VERSION 5.8 ;
BUSBITCHARS "[]" ;
DIVIDERCHAR "/" ;
UNITS
    DATABASE MICRONS 1000 ;
END UNITS

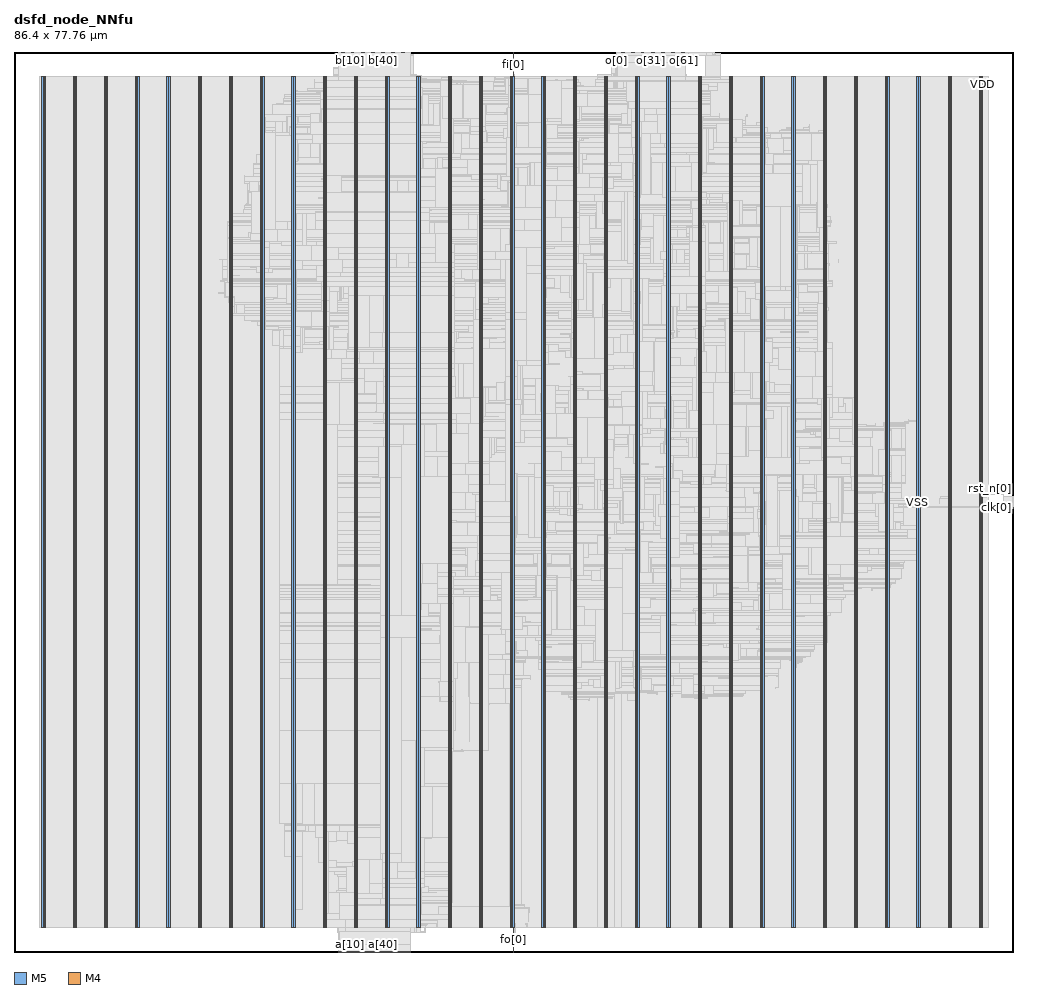
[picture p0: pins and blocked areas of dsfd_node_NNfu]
MACRO dsfd_node_NNfu
  FOREIGN dsfd_node_NNfu 0 0 ;
  CLASS BLOCK ;
  SIZE 86.4 BY 77.76 ;
  PIN a[0]
    DIRECTION INPUT ;
    USE SIGNAL ;
    PORT
      LAYER M5 ;
        RECT  28.032 0 28.056 0.084 ;
    END
  END a[0]
  PIN a[10]
    DIRECTION INPUT ;
    USE SIGNAL ;
    PORT
      LAYER M5 ;
        RECT  28.992 0 29.016 0.084 ;
    END
  END a[10]
  PIN a[11]
    DIRECTION INPUT ;
    USE SIGNAL ;
    PORT
      LAYER M5 ;
        RECT  29.088 0 29.112 0.084 ;
    END
  END a[11]
  PIN a[12]
    DIRECTION INPUT ;
    USE SIGNAL ;
    PORT
      LAYER M5 ;
        RECT  29.184 0 29.208 0.084 ;
    END
  END a[12]
  PIN a[13]
    DIRECTION INPUT ;
    USE SIGNAL ;
    PORT
      LAYER M5 ;
        RECT  29.28 0 29.304 0.084 ;
    END
  END a[13]
  PIN a[14]
    DIRECTION INPUT ;
    USE SIGNAL ;
    PORT
      LAYER M5 ;
        RECT  29.376 0 29.4 0.084 ;
    END
  END a[14]
  PIN a[15]
    DIRECTION INPUT ;
    USE SIGNAL ;
    PORT
      LAYER M5 ;
        RECT  29.472 0 29.496 0.084 ;
    END
  END a[15]
  PIN a[16]
    DIRECTION INPUT ;
    USE SIGNAL ;
    PORT
      LAYER M5 ;
        RECT  29.568 0 29.592 0.084 ;
    END
  END a[16]
  PIN a[17]
    DIRECTION INPUT ;
    USE SIGNAL ;
    PORT
      LAYER M5 ;
        RECT  29.664 0 29.688 0.084 ;
    END
  END a[17]
  PIN a[18]
    DIRECTION INPUT ;
    USE SIGNAL ;
    PORT
      LAYER M5 ;
        RECT  29.76 0 29.784 0.084 ;
    END
  END a[18]
  PIN a[19]
    DIRECTION INPUT ;
    USE SIGNAL ;
    PORT
      LAYER M5 ;
        RECT  29.856 0 29.88 0.084 ;
    END
  END a[19]
  PIN a[1]
    DIRECTION INPUT ;
    USE SIGNAL ;
    PORT
      LAYER M5 ;
        RECT  28.128 0 28.152 0.084 ;
    END
  END a[1]
  PIN a[20]
    DIRECTION INPUT ;
    USE SIGNAL ;
    PORT
      LAYER M5 ;
        RECT  29.952 0 29.976 0.084 ;
    END
  END a[20]
  PIN a[21]
    DIRECTION INPUT ;
    USE SIGNAL ;
    PORT
      LAYER M5 ;
        RECT  30.048 0 30.072 0.084 ;
    END
  END a[21]
  PIN a[22]
    DIRECTION INPUT ;
    USE SIGNAL ;
    PORT
      LAYER M5 ;
        RECT  30.144 0 30.168 0.084 ;
    END
  END a[22]
  PIN a[23]
    DIRECTION INPUT ;
    USE SIGNAL ;
    PORT
      LAYER M5 ;
        RECT  30.24 0 30.264 0.084 ;
    END
  END a[23]
  PIN a[24]
    DIRECTION INPUT ;
    USE SIGNAL ;
    PORT
      LAYER M5 ;
        RECT  30.336 0 30.36 0.084 ;
    END
  END a[24]
  PIN a[25]
    DIRECTION INPUT ;
    USE SIGNAL ;
    PORT
      LAYER M5 ;
        RECT  30.432 0 30.456 0.084 ;
    END
  END a[25]
  PIN a[26]
    DIRECTION INPUT ;
    USE SIGNAL ;
    PORT
      LAYER M5 ;
        RECT  30.528 0 30.552 0.084 ;
    END
  END a[26]
  PIN a[27]
    DIRECTION INPUT ;
    USE SIGNAL ;
    PORT
      LAYER M5 ;
        RECT  30.624 0 30.648 0.084 ;
    END
  END a[27]
  PIN a[28]
    DIRECTION INPUT ;
    USE SIGNAL ;
    PORT
      LAYER M5 ;
        RECT  30.72 0 30.744 0.084 ;
    END
  END a[28]
  PIN a[29]
    DIRECTION INPUT ;
    USE SIGNAL ;
    PORT
      LAYER M5 ;
        RECT  30.816 0 30.84 0.084 ;
    END
  END a[29]
  PIN a[2]
    DIRECTION INPUT ;
    USE SIGNAL ;
    PORT
      LAYER M5 ;
        RECT  28.224 0 28.248 0.084 ;
    END
  END a[2]
  PIN a[30]
    DIRECTION INPUT ;
    USE SIGNAL ;
    PORT
      LAYER M5 ;
        RECT  30.912 0 30.936 0.084 ;
    END
  END a[30]
  PIN a[31]
    DIRECTION INPUT ;
    USE SIGNAL ;
    PORT
      LAYER M5 ;
        RECT  31.008 0 31.032 0.084 ;
    END
  END a[31]
  PIN a[32]
    DIRECTION INPUT ;
    USE SIGNAL ;
    PORT
      LAYER M5 ;
        RECT  31.104 0 31.128 0.084 ;
    END
  END a[32]
  PIN a[33]
    DIRECTION INPUT ;
    USE SIGNAL ;
    PORT
      LAYER M5 ;
        RECT  31.2 0 31.224 0.084 ;
    END
  END a[33]
  PIN a[34]
    DIRECTION INPUT ;
    USE SIGNAL ;
    PORT
      LAYER M5 ;
        RECT  31.296 0 31.32 0.084 ;
    END
  END a[34]
  PIN a[35]
    DIRECTION INPUT ;
    USE SIGNAL ;
    PORT
      LAYER M5 ;
        RECT  31.392 0 31.416 0.084 ;
    END
  END a[35]
  PIN a[36]
    DIRECTION INPUT ;
    USE SIGNAL ;
    PORT
      LAYER M5 ;
        RECT  31.488 0 31.512 0.084 ;
    END
  END a[36]
  PIN a[37]
    DIRECTION INPUT ;
    USE SIGNAL ;
    PORT
      LAYER M5 ;
        RECT  31.584 0 31.608 0.084 ;
    END
  END a[37]
  PIN a[38]
    DIRECTION INPUT ;
    USE SIGNAL ;
    PORT
      LAYER M5 ;
        RECT  31.68 0 31.704 0.084 ;
    END
  END a[38]
  PIN a[39]
    DIRECTION INPUT ;
    USE SIGNAL ;
    PORT
      LAYER M5 ;
        RECT  31.776 0 31.8 0.084 ;
    END
  END a[39]
  PIN a[3]
    DIRECTION INPUT ;
    USE SIGNAL ;
    PORT
      LAYER M5 ;
        RECT  28.32 0 28.344 0.084 ;
    END
  END a[3]
  PIN a[40]
    DIRECTION INPUT ;
    USE SIGNAL ;
    PORT
      LAYER M5 ;
        RECT  31.872 0 31.896 0.084 ;
    END
  END a[40]
  PIN a[41]
    DIRECTION INPUT ;
    USE SIGNAL ;
    PORT
      LAYER M5 ;
        RECT  31.968 0 31.992 0.084 ;
    END
  END a[41]
  PIN a[42]
    DIRECTION INPUT ;
    USE SIGNAL ;
    PORT
      LAYER M5 ;
        RECT  32.064 0 32.088 0.084 ;
    END
  END a[42]
  PIN a[43]
    DIRECTION INPUT ;
    USE SIGNAL ;
    PORT
      LAYER M5 ;
        RECT  32.16 0 32.184 0.084 ;
    END
  END a[43]
  PIN a[44]
    DIRECTION INPUT ;
    USE SIGNAL ;
    PORT
      LAYER M5 ;
        RECT  32.256 0 32.28 0.084 ;
    END
  END a[44]
  PIN a[45]
    DIRECTION INPUT ;
    USE SIGNAL ;
    PORT
      LAYER M5 ;
        RECT  32.352 0 32.376 0.084 ;
    END
  END a[45]
  PIN a[46]
    DIRECTION INPUT ;
    USE SIGNAL ;
    PORT
      LAYER M5 ;
        RECT  32.448 0 32.472 0.084 ;
    END
  END a[46]
  PIN a[47]
    DIRECTION INPUT ;
    USE SIGNAL ;
    PORT
      LAYER M5 ;
        RECT  32.544 0 32.568 0.084 ;
    END
  END a[47]
  PIN a[48]
    DIRECTION INPUT ;
    USE SIGNAL ;
    PORT
      LAYER M5 ;
        RECT  32.64 0 32.664 0.084 ;
    END
  END a[48]
  PIN a[49]
    DIRECTION INPUT ;
    USE SIGNAL ;
    PORT
      LAYER M5 ;
        RECT  32.736 0 32.76 0.084 ;
    END
  END a[49]
  PIN a[4]
    DIRECTION INPUT ;
    USE SIGNAL ;
    PORT
      LAYER M5 ;
        RECT  28.416 0 28.44 0.084 ;
    END
  END a[4]
  PIN a[50]
    DIRECTION INPUT ;
    USE SIGNAL ;
    PORT
      LAYER M5 ;
        RECT  32.832 0 32.856 0.084 ;
    END
  END a[50]
  PIN a[51]
    DIRECTION INPUT ;
    USE SIGNAL ;
    PORT
      LAYER M5 ;
        RECT  32.928 0 32.952 0.084 ;
    END
  END a[51]
  PIN a[52]
    DIRECTION INPUT ;
    USE SIGNAL ;
    PORT
      LAYER M5 ;
        RECT  33.024 0 33.048 0.084 ;
    END
  END a[52]
  PIN a[53]
    DIRECTION INPUT ;
    USE SIGNAL ;
    PORT
      LAYER M5 ;
        RECT  33.12 0 33.144 0.084 ;
    END
  END a[53]
  PIN a[54]
    DIRECTION INPUT ;
    USE SIGNAL ;
    PORT
      LAYER M5 ;
        RECT  33.216 0 33.24 0.084 ;
    END
  END a[54]
  PIN a[55]
    DIRECTION INPUT ;
    USE SIGNAL ;
    PORT
      LAYER M5 ;
        RECT  33.312 0 33.336 0.084 ;
    END
  END a[55]
  PIN a[56]
    DIRECTION INPUT ;
    USE SIGNAL ;
    PORT
      LAYER M5 ;
        RECT  33.408 0 33.432 0.084 ;
    END
  END a[56]
  PIN a[57]
    DIRECTION INPUT ;
    USE SIGNAL ;
    PORT
      LAYER M5 ;
        RECT  33.504 0 33.528 0.084 ;
    END
  END a[57]
  PIN a[58]
    DIRECTION INPUT ;
    USE SIGNAL ;
    PORT
      LAYER M5 ;
        RECT  33.6 0 33.624 0.084 ;
    END
  END a[58]
  PIN a[59]
    DIRECTION INPUT ;
    USE SIGNAL ;
    PORT
      LAYER M5 ;
        RECT  33.696 0 33.72 0.084 ;
    END
  END a[59]
  PIN a[5]
    DIRECTION INPUT ;
    USE SIGNAL ;
    PORT
      LAYER M5 ;
        RECT  28.512 0 28.536 0.084 ;
    END
  END a[5]
  PIN a[60]
    DIRECTION INPUT ;
    USE SIGNAL ;
    PORT
      LAYER M5 ;
        RECT  33.792 0 33.816 0.084 ;
    END
  END a[60]
  PIN a[61]
    DIRECTION INPUT ;
    USE SIGNAL ;
    PORT
      LAYER M5 ;
        RECT  33.888 0 33.912 0.084 ;
    END
  END a[61]
  PIN a[62]
    DIRECTION INPUT ;
    USE SIGNAL ;
    PORT
      LAYER M5 ;
        RECT  33.984 0 34.008 0.084 ;
    END
  END a[62]
  PIN a[63]
    DIRECTION INPUT ;
    USE SIGNAL ;
    PORT
      LAYER M5 ;
        RECT  34.08 0 34.104 0.084 ;
    END
  END a[63]
  PIN a[64]
    DIRECTION INPUT ;
    USE SIGNAL ;
    PORT
      LAYER M5 ;
        RECT  34.176 0 34.2 0.084 ;
    END
  END a[64]
  PIN a[65]
    DIRECTION INPUT ;
    USE SIGNAL ;
    PORT
      LAYER M5 ;
        RECT  34.272 0 34.296 0.084 ;
    END
  END a[65]
  PIN a[6]
    DIRECTION INPUT ;
    USE SIGNAL ;
    PORT
      LAYER M5 ;
        RECT  28.608 0 28.632 0.084 ;
    END
  END a[6]
  PIN a[7]
    DIRECTION INPUT ;
    USE SIGNAL ;
    PORT
      LAYER M5 ;
        RECT  28.704 0 28.728 0.084 ;
    END
  END a[7]
  PIN a[8]
    DIRECTION INPUT ;
    USE SIGNAL ;
    PORT
      LAYER M5 ;
        RECT  28.8 0 28.824 0.084 ;
    END
  END a[8]
  PIN a[9]
    DIRECTION INPUT ;
    USE SIGNAL ;
    PORT
      LAYER M5 ;
        RECT  28.896 0 28.92 0.084 ;
    END
  END a[9]
  PIN b[0]
    DIRECTION INPUT ;
    USE SIGNAL ;
    PORT
      LAYER M5 ;
        RECT  28.032 77.676 28.056 77.76 ;
    END
  END b[0]
  PIN b[10]
    DIRECTION INPUT ;
    USE SIGNAL ;
    PORT
      LAYER M5 ;
        RECT  28.992 77.676 29.016 77.76 ;
    END
  END b[10]
  PIN b[11]
    DIRECTION INPUT ;
    USE SIGNAL ;
    PORT
      LAYER M5 ;
        RECT  29.088 77.676 29.112 77.76 ;
    END
  END b[11]
  PIN b[12]
    DIRECTION INPUT ;
    USE SIGNAL ;
    PORT
      LAYER M5 ;
        RECT  29.184 77.676 29.208 77.76 ;
    END
  END b[12]
  PIN b[13]
    DIRECTION INPUT ;
    USE SIGNAL ;
    PORT
      LAYER M5 ;
        RECT  29.28 77.676 29.304 77.76 ;
    END
  END b[13]
  PIN b[14]
    DIRECTION INPUT ;
    USE SIGNAL ;
    PORT
      LAYER M5 ;
        RECT  29.376 77.676 29.4 77.76 ;
    END
  END b[14]
  PIN b[15]
    DIRECTION INPUT ;
    USE SIGNAL ;
    PORT
      LAYER M5 ;
        RECT  29.472 77.676 29.496 77.76 ;
    END
  END b[15]
  PIN b[16]
    DIRECTION INPUT ;
    USE SIGNAL ;
    PORT
      LAYER M5 ;
        RECT  29.568 77.676 29.592 77.76 ;
    END
  END b[16]
  PIN b[17]
    DIRECTION INPUT ;
    USE SIGNAL ;
    PORT
      LAYER M5 ;
        RECT  29.664 77.676 29.688 77.76 ;
    END
  END b[17]
  PIN b[18]
    DIRECTION INPUT ;
    USE SIGNAL ;
    PORT
      LAYER M5 ;
        RECT  29.76 77.676 29.784 77.76 ;
    END
  END b[18]
  PIN b[19]
    DIRECTION INPUT ;
    USE SIGNAL ;
    PORT
      LAYER M5 ;
        RECT  29.856 77.676 29.88 77.76 ;
    END
  END b[19]
  PIN b[1]
    DIRECTION INPUT ;
    USE SIGNAL ;
    PORT
      LAYER M5 ;
        RECT  28.128 77.676 28.152 77.76 ;
    END
  END b[1]
  PIN b[20]
    DIRECTION INPUT ;
    USE SIGNAL ;
    PORT
      LAYER M5 ;
        RECT  29.952 77.676 29.976 77.76 ;
    END
  END b[20]
  PIN b[21]
    DIRECTION INPUT ;
    USE SIGNAL ;
    PORT
      LAYER M5 ;
        RECT  30.048 77.676 30.072 77.76 ;
    END
  END b[21]
  PIN b[22]
    DIRECTION INPUT ;
    USE SIGNAL ;
    PORT
      LAYER M5 ;
        RECT  30.144 77.676 30.168 77.76 ;
    END
  END b[22]
  PIN b[23]
    DIRECTION INPUT ;
    USE SIGNAL ;
    PORT
      LAYER M5 ;
        RECT  30.24 77.676 30.264 77.76 ;
    END
  END b[23]
  PIN b[24]
    DIRECTION INPUT ;
    USE SIGNAL ;
    PORT
      LAYER M5 ;
        RECT  30.336 77.676 30.36 77.76 ;
    END
  END b[24]
  PIN b[25]
    DIRECTION INPUT ;
    USE SIGNAL ;
    PORT
      LAYER M5 ;
        RECT  30.432 77.676 30.456 77.76 ;
    END
  END b[25]
  PIN b[26]
    DIRECTION INPUT ;
    USE SIGNAL ;
    PORT
      LAYER M5 ;
        RECT  30.528 77.676 30.552 77.76 ;
    END
  END b[26]
  PIN b[27]
    DIRECTION INPUT ;
    USE SIGNAL ;
    PORT
      LAYER M5 ;
        RECT  30.624 77.676 30.648 77.76 ;
    END
  END b[27]
  PIN b[28]
    DIRECTION INPUT ;
    USE SIGNAL ;
    PORT
      LAYER M5 ;
        RECT  30.72 77.676 30.744 77.76 ;
    END
  END b[28]
  PIN b[29]
    DIRECTION INPUT ;
    USE SIGNAL ;
    PORT
      LAYER M5 ;
        RECT  30.816 77.676 30.84 77.76 ;
    END
  END b[29]
  PIN b[2]
    DIRECTION INPUT ;
    USE SIGNAL ;
    PORT
      LAYER M5 ;
        RECT  28.224 77.676 28.248 77.76 ;
    END
  END b[2]
  PIN b[30]
    DIRECTION INPUT ;
    USE SIGNAL ;
    PORT
      LAYER M5 ;
        RECT  30.912 77.676 30.936 77.76 ;
    END
  END b[30]
  PIN b[31]
    DIRECTION INPUT ;
    USE SIGNAL ;
    PORT
      LAYER M5 ;
        RECT  31.008 77.676 31.032 77.76 ;
    END
  END b[31]
  PIN b[32]
    DIRECTION INPUT ;
    USE SIGNAL ;
    PORT
      LAYER M5 ;
        RECT  31.104 77.676 31.128 77.76 ;
    END
  END b[32]
  PIN b[33]
    DIRECTION INPUT ;
    USE SIGNAL ;
    PORT
      LAYER M5 ;
        RECT  31.2 77.676 31.224 77.76 ;
    END
  END b[33]
  PIN b[34]
    DIRECTION INPUT ;
    USE SIGNAL ;
    PORT
      LAYER M5 ;
        RECT  31.296 77.676 31.32 77.76 ;
    END
  END b[34]
  PIN b[35]
    DIRECTION INPUT ;
    USE SIGNAL ;
    PORT
      LAYER M5 ;
        RECT  31.392 77.676 31.416 77.76 ;
    END
  END b[35]
  PIN b[36]
    DIRECTION INPUT ;
    USE SIGNAL ;
    PORT
      LAYER M5 ;
        RECT  31.488 77.676 31.512 77.76 ;
    END
  END b[36]
  PIN b[37]
    DIRECTION INPUT ;
    USE SIGNAL ;
    PORT
      LAYER M5 ;
        RECT  31.584 77.676 31.608 77.76 ;
    END
  END b[37]
  PIN b[38]
    DIRECTION INPUT ;
    USE SIGNAL ;
    PORT
      LAYER M5 ;
        RECT  31.68 77.676 31.704 77.76 ;
    END
  END b[38]
  PIN b[39]
    DIRECTION INPUT ;
    USE SIGNAL ;
    PORT
      LAYER M5 ;
        RECT  31.776 77.676 31.8 77.76 ;
    END
  END b[39]
  PIN b[3]
    DIRECTION INPUT ;
    USE SIGNAL ;
    PORT
      LAYER M5 ;
        RECT  28.32 77.676 28.344 77.76 ;
    END
  END b[3]
  PIN b[40]
    DIRECTION INPUT ;
    USE SIGNAL ;
    PORT
      LAYER M5 ;
        RECT  31.872 77.676 31.896 77.76 ;
    END
  END b[40]
  PIN b[41]
    DIRECTION INPUT ;
    USE SIGNAL ;
    PORT
      LAYER M5 ;
        RECT  31.968 77.676 31.992 77.76 ;
    END
  END b[41]
  PIN b[42]
    DIRECTION INPUT ;
    USE SIGNAL ;
    PORT
      LAYER M5 ;
        RECT  32.064 77.676 32.088 77.76 ;
    END
  END b[42]
  PIN b[43]
    DIRECTION INPUT ;
    USE SIGNAL ;
    PORT
      LAYER M5 ;
        RECT  32.16 77.676 32.184 77.76 ;
    END
  END b[43]
  PIN b[44]
    DIRECTION INPUT ;
    USE SIGNAL ;
    PORT
      LAYER M5 ;
        RECT  32.256 77.676 32.28 77.76 ;
    END
  END b[44]
  PIN b[45]
    DIRECTION INPUT ;
    USE SIGNAL ;
    PORT
      LAYER M5 ;
        RECT  32.352 77.676 32.376 77.76 ;
    END
  END b[45]
  PIN b[46]
    DIRECTION INPUT ;
    USE SIGNAL ;
    PORT
      LAYER M5 ;
        RECT  32.448 77.676 32.472 77.76 ;
    END
  END b[46]
  PIN b[47]
    DIRECTION INPUT ;
    USE SIGNAL ;
    PORT
      LAYER M5 ;
        RECT  32.544 77.676 32.568 77.76 ;
    END
  END b[47]
  PIN b[48]
    DIRECTION INPUT ;
    USE SIGNAL ;
    PORT
      LAYER M5 ;
        RECT  32.64 77.676 32.664 77.76 ;
    END
  END b[48]
  PIN b[49]
    DIRECTION INPUT ;
    USE SIGNAL ;
    PORT
      LAYER M5 ;
        RECT  32.736 77.676 32.76 77.76 ;
    END
  END b[49]
  PIN b[4]
    DIRECTION INPUT ;
    USE SIGNAL ;
    PORT
      LAYER M5 ;
        RECT  28.416 77.676 28.44 77.76 ;
    END
  END b[4]
  PIN b[50]
    DIRECTION INPUT ;
    USE SIGNAL ;
    PORT
      LAYER M5 ;
        RECT  32.832 77.676 32.856 77.76 ;
    END
  END b[50]
  PIN b[51]
    DIRECTION INPUT ;
    USE SIGNAL ;
    PORT
      LAYER M5 ;
        RECT  32.928 77.676 32.952 77.76 ;
    END
  END b[51]
  PIN b[52]
    DIRECTION INPUT ;
    USE SIGNAL ;
    PORT
      LAYER M5 ;
        RECT  33.024 77.676 33.048 77.76 ;
    END
  END b[52]
  PIN b[53]
    DIRECTION INPUT ;
    USE SIGNAL ;
    PORT
      LAYER M5 ;
        RECT  33.12 77.676 33.144 77.76 ;
    END
  END b[53]
  PIN b[54]
    DIRECTION INPUT ;
    USE SIGNAL ;
    PORT
      LAYER M5 ;
        RECT  33.216 77.676 33.24 77.76 ;
    END
  END b[54]
  PIN b[55]
    DIRECTION INPUT ;
    USE SIGNAL ;
    PORT
      LAYER M5 ;
        RECT  33.312 77.676 33.336 77.76 ;
    END
  END b[55]
  PIN b[56]
    DIRECTION INPUT ;
    USE SIGNAL ;
    PORT
      LAYER M5 ;
        RECT  33.408 77.676 33.432 77.76 ;
    END
  END b[56]
  PIN b[57]
    DIRECTION INPUT ;
    USE SIGNAL ;
    PORT
      LAYER M5 ;
        RECT  33.504 77.676 33.528 77.76 ;
    END
  END b[57]
  PIN b[58]
    DIRECTION INPUT ;
    USE SIGNAL ;
    PORT
      LAYER M5 ;
        RECT  33.6 77.676 33.624 77.76 ;
    END
  END b[58]
  PIN b[59]
    DIRECTION INPUT ;
    USE SIGNAL ;
    PORT
      LAYER M5 ;
        RECT  33.696 77.676 33.72 77.76 ;
    END
  END b[59]
  PIN b[5]
    DIRECTION INPUT ;
    USE SIGNAL ;
    PORT
      LAYER M5 ;
        RECT  28.512 77.676 28.536 77.76 ;
    END
  END b[5]
  PIN b[60]
    DIRECTION INPUT ;
    USE SIGNAL ;
    PORT
      LAYER M5 ;
        RECT  33.792 77.676 33.816 77.76 ;
    END
  END b[60]
  PIN b[61]
    DIRECTION INPUT ;
    USE SIGNAL ;
    PORT
      LAYER M5 ;
        RECT  33.888 77.676 33.912 77.76 ;
    END
  END b[61]
  PIN b[62]
    DIRECTION INPUT ;
    USE SIGNAL ;
    PORT
      LAYER M5 ;
        RECT  33.984 77.676 34.008 77.76 ;
    END
  END b[62]
  PIN b[63]
    DIRECTION INPUT ;
    USE SIGNAL ;
    PORT
      LAYER M5 ;
        RECT  34.08 77.676 34.104 77.76 ;
    END
  END b[63]
  PIN b[64]
    DIRECTION INPUT ;
    USE SIGNAL ;
    PORT
      LAYER M5 ;
        RECT  34.176 77.676 34.2 77.76 ;
    END
  END b[64]
  PIN b[65]
    DIRECTION INPUT ;
    USE SIGNAL ;
    PORT
      LAYER M5 ;
        RECT  34.272 77.676 34.296 77.76 ;
    END
  END b[65]
  PIN b[6]
    DIRECTION INPUT ;
    USE SIGNAL ;
    PORT
      LAYER M5 ;
        RECT  28.608 77.676 28.632 77.76 ;
    END
  END b[6]
  PIN b[7]
    DIRECTION INPUT ;
    USE SIGNAL ;
    PORT
      LAYER M5 ;
        RECT  28.704 77.676 28.728 77.76 ;
    END
  END b[7]
  PIN b[8]
    DIRECTION INPUT ;
    USE SIGNAL ;
    PORT
      LAYER M5 ;
        RECT  28.8 77.676 28.824 77.76 ;
    END
  END b[8]
  PIN b[9]
    DIRECTION INPUT ;
    USE SIGNAL ;
    PORT
      LAYER M5 ;
        RECT  28.896 77.676 28.92 77.76 ;
    END
  END b[9]
  PIN clk[0]
    DIRECTION INPUT ;
    USE SIGNAL ;
    PORT
      LAYER M4 ;
        RECT  86.316 38.352 86.4 38.376 ;
    END
    PORT
      LAYER M4 ;
        RECT  86.321 38.352 86.364 38.376 ;
    END
  END clk[0]
  PIN fi[0]
    DIRECTION INPUT ;
    USE SIGNAL ;
    PORT
      LAYER M5 ;
        RECT  43.152 77.676 43.176 77.76 ;
    END
    PORT
      LAYER M5 ;
        RECT  43.152 75.623 43.176 77.712 ;
    END
  END fi[0]
  PIN fo[0]
    DIRECTION OUTPUT ;
    USE SIGNAL ;
    PORT
      LAYER M5 ;
        RECT  43.152 0 43.176 0.084 ;
    END
    PORT
      LAYER M5 ;
        RECT  43.152 0.016 43.176 2.137 ;
    END
  END fo[0]
  PIN o[0]
    DIRECTION OUTPUT ;
    USE SIGNAL ;
    PORT
      LAYER M5 ;
        RECT  52.032 77.676 52.056 77.76 ;
    END
  END o[0]
  PIN o[10]
    DIRECTION OUTPUT ;
    USE SIGNAL ;
    PORT
      LAYER M5 ;
        RECT  52.992 77.676 53.016 77.76 ;
    END
  END o[10]
  PIN o[11]
    DIRECTION OUTPUT ;
    USE SIGNAL ;
    PORT
      LAYER M5 ;
        RECT  53.088 77.676 53.112 77.76 ;
    END
  END o[11]
  PIN o[12]
    DIRECTION OUTPUT ;
    USE SIGNAL ;
    PORT
      LAYER M5 ;
        RECT  53.184 77.676 53.208 77.76 ;
    END
  END o[12]
  PIN o[13]
    DIRECTION OUTPUT ;
    USE SIGNAL ;
    PORT
      LAYER M5 ;
        RECT  53.28 77.676 53.304 77.76 ;
    END
  END o[13]
  PIN o[14]
    DIRECTION OUTPUT ;
    USE SIGNAL ;
    PORT
      LAYER M5 ;
        RECT  53.376 77.676 53.4 77.76 ;
    END
  END o[14]
  PIN o[15]
    DIRECTION OUTPUT ;
    USE SIGNAL ;
    PORT
      LAYER M5 ;
        RECT  53.472 77.676 53.496 77.76 ;
    END
  END o[15]
  PIN o[16]
    DIRECTION OUTPUT ;
    USE SIGNAL ;
    PORT
      LAYER M5 ;
        RECT  53.568 77.676 53.592 77.76 ;
    END
  END o[16]
  PIN o[17]
    DIRECTION OUTPUT ;
    USE SIGNAL ;
    PORT
      LAYER M5 ;
        RECT  53.664 77.676 53.688 77.76 ;
    END
  END o[17]
  PIN o[18]
    DIRECTION OUTPUT ;
    USE SIGNAL ;
    PORT
      LAYER M5 ;
        RECT  53.76 77.676 53.784 77.76 ;
    END
  END o[18]
  PIN o[19]
    DIRECTION OUTPUT ;
    USE SIGNAL ;
    PORT
      LAYER M5 ;
        RECT  53.856 77.676 53.88 77.76 ;
    END
  END o[19]
  PIN o[1]
    DIRECTION OUTPUT ;
    USE SIGNAL ;
    PORT
      LAYER M5 ;
        RECT  52.128 77.676 52.152 77.76 ;
    END
  END o[1]
  PIN o[20]
    DIRECTION OUTPUT ;
    USE SIGNAL ;
    PORT
      LAYER M5 ;
        RECT  53.952 77.676 53.976 77.76 ;
    END
  END o[20]
  PIN o[21]
    DIRECTION OUTPUT ;
    USE SIGNAL ;
    PORT
      LAYER M5 ;
        RECT  54.048 77.676 54.072 77.76 ;
    END
  END o[21]
  PIN o[22]
    DIRECTION OUTPUT ;
    USE SIGNAL ;
    PORT
      LAYER M5 ;
        RECT  54.144 77.676 54.168 77.76 ;
    END
  END o[22]
  PIN o[23]
    DIRECTION OUTPUT ;
    USE SIGNAL ;
    PORT
      LAYER M5 ;
        RECT  54.24 77.676 54.264 77.76 ;
    END
  END o[23]
  PIN o[24]
    DIRECTION OUTPUT ;
    USE SIGNAL ;
    PORT
      LAYER M5 ;
        RECT  54.336 77.676 54.36 77.76 ;
    END
  END o[24]
  PIN o[25]
    DIRECTION OUTPUT ;
    USE SIGNAL ;
    PORT
      LAYER M5 ;
        RECT  54.432 77.676 54.456 77.76 ;
    END
  END o[25]
  PIN o[26]
    DIRECTION OUTPUT ;
    USE SIGNAL ;
    PORT
      LAYER M5 ;
        RECT  54.528 77.676 54.552 77.76 ;
    END
  END o[26]
  PIN o[27]
    DIRECTION OUTPUT ;
    USE SIGNAL ;
    PORT
      LAYER M5 ;
        RECT  54.624 77.676 54.648 77.76 ;
    END
  END o[27]
  PIN o[28]
    DIRECTION OUTPUT ;
    USE SIGNAL ;
    PORT
      LAYER M5 ;
        RECT  54.72 77.676 54.744 77.76 ;
    END
  END o[28]
  PIN o[29]
    DIRECTION OUTPUT ;
    USE SIGNAL ;
    PORT
      LAYER M5 ;
        RECT  54.816 77.676 54.84 77.76 ;
    END
  END o[29]
  PIN o[2]
    DIRECTION OUTPUT ;
    USE SIGNAL ;
    PORT
      LAYER M5 ;
        RECT  52.224 77.676 52.248 77.76 ;
    END
  END o[2]
  PIN o[30]
    DIRECTION OUTPUT ;
    USE SIGNAL ;
    PORT
      LAYER M5 ;
        RECT  54.912 77.676 54.936 77.76 ;
    END
  END o[30]
  PIN o[31]
    DIRECTION OUTPUT ;
    USE SIGNAL ;
    PORT
      LAYER M5 ;
        RECT  55.008 77.676 55.032 77.76 ;
    END
  END o[31]
  PIN o[32]
    DIRECTION OUTPUT ;
    USE SIGNAL ;
    PORT
      LAYER M5 ;
        RECT  55.104 77.676 55.128 77.76 ;
    END
  END o[32]
  PIN o[33]
    DIRECTION OUTPUT ;
    USE SIGNAL ;
    PORT
      LAYER M5 ;
        RECT  55.2 77.676 55.224 77.76 ;
    END
  END o[33]
  PIN o[34]
    DIRECTION OUTPUT ;
    USE SIGNAL ;
    PORT
      LAYER M5 ;
        RECT  55.296 77.676 55.32 77.76 ;
    END
  END o[34]
  PIN o[35]
    DIRECTION OUTPUT ;
    USE SIGNAL ;
    PORT
      LAYER M5 ;
        RECT  55.392 77.676 55.416 77.76 ;
    END
  END o[35]
  PIN o[36]
    DIRECTION OUTPUT ;
    USE SIGNAL ;
    PORT
      LAYER M5 ;
        RECT  55.488 77.676 55.512 77.76 ;
    END
  END o[36]
  PIN o[37]
    DIRECTION OUTPUT ;
    USE SIGNAL ;
    PORT
      LAYER M5 ;
        RECT  55.584 77.676 55.608 77.76 ;
    END
  END o[37]
  PIN o[38]
    DIRECTION OUTPUT ;
    USE SIGNAL ;
    PORT
      LAYER M5 ;
        RECT  55.68 77.676 55.704 77.76 ;
    END
  END o[38]
  PIN o[39]
    DIRECTION OUTPUT ;
    USE SIGNAL ;
    PORT
      LAYER M5 ;
        RECT  55.776 77.676 55.8 77.76 ;
    END
  END o[39]
  PIN o[3]
    DIRECTION OUTPUT ;
    USE SIGNAL ;
    PORT
      LAYER M5 ;
        RECT  52.32 77.676 52.344 77.76 ;
    END
  END o[3]
  PIN o[40]
    DIRECTION OUTPUT ;
    USE SIGNAL ;
    PORT
      LAYER M5 ;
        RECT  55.872 77.676 55.896 77.76 ;
    END
  END o[40]
  PIN o[41]
    DIRECTION OUTPUT ;
    USE SIGNAL ;
    PORT
      LAYER M5 ;
        RECT  55.968 77.676 55.992 77.76 ;
    END
  END o[41]
  PIN o[42]
    DIRECTION OUTPUT ;
    USE SIGNAL ;
    PORT
      LAYER M5 ;
        RECT  56.064 77.676 56.088 77.76 ;
    END
  END o[42]
  PIN o[43]
    DIRECTION OUTPUT ;
    USE SIGNAL ;
    PORT
      LAYER M5 ;
        RECT  56.16 77.676 56.184 77.76 ;
    END
  END o[43]
  PIN o[44]
    DIRECTION OUTPUT ;
    USE SIGNAL ;
    PORT
      LAYER M5 ;
        RECT  56.256 77.676 56.28 77.76 ;
    END
  END o[44]
  PIN o[45]
    DIRECTION OUTPUT ;
    USE SIGNAL ;
    PORT
      LAYER M5 ;
        RECT  56.352 77.676 56.376 77.76 ;
    END
  END o[45]
  PIN o[46]
    DIRECTION OUTPUT ;
    USE SIGNAL ;
    PORT
      LAYER M5 ;
        RECT  56.448 77.676 56.472 77.76 ;
    END
  END o[46]
  PIN o[47]
    DIRECTION OUTPUT ;
    USE SIGNAL ;
    PORT
      LAYER M5 ;
        RECT  56.544 77.676 56.568 77.76 ;
    END
  END o[47]
  PIN o[48]
    DIRECTION OUTPUT ;
    USE SIGNAL ;
    PORT
      LAYER M5 ;
        RECT  56.64 77.676 56.664 77.76 ;
    END
  END o[48]
  PIN o[49]
    DIRECTION OUTPUT ;
    USE SIGNAL ;
    PORT
      LAYER M5 ;
        RECT  56.736 77.676 56.76 77.76 ;
    END
  END o[49]
  PIN o[4]
    DIRECTION OUTPUT ;
    USE SIGNAL ;
    PORT
      LAYER M5 ;
        RECT  52.416 77.676 52.44 77.76 ;
    END
  END o[4]
  PIN o[50]
    DIRECTION OUTPUT ;
    USE SIGNAL ;
    PORT
      LAYER M5 ;
        RECT  56.832 77.676 56.856 77.76 ;
    END
  END o[50]
  PIN o[51]
    DIRECTION OUTPUT ;
    USE SIGNAL ;
    PORT
      LAYER M5 ;
        RECT  56.928 77.676 56.952 77.76 ;
    END
  END o[51]
  PIN o[52]
    DIRECTION OUTPUT ;
    USE SIGNAL ;
    PORT
      LAYER M5 ;
        RECT  57.024 77.676 57.048 77.76 ;
    END
  END o[52]
  PIN o[53]
    DIRECTION OUTPUT ;
    USE SIGNAL ;
    PORT
      LAYER M5 ;
        RECT  57.12 77.676 57.144 77.76 ;
    END
  END o[53]
  PIN o[54]
    DIRECTION OUTPUT ;
    USE SIGNAL ;
    PORT
      LAYER M5 ;
        RECT  57.216 77.676 57.24 77.76 ;
    END
  END o[54]
  PIN o[55]
    DIRECTION OUTPUT ;
    USE SIGNAL ;
    PORT
      LAYER M5 ;
        RECT  57.312 77.676 57.336 77.76 ;
    END
  END o[55]
  PIN o[56]
    DIRECTION OUTPUT ;
    USE SIGNAL ;
    PORT
      LAYER M5 ;
        RECT  57.408 77.676 57.432 77.76 ;
    END
  END o[56]
  PIN o[57]
    DIRECTION OUTPUT ;
    USE SIGNAL ;
    PORT
      LAYER M5 ;
        RECT  57.504 77.676 57.528 77.76 ;
    END
  END o[57]
  PIN o[58]
    DIRECTION OUTPUT ;
    USE SIGNAL ;
    PORT
      LAYER M5 ;
        RECT  57.6 77.676 57.624 77.76 ;
    END
  END o[58]
  PIN o[59]
    DIRECTION OUTPUT ;
    USE SIGNAL ;
    PORT
      LAYER M5 ;
        RECT  57.696 77.676 57.72 77.76 ;
    END
  END o[59]
  PIN o[5]
    DIRECTION OUTPUT ;
    USE SIGNAL ;
    PORT
      LAYER M5 ;
        RECT  52.512 77.676 52.536 77.76 ;
    END
  END o[5]
  PIN o[60]
    DIRECTION OUTPUT ;
    USE SIGNAL ;
    PORT
      LAYER M5 ;
        RECT  57.792 77.676 57.816 77.76 ;
    END
  END o[60]
  PIN o[61]
    DIRECTION OUTPUT ;
    USE SIGNAL ;
    PORT
      LAYER M5 ;
        RECT  57.888 77.676 57.912 77.76 ;
    END
  END o[61]
  PIN o[62]
    DIRECTION OUTPUT ;
    USE SIGNAL ;
    PORT
      LAYER M5 ;
        RECT  57.984 77.676 58.008 77.76 ;
    END
  END o[62]
  PIN o[63]
    DIRECTION OUTPUT ;
    USE SIGNAL ;
    PORT
      LAYER M5 ;
        RECT  58.08 77.676 58.104 77.76 ;
    END
  END o[63]
  PIN o[64]
    DIRECTION OUTPUT ;
    USE SIGNAL ;
    PORT
      LAYER M5 ;
        RECT  58.176 77.676 58.2 77.76 ;
    END
  END o[64]
  PIN o[65]
    DIRECTION OUTPUT ;
    USE SIGNAL ;
    PORT
      LAYER M5 ;
        RECT  58.272 77.676 58.296 77.76 ;
    END
  END o[65]
  PIN o[6]
    DIRECTION OUTPUT ;
    USE SIGNAL ;
    PORT
      LAYER M5 ;
        RECT  52.608 77.676 52.632 77.76 ;
    END
  END o[6]
  PIN o[7]
    DIRECTION OUTPUT ;
    USE SIGNAL ;
    PORT
      LAYER M5 ;
        RECT  52.704 77.676 52.728 77.76 ;
    END
  END o[7]
  PIN o[8]
    DIRECTION OUTPUT ;
    USE SIGNAL ;
    PORT
      LAYER M5 ;
        RECT  52.8 77.676 52.824 77.76 ;
    END
  END o[8]
  PIN o[9]
    DIRECTION OUTPUT ;
    USE SIGNAL ;
    PORT
      LAYER M5 ;
        RECT  52.896 77.676 52.92 77.76 ;
    END
  END o[9]
  PIN rst_n[0]
    DIRECTION INPUT ;
    USE SIGNAL ;
    PORT
      LAYER M4 ;
        RECT  86.316 39.36 86.4 39.384 ;
    END
    PORT
      LAYER M4 ;
        RECT  86.321 39.36 86.364 39.384 ;
    END
  END rst_n[0]
  PIN VDD
    DIRECTION INOUT ;
    USE POWER ;
    PORT
      LAYER M5 ;
        RECT  83.592 2.151 83.712 75.609 ;
        RECT  80.892 2.151 81.012 75.609 ;
        RECT  78.192 2.151 78.312 75.609 ;
        RECT  75.492 2.151 75.612 75.609 ;
        RECT  72.792 2.151 72.912 75.609 ;
        RECT  70.092 2.151 70.212 75.609 ;
        RECT  67.392 2.151 67.512 75.609 ;
        RECT  64.692 2.151 64.812 75.609 ;
        RECT  61.992 2.151 62.112 75.609 ;
        RECT  59.292 2.151 59.412 75.609 ;
        RECT  56.592 2.151 56.712 75.609 ;
        RECT  53.892 2.151 54.012 75.609 ;
        RECT  51.192 2.151 51.312 75.609 ;
        RECT  48.492 2.151 48.612 75.609 ;
        RECT  45.792 2.151 45.912 75.609 ;
        RECT  43.092 2.151 43.212 75.609 ;
        RECT  40.392 2.151 40.512 75.609 ;
        RECT  37.692 2.151 37.812 75.609 ;
        RECT  34.992 2.151 35.112 75.609 ;
        RECT  32.292 2.151 32.412 75.609 ;
        RECT  29.592 2.151 29.712 75.609 ;
        RECT  26.892 2.151 27.012 75.609 ;
        RECT  24.192 2.151 24.312 75.609 ;
        RECT  21.492 2.151 21.612 75.609 ;
        RECT  18.792 2.151 18.912 75.609 ;
        RECT  16.092 2.151 16.212 75.609 ;
        RECT  13.392 2.151 13.512 75.609 ;
        RECT  10.692 2.151 10.812 75.609 ;
        RECT  7.992 2.151 8.112 75.609 ;
        RECT  5.292 2.151 5.412 75.609 ;
        RECT  2.592 2.151 2.712 75.609 ;
    END
  END VDD
  PIN VSS
    DIRECTION INOUT ;
    USE GROUND ;
    PORT
      LAYER M5 ;
        RECT  83.4 2.137 83.52 75.623 ;
        RECT  80.7 2.137 80.82 75.623 ;
        RECT  78 2.137 78.12 75.623 ;
        RECT  75.3 2.137 75.42 75.623 ;
        RECT  72.6 2.137 72.72 75.623 ;
        RECT  69.9 2.137 70.02 75.623 ;
        RECT  67.2 2.137 67.32 75.623 ;
        RECT  64.5 2.137 64.62 75.623 ;
        RECT  61.8 2.137 61.92 75.623 ;
        RECT  59.1 2.137 59.22 75.623 ;
        RECT  56.4 2.137 56.52 75.623 ;
        RECT  53.7 2.137 53.82 75.623 ;
        RECT  51 2.137 51.12 75.623 ;
        RECT  48.3 2.137 48.42 75.623 ;
        RECT  45.6 2.137 45.72 75.623 ;
        RECT  42.9 2.137 43.02 75.623 ;
        RECT  40.2 2.137 40.32 75.623 ;
        RECT  37.5 2.137 37.62 75.623 ;
        RECT  34.8 2.137 34.92 75.623 ;
        RECT  32.1 2.137 32.22 75.623 ;
        RECT  29.4 2.137 29.52 75.623 ;
        RECT  26.7 2.137 26.82 75.623 ;
        RECT  24 2.137 24.12 75.623 ;
        RECT  21.3 2.137 21.42 75.623 ;
        RECT  18.6 2.137 18.72 75.623 ;
        RECT  15.9 2.137 16.02 75.623 ;
        RECT  13.2 2.137 13.32 75.623 ;
        RECT  10.5 2.137 10.62 75.623 ;
        RECT  7.8 2.137 7.92 75.623 ;
        RECT  5.1 2.137 5.22 75.623 ;
        RECT  2.4 2.137 2.52 75.623 ;
    END
  END VSS
  # OT_OBS_CLOSED layer=M5 d_um=1.536 added=220
  OBS
    LAYER RVTN ;
     RECT  2.16 2.16 84.24 2.295 ;
     RECT  2.16 2.565 84.24 2.835 ;
     RECT  2.16 3.105 84.24 3.375 ;
     RECT  2.16 3.645 84.24 3.915 ;
     RECT  2.16 4.185 84.24 4.455 ;
     RECT  2.16 4.725 84.24 4.995 ;
     RECT  2.16 5.265 84.24 5.535 ;
     RECT  2.16 5.805 84.24 6.075 ;
     RECT  2.16 6.345 84.24 6.615 ;
     RECT  2.16 6.885 84.24 7.155 ;
     RECT  2.16 7.425 84.24 7.695 ;
     RECT  2.16 7.965 84.24 8.235 ;
     RECT  2.16 8.505 84.24 8.775 ;
     RECT  2.16 9.045 84.24 9.315 ;
     RECT  2.16 9.585 84.24 9.855 ;
     RECT  2.16 10.125 84.24 10.395 ;
     RECT  2.16 10.665 84.24 10.935 ;
     RECT  2.16 11.205 84.24 11.475 ;
     RECT  2.16 11.745 84.24 12.015 ;
     RECT  2.16 12.285 84.24 12.555 ;
     RECT  2.16 12.825 84.24 13.095 ;
     RECT  2.16 13.365 84.24 13.635 ;
     RECT  2.16 13.905 84.24 14.175 ;
     RECT  2.16 14.445 84.24 14.715 ;
     RECT  2.16 14.985 84.24 15.255 ;
     RECT  2.16 15.525 84.24 15.795 ;
     RECT  2.16 16.065 84.24 16.335 ;
     RECT  2.16 16.605 84.24 16.875 ;
     RECT  2.16 17.145 84.24 17.415 ;
     RECT  2.16 17.685 84.24 17.955 ;
     RECT  2.16 18.225 84.24 18.495 ;
     RECT  2.16 18.765 84.24 19.035 ;
     RECT  2.16 19.305 84.24 19.575 ;
     RECT  2.16 19.845 84.24 20.115 ;
     RECT  2.16 20.385 84.24 20.655 ;
     RECT  2.16 20.925 84.24 21.195 ;
     RECT  2.16 21.465 84.24 21.735 ;
     RECT  2.16 22.005 84.24 22.275 ;
     RECT  2.16 22.545 84.24 22.815 ;
     RECT  2.16 23.085 84.24 23.355 ;
     RECT  2.16 23.625 84.24 23.895 ;
     RECT  2.16 24.165 84.24 24.435 ;
     RECT  2.16 24.705 84.24 24.975 ;
     RECT  2.16 25.245 84.24 25.515 ;
     RECT  2.16 25.785 84.24 26.055 ;
     RECT  2.16 26.325 84.24 26.595 ;
     RECT  2.16 26.865 84.24 27.135 ;
     RECT  2.16 27.405 84.24 27.675 ;
     RECT  2.16 27.945 84.24 28.215 ;
     RECT  2.16 28.485 84.24 28.755 ;
     RECT  2.16 29.025 84.24 29.295 ;
     RECT  2.16 29.565 84.24 29.835 ;
     RECT  2.16 30.105 84.24 30.375 ;
     RECT  2.16 30.645 84.24 30.915 ;
     RECT  2.16 31.185 84.24 31.455 ;
     RECT  2.16 31.725 84.24 31.995 ;
     RECT  2.16 32.265 84.24 32.535 ;
     RECT  2.16 32.805 84.24 33.075 ;
     RECT  2.16 33.345 84.24 33.615 ;
     RECT  2.16 33.885 84.24 34.155 ;
     RECT  2.16 34.425 84.24 34.695 ;
     RECT  2.16 34.965 84.24 35.235 ;
     RECT  2.16 35.505 84.24 35.775 ;
     RECT  2.16 36.045 84.24 36.315 ;
     RECT  2.16 36.585 84.24 36.855 ;
     RECT  2.16 37.125 84.24 37.395 ;
     RECT  2.16 37.665 84.24 37.935 ;
     RECT  2.16 38.205 84.24 38.475 ;
     RECT  2.16 38.745 84.24 39.015 ;
     RECT  2.16 39.285 84.24 39.555 ;
     RECT  2.16 39.825 84.24 40.095 ;
     RECT  2.16 40.365 84.24 40.635 ;
     RECT  2.16 40.905 84.24 41.175 ;
     RECT  2.16 41.445 84.24 41.715 ;
     RECT  2.16 41.985 84.24 42.255 ;
     RECT  2.16 42.525 84.24 42.795 ;
     RECT  2.16 43.065 84.24 43.335 ;
     RECT  2.16 43.605 84.24 43.875 ;
     RECT  2.16 44.145 84.24 44.415 ;
     RECT  2.16 44.685 84.24 44.955 ;
     RECT  2.16 45.225 84.24 45.495 ;
     RECT  2.16 45.765 84.24 46.035 ;
     RECT  2.16 46.305 84.24 46.575 ;
     RECT  2.16 46.845 84.24 47.115 ;
     RECT  2.16 47.385 84.24 47.655 ;
     RECT  2.16 47.925 84.24 48.195 ;
     RECT  2.16 48.465 84.24 48.735 ;
     RECT  2.16 49.005 84.24 49.275 ;
     RECT  2.16 49.545 84.24 49.815 ;
     RECT  2.16 50.085 84.24 50.355 ;
     RECT  2.16 50.625 84.24 50.895 ;
     RECT  2.16 51.165 84.24 51.435 ;
     RECT  2.16 51.705 84.24 51.975 ;
     RECT  2.16 52.245 84.24 52.515 ;
     RECT  2.16 52.785 84.24 53.055 ;
     RECT  2.16 53.325 84.24 53.595 ;
     RECT  2.16 53.865 84.24 54.135 ;
     RECT  2.16 54.405 84.24 54.675 ;
     RECT  2.16 54.945 84.24 55.215 ;
     RECT  2.16 55.485 84.24 55.755 ;
     RECT  2.16 56.025 84.24 56.295 ;
     RECT  2.16 56.565 84.24 56.835 ;
     RECT  2.16 57.105 84.24 57.375 ;
     RECT  2.16 57.645 84.24 57.915 ;
     RECT  2.16 58.185 84.24 58.455 ;
     RECT  2.16 58.725 84.24 58.995 ;
     RECT  2.16 59.265 84.24 59.535 ;
     RECT  2.16 59.805 84.24 60.075 ;
     RECT  2.16 60.345 84.24 60.615 ;
     RECT  2.16 60.885 84.24 61.155 ;
     RECT  2.16 61.425 84.24 61.695 ;
     RECT  2.16 61.965 84.24 62.235 ;
     RECT  2.16 62.505 84.24 62.775 ;
     RECT  2.16 63.045 84.24 63.315 ;
     RECT  2.16 63.585 84.24 63.855 ;
     RECT  2.16 64.125 84.24 64.395 ;
     RECT  2.16 64.665 84.24 64.935 ;
     RECT  2.16 65.205 84.24 65.475 ;
     RECT  2.16 65.745 84.24 66.015 ;
     RECT  2.16 66.285 84.24 66.555 ;
     RECT  2.16 66.825 84.24 67.095 ;
     RECT  2.16 67.365 84.24 67.635 ;
     RECT  2.16 67.905 84.24 68.175 ;
     RECT  2.16 68.445 84.24 68.715 ;
     RECT  2.16 68.985 84.24 69.255 ;
     RECT  2.16 69.525 84.24 69.795 ;
     RECT  2.16 70.065 84.24 70.335 ;
     RECT  2.16 70.605 84.24 70.875 ;
     RECT  2.16 71.145 84.24 71.415 ;
     RECT  2.16 71.685 84.24 71.955 ;
     RECT  2.16 72.225 84.24 72.495 ;
     RECT  2.16 72.765 84.24 73.035 ;
     RECT  2.16 73.305 84.24 73.575 ;
     RECT  2.16 73.845 84.24 74.115 ;
     RECT  2.16 74.385 84.24 74.655 ;
     RECT  2.16 74.925 84.24 75.195 ;
     RECT  2.16 75.465 84.24 75.6 ;
    LAYER RVTP ;
     RECT  2.16 2.295 84.24 2.565 ;
     RECT  2.16 2.835 84.24 3.105 ;
     RECT  2.16 3.375 84.24 3.645 ;
     RECT  2.16 3.915 84.24 4.185 ;
     RECT  2.16 4.455 84.24 4.725 ;
     RECT  2.16 4.995 84.24 5.265 ;
     RECT  2.16 5.535 84.24 5.805 ;
     RECT  2.16 6.075 84.24 6.345 ;
     RECT  2.16 6.615 84.24 6.885 ;
     RECT  2.16 7.155 84.24 7.425 ;
     RECT  2.16 7.695 84.24 7.965 ;
     RECT  2.16 8.235 84.24 8.505 ;
     RECT  2.16 8.775 84.24 9.045 ;
     RECT  2.16 9.315 84.24 9.585 ;
     RECT  2.16 9.855 84.24 10.125 ;
     RECT  2.16 10.395 84.24 10.665 ;
     RECT  2.16 10.935 84.24 11.205 ;
     RECT  2.16 11.475 84.24 11.745 ;
     RECT  2.16 12.015 84.24 12.285 ;
     RECT  2.16 12.555 84.24 12.825 ;
     RECT  2.16 13.095 84.24 13.365 ;
     RECT  2.16 13.635 84.24 13.905 ;
     RECT  2.16 14.175 84.24 14.445 ;
     RECT  2.16 14.715 84.24 14.985 ;
     RECT  2.16 15.255 84.24 15.525 ;
     RECT  2.16 15.795 84.24 16.065 ;
     RECT  2.16 16.335 84.24 16.605 ;
     RECT  2.16 16.875 84.24 17.145 ;
     RECT  2.16 17.415 84.24 17.685 ;
     RECT  2.16 17.955 84.24 18.225 ;
     RECT  2.16 18.495 84.24 18.765 ;
     RECT  2.16 19.035 84.24 19.305 ;
     RECT  2.16 19.575 84.24 19.845 ;
     RECT  2.16 20.115 84.24 20.385 ;
     RECT  2.16 20.655 84.24 20.925 ;
     RECT  2.16 21.195 84.24 21.465 ;
     RECT  2.16 21.735 84.24 22.005 ;
     RECT  2.16 22.275 84.24 22.545 ;
     RECT  2.16 22.815 84.24 23.085 ;
     RECT  2.16 23.355 84.24 23.625 ;
     RECT  2.16 23.895 84.24 24.165 ;
     RECT  2.16 24.435 84.24 24.705 ;
     RECT  2.16 24.975 84.24 25.245 ;
     RECT  2.16 25.515 84.24 25.785 ;
     RECT  2.16 26.055 84.24 26.325 ;
     RECT  2.16 26.595 84.24 26.865 ;
     RECT  2.16 27.135 84.24 27.405 ;
     RECT  2.16 27.675 84.24 27.945 ;
     RECT  2.16 28.215 84.24 28.485 ;
     RECT  2.16 28.755 84.24 29.025 ;
     RECT  2.16 29.295 84.24 29.565 ;
     RECT  2.16 29.835 84.24 30.105 ;
     RECT  2.16 30.375 84.24 30.645 ;
     RECT  2.16 30.915 84.24 31.185 ;
     RECT  2.16 31.455 84.24 31.725 ;
     RECT  2.16 31.995 84.24 32.265 ;
     RECT  2.16 32.535 84.24 32.805 ;
     RECT  2.16 33.075 84.24 33.345 ;
     RECT  2.16 33.615 84.24 33.885 ;
     RECT  2.16 34.155 84.24 34.425 ;
     RECT  2.16 34.695 84.24 34.965 ;
     RECT  2.16 35.235 84.24 35.505 ;
     RECT  2.16 35.775 84.24 36.045 ;
     RECT  2.16 36.315 84.24 36.585 ;
     RECT  2.16 36.855 84.24 37.125 ;
     RECT  2.16 37.395 84.24 37.665 ;
     RECT  2.16 37.935 84.24 38.205 ;
     RECT  2.16 38.475 84.24 38.745 ;
     RECT  2.16 39.015 84.24 39.285 ;
     RECT  2.16 39.555 84.24 39.825 ;
     RECT  2.16 40.095 84.24 40.365 ;
     RECT  2.16 40.635 84.24 40.905 ;
     RECT  2.16 41.175 84.24 41.445 ;
     RECT  2.16 41.715 84.24 41.985 ;
     RECT  2.16 42.255 84.24 42.525 ;
     RECT  2.16 42.795 84.24 43.065 ;
     RECT  2.16 43.335 84.24 43.605 ;
     RECT  2.16 43.875 84.24 44.145 ;
     RECT  2.16 44.415 84.24 44.685 ;
     RECT  2.16 44.955 84.24 45.225 ;
     RECT  2.16 45.495 84.24 45.765 ;
     RECT  2.16 46.035 84.24 46.305 ;
     RECT  2.16 46.575 84.24 46.845 ;
     RECT  2.16 47.115 84.24 47.385 ;
     RECT  2.16 47.655 84.24 47.925 ;
     RECT  2.16 48.195 84.24 48.465 ;
     RECT  2.16 48.735 84.24 49.005 ;
     RECT  2.16 49.275 84.24 49.545 ;
     RECT  2.16 49.815 84.24 50.085 ;
     RECT  2.16 50.355 84.24 50.625 ;
     RECT  2.16 50.895 84.24 51.165 ;
     RECT  2.16 51.435 84.24 51.705 ;
     RECT  2.16 51.975 84.24 52.245 ;
     RECT  2.16 52.515 84.24 52.785 ;
     RECT  2.16 53.055 84.24 53.325 ;
     RECT  2.16 53.595 84.24 53.865 ;
     RECT  2.16 54.135 84.24 54.405 ;
     RECT  2.16 54.675 84.24 54.945 ;
     RECT  2.16 55.215 84.24 55.485 ;
     RECT  2.16 55.755 84.24 56.025 ;
     RECT  2.16 56.295 84.24 56.565 ;
     RECT  2.16 56.835 84.24 57.105 ;
     RECT  2.16 57.375 84.24 57.645 ;
     RECT  2.16 57.915 84.24 58.185 ;
     RECT  2.16 58.455 84.24 58.725 ;
     RECT  2.16 58.995 84.24 59.265 ;
     RECT  2.16 59.535 84.24 59.805 ;
     RECT  2.16 60.075 84.24 60.345 ;
     RECT  2.16 60.615 84.24 60.885 ;
     RECT  2.16 61.155 84.24 61.425 ;
     RECT  2.16 61.695 84.24 61.965 ;
     RECT  2.16 62.235 84.24 62.505 ;
     RECT  2.16 62.775 84.24 63.045 ;
     RECT  2.16 63.315 84.24 63.585 ;
     RECT  2.16 63.855 84.24 64.125 ;
     RECT  2.16 64.395 84.24 64.665 ;
     RECT  2.16 64.935 84.24 65.205 ;
     RECT  2.16 65.475 84.24 65.745 ;
     RECT  2.16 66.015 84.24 66.285 ;
     RECT  2.16 66.555 84.24 66.825 ;
     RECT  2.16 67.095 84.24 67.365 ;
     RECT  2.16 67.635 84.24 67.905 ;
     RECT  2.16 68.175 84.24 68.445 ;
     RECT  2.16 68.715 84.24 68.985 ;
     RECT  2.16 69.255 84.24 69.525 ;
     RECT  2.16 69.795 84.24 70.065 ;
     RECT  2.16 70.335 84.24 70.605 ;
     RECT  2.16 70.875 84.24 71.145 ;
     RECT  2.16 71.415 84.24 71.685 ;
     RECT  2.16 71.955 84.24 72.225 ;
     RECT  2.16 72.495 84.24 72.765 ;
     RECT  2.16 73.035 84.24 73.305 ;
     RECT  2.16 73.575 84.24 73.845 ;
     RECT  2.16 74.115 84.24 74.385 ;
     RECT  2.16 74.655 84.24 74.925 ;
     RECT  2.16 75.195 84.24 75.465 ;
    LAYER M1 ;
     RECT  2.16 2.151 84.24 75.609 ;
    LAYER M2 ;
     RECT  2.16 2.151 31.891 75.609 ;
     RECT  31.891 2.106 32.963 75.609 ;
     RECT  32.963 2.151 50.431 75.609 ;
     RECT  50.431 2.151 51.899 75.798 ;
     RECT  51.899 2.151 52.475 75.654 ;
     RECT  52.475 2.151 84.24 75.609 ;
     RECT  84.24 39.528 85.487 39.546 ;
    LAYER M3 ;
     RECT  29.196 0.091 29.934 0.139 ;
     RECT  31.572 0.091 31.59 0.139 ;
     RECT  29.196 0.139 30.078 0.187 ;
     RECT  29.196 0.187 30.15 0.269 ;
     RECT  30.06 0.269 30.15 0.365 ;
     RECT  30.132 0.365 30.15 0.461 ;
     RECT  28.008 0.571 28.026 1.147 ;
     RECT  28.008 1.147 28.242 1.675 ;
     RECT  27.936 1.675 28.242 1.723 ;
     RECT  29.196 0.269 29.214 1.723 ;
     RECT  30.78 0.523 30.798 1.723 ;
     RECT  31.572 0.139 31.77 1.723 ;
     RECT  27.936 1.723 34.038 1.771 ;
     RECT  27.936 1.771 34.542 1.819 ;
     RECT  27.936 1.819 34.722 2.143 ;
     RECT  35.496 1.723 35.514 2.143 ;
     RECT  43.308 1.723 43.326 2.143 ;
     RECT  36.504 2.191 36.522 2.227 ;
     RECT  27.936 2.143 35.514 2.299 ;
     RECT  27.936 2.299 35.622 2.335 ;
     RECT  26.715 2.143 26.805 2.371 ;
     RECT  27.936 2.335 35.73 2.371 ;
     RECT  44.316 2.191 44.334 2.371 ;
     RECT  2.415 2.143 2.505 2.413 ;
     RECT  5.115 2.143 5.205 2.413 ;
     RECT  7.815 2.143 7.905 2.413 ;
     RECT  10.515 2.143 10.605 2.413 ;
     RECT  13.215 2.143 13.305 2.413 ;
     RECT  15.915 2.143 16.005 2.413 ;
     RECT  18.615 2.143 18.705 2.413 ;
     RECT  21.315 2.143 21.405 2.413 ;
     RECT  24.015 2.143 24.105 2.413 ;
     RECT  37.515 2.143 37.605 2.413 ;
     RECT  40.215 2.143 40.305 2.413 ;
     RECT  45.615 2.143 45.705 2.413 ;
     RECT  48.315 2.143 48.405 2.413 ;
     RECT  51.015 2.143 51.105 2.413 ;
     RECT  53.715 2.143 53.805 2.413 ;
     RECT  56.415 2.143 56.505 2.413 ;
     RECT  59.115 2.143 59.205 2.413 ;
     RECT  61.815 2.143 61.905 2.413 ;
     RECT  64.515 2.143 64.605 2.413 ;
     RECT  67.215 2.143 67.305 2.413 ;
     RECT  69.915 2.143 70.005 2.413 ;
     RECT  72.615 2.143 72.705 2.413 ;
     RECT  75.315 2.143 75.405 2.413 ;
     RECT  78.015 2.143 78.105 2.413 ;
     RECT  80.715 2.143 80.805 2.413 ;
     RECT  83.415 2.143 83.505 2.413 ;
     RECT  26.715 2.371 35.73 2.461 ;
     RECT  36.504 2.227 36.594 2.461 ;
     RECT  42.915 2.143 43.326 2.489 ;
     RECT  44.172 2.371 44.334 2.489 ;
     RECT  42.915 2.489 43.254 2.525 ;
     RECT  26.715 2.461 36.594 2.731 ;
     RECT  26.715 2.731 36.63 2.803 ;
     RECT  37.515 2.413 37.797 2.803 ;
     RECT  44.424 2.641 44.442 3.415 ;
     RECT  24.015 2.413 24.297 3.649 ;
     RECT  42.915 2.525 43.197 3.721 ;
     RECT  44.424 3.415 44.514 3.721 ;
     RECT  42.915 3.721 44.514 3.839 ;
     RECT  42.915 3.839 44.082 3.991 ;
     RECT  42.84 3.991 44.082 4.109 ;
     RECT  26.715 2.803 37.797 4.261 ;
     RECT  26.715 4.261 37.926 4.289 ;
     RECT  27.72 4.289 37.926 4.415 ;
     RECT  27.828 4.415 37.926 4.829 ;
     RECT  27.864 4.829 37.926 5.333 ;
     RECT  28.008 5.333 37.926 5.459 ;
     RECT  28.044 5.459 37.926 6.511 ;
     RECT  27.972 6.511 37.926 6.655 ;
     RECT  26.715 4.289 26.997 6.961 ;
     RECT  27.72 6.655 37.926 6.961 ;
     RECT  26.715 6.961 37.926 7.735 ;
     RECT  24.015 3.649 24.894 8.275 ;
     RECT  26.28 7.735 37.926 9.931 ;
     RECT  23.4 8.275 24.894 10.411 ;
     RECT  23.4 10.411 25.074 10.471 ;
     RECT  26.028 9.931 37.926 10.741 ;
     RECT  23.4 10.471 25.218 10.939 ;
     RECT  25.992 10.741 37.926 10.939 ;
     RECT  23.4 10.939 37.926 11.003 ;
     RECT  23.4 11.003 24.894 11.101 ;
     RECT  22.932 11.101 24.894 14.521 ;
     RECT  25.992 11.003 37.926 14.521 ;
     RECT  38.664 17.323 38.79 17.453 ;
     RECT  22.932 14.521 37.926 19.111 ;
     RECT  40.215 2.413 40.497 21.355 ;
     RECT  40.215 21.355 41.022 21.395 ;
     RECT  39.348 18.193 39.366 21.451 ;
     RECT  39.348 21.451 39.474 21.569 ;
     RECT  53.715 2.413 53.997 21.739 ;
     RECT  48.315 2.413 48.597 21.811 ;
     RECT  49.68 21.739 49.698 21.811 ;
     RECT  51.015 2.413 51.297 21.901 ;
     RECT  51.015 21.901 51.39 21.937 ;
     RECT  59.115 2.413 59.397 21.937 ;
     RECT  48.06 21.811 49.698 21.973 ;
     RECT  51.015 21.937 51.678 21.973 ;
     RECT  58.752 21.937 59.958 22.009 ;
     RECT  39.348 21.569 39.366 22.045 ;
     RECT  47.916 21.973 51.678 22.045 ;
     RECT  47.916 22.045 51.75 22.081 ;
     RECT  56.415 2.413 56.697 22.081 ;
     RECT  57.708 22.009 59.958 22.081 ;
     RECT  61.815 2.413 62.097 22.081 ;
     RECT  57.708 22.081 62.946 22.171 ;
     RECT  57.708 22.171 63.018 22.235 ;
     RECT  56.415 22.081 56.862 22.243 ;
     RECT  47.916 22.081 51.894 22.279 ;
     RECT  47.268 22.279 51.894 22.315 ;
     RECT  52.992 21.739 53.997 22.315 ;
     RECT  55.548 22.279 55.566 22.315 ;
     RECT  54.72 22.315 54.738 22.351 ;
     RECT  55.548 22.315 55.638 22.351 ;
     RECT  56.376 22.243 56.862 22.351 ;
     RECT  57.708 22.235 59.634 22.351 ;
     RECT  60.48 22.235 63.018 22.351 ;
     RECT  47.268 22.315 53.997 22.441 ;
     RECT  54.72 22.351 55.638 22.441 ;
     RECT  47.268 22.441 55.638 22.477 ;
     RECT  56.376 22.351 59.634 22.477 ;
     RECT  47.268 22.477 59.634 22.513 ;
     RECT  45.615 2.413 45.897 22.549 ;
     RECT  46.764 22.513 59.634 22.549 ;
     RECT  60.48 22.351 63.198 22.585 ;
     RECT  64.515 2.413 64.797 22.585 ;
     RECT  41.868 22.747 41.886 22.811 ;
     RECT  65.808 22.783 65.826 22.819 ;
     RECT  65.808 22.819 66.042 22.847 ;
     RECT  42.84 4.109 43.866 22.855 ;
     RECT  42.732 22.855 43.866 22.891 ;
     RECT  42.048 22.891 43.866 23.009 ;
     RECT  45.615 22.549 59.634 23.017 ;
     RECT  60.48 22.585 64.797 23.017 ;
     RECT  42.84 23.009 43.866 23.557 ;
     RECT  42.84 23.557 43.902 23.593 ;
     RECT  44.64 23.557 44.658 23.593 ;
     RECT  22.932 19.111 38.142 23.665 ;
     RECT  45.615 23.017 64.797 23.791 ;
     RECT  66.024 22.847 66.042 23.791 ;
     RECT  45.615 23.791 64.962 23.827 ;
     RECT  42.84 23.593 44.658 23.855 ;
     RECT  42.048 23.009 42.066 23.899 ;
     RECT  42.84 23.855 44.046 23.899 ;
     RECT  45.615 23.827 65.07 23.899 ;
     RECT  65.88 23.791 66.042 23.899 ;
     RECT  45.615 23.899 66.042 24.089 ;
     RECT  45.615 24.089 56.697 24.439 ;
     RECT  57.456 24.089 66.042 24.511 ;
     RECT  67.215 2.413 67.497 24.601 ;
     RECT  67.215 24.601 67.626 24.745 ;
     RECT  67.176 24.745 67.626 24.943 ;
     RECT  45.288 24.439 56.697 24.979 ;
     RECT  57.456 24.511 66.186 24.979 ;
     RECT  22.932 23.665 38.358 25.045 ;
     RECT  39.312 22.045 39.366 25.045 ;
     RECT  42.048 23.899 44.046 25.051 ;
     RECT  67.176 24.943 67.77 25.051 ;
     RECT  42.048 25.051 44.154 25.141 ;
     RECT  67.176 25.051 68.022 25.141 ;
     RECT  67.176 25.141 68.13 25.177 ;
     RECT  41.436 25.141 44.154 25.213 ;
     RECT  45.288 24.979 66.186 25.249 ;
     RECT  66.996 25.177 68.13 25.249 ;
     RECT  22.932 25.045 39.366 25.277 ;
     RECT  41.436 25.213 44.226 25.321 ;
     RECT  45.288 25.249 68.13 25.321 ;
     RECT  41.436 25.321 68.13 25.411 ;
     RECT  41.436 25.411 68.418 25.511 ;
     RECT  45.288 25.511 68.418 25.519 ;
     RECT  45.288 25.519 68.85 25.547 ;
     RECT  64.224 25.547 68.85 25.951 ;
     RECT  41.436 25.511 44.37 26.015 ;
     RECT  64.224 25.951 69.066 26.015 ;
     RECT  64.332 26.015 69.066 26.095 ;
     RECT  64.332 26.095 69.138 26.401 ;
     RECT  45.288 25.547 63.27 26.539 ;
     RECT  64.332 26.401 69.174 26.599 ;
     RECT  69.915 2.413 70.197 26.599 ;
     RECT  22.932 25.277 38.358 26.671 ;
     RECT  64.332 26.599 70.197 26.761 ;
     RECT  39.312 25.277 39.366 26.797 ;
     RECT  45.288 26.539 63.558 26.941 ;
     RECT  64.332 26.761 70.254 26.941 ;
     RECT  41.436 26.015 44.226 27.211 ;
     RECT  45.036 26.941 70.29 27.211 ;
     RECT  41.436 27.211 70.29 27.329 ;
     RECT  41.436 27.329 44.514 27.337 ;
     RECT  40.215 21.395 40.497 27.355 ;
     RECT  41.4 27.337 44.514 27.355 ;
     RECT  40.215 27.355 44.514 27.365 ;
     RECT  22.932 26.671 38.502 27.751 ;
     RECT  39.312 26.797 39.438 27.751 ;
     RECT  22.932 27.751 39.438 28.123 ;
     RECT  40.215 27.365 44.406 28.123 ;
     RECT  22.932 28.123 44.406 28.219 ;
     RECT  45.288 27.329 70.29 28.219 ;
     RECT  22.932 28.219 70.29 28.445 ;
     RECT  60.444 28.445 70.29 29.101 ;
     RECT  22.932 28.445 59.397 29.263 ;
     RECT  60.444 29.101 70.506 29.299 ;
     RECT  60.444 29.299 70.722 29.335 ;
     RECT  22.932 29.263 59.706 29.371 ;
     RECT  60.444 29.335 71.154 29.371 ;
     RECT  22.932 29.371 71.514 30.451 ;
     RECT  22.932 30.451 71.694 30.613 ;
     RECT  22.932 30.613 71.802 30.919 ;
     RECT  72.615 2.413 72.897 30.919 ;
     RECT  22.932 30.919 72.897 31.145 ;
     RECT  22.932 31.145 63.486 31.415 ;
     RECT  64.26 31.145 72.897 31.423 ;
     RECT  74.124 31.261 74.142 31.423 ;
     RECT  75.315 2.413 75.597 31.423 ;
     RECT  64.26 31.423 73.206 31.531 ;
     RECT  74.124 31.423 75.597 31.531 ;
     RECT  22.932 31.415 56.79 31.649 ;
     RECT  64.26 31.531 75.726 31.729 ;
     RECT  22.932 31.649 27.198 31.757 ;
     RECT  64.26 31.729 75.798 31.801 ;
     RECT  57.564 31.415 63.486 31.927 ;
     RECT  64.26 31.801 76.122 31.927 ;
     RECT  57.564 31.927 76.122 32.161 ;
     RECT  27.972 31.649 56.79 32.225 ;
     RECT  57.564 32.161 76.482 32.269 ;
     RECT  57.564 32.269 76.662 33.115 ;
     RECT  57.564 33.115 76.842 33.277 ;
     RECT  27.972 32.225 56.697 33.313 ;
     RECT  57.456 33.277 76.842 33.313 ;
     RECT  27.972 33.313 76.842 33.421 ;
     RECT  27.972 33.421 76.878 33.449 ;
     RECT  64.26 33.449 76.878 33.691 ;
     RECT  64.26 33.691 76.95 33.817 ;
     RECT  78.015 2.413 78.297 33.817 ;
     RECT  27.972 33.449 63.486 34.357 ;
     RECT  64.26 33.817 78.297 34.357 ;
     RECT  27.972 34.357 78.297 34.655 ;
     RECT  27.972 34.655 63.198 34.961 ;
     RECT  27.972 34.961 59.397 35.339 ;
     RECT  64.404 34.655 78.297 35.735 ;
     RECT  64.404 35.735 77.166 35.941 ;
     RECT  58.068 35.339 59.397 35.977 ;
     RECT  58.068 35.977 59.454 36.013 ;
     RECT  60.264 34.961 63.198 36.013 ;
     RECT  64.368 35.941 77.166 36.013 ;
     RECT  58.068 36.013 63.198 36.085 ;
     RECT  27.972 35.339 57.186 36.113 ;
     RECT  52.092 36.113 57.186 36.121 ;
     RECT  58.068 36.085 63.558 36.121 ;
     RECT  64.332 36.013 77.166 36.269 ;
     RECT  64.368 36.269 77.166 36.275 ;
     RECT  52.092 36.121 63.558 36.383 ;
     RECT  27.972 36.113 51.297 36.419 ;
     RECT  64.404 36.275 77.166 36.475 ;
     RECT  78.015 35.735 78.297 36.475 ;
     RECT  64.404 36.475 78.297 36.887 ;
     RECT  55.26 36.383 63.558 37.003 ;
     RECT  64.404 36.887 76.878 37.003 ;
     RECT  46.8 36.419 51.297 37.093 ;
     RECT  52.092 36.383 54.378 37.093 ;
     RECT  46.8 37.093 54.378 37.165 ;
     RECT  55.26 37.003 76.878 37.165 ;
     RECT  27.972 36.419 46.062 37.201 ;
     RECT  46.8 37.165 76.878 37.201 ;
     RECT  27.972 37.201 76.878 37.997 ;
     RECT  78.015 36.887 78.297 38.443 ;
     RECT  86.292 38.347 86.31 38.477 ;
     RECT  64.188 37.997 76.878 38.507 ;
     RECT  77.724 38.443 78.297 38.551 ;
     RECT  75.132 38.507 76.878 38.677 ;
     RECT  77.724 38.551 78.642 38.677 ;
     RECT  75.132 38.677 78.642 38.741 ;
     RECT  75.168 38.741 78.297 38.975 ;
     RECT  79.956 38.713 79.974 39.181 ;
     RECT  80.715 2.413 80.997 39.181 ;
     RECT  75.204 38.975 78.297 39.209 ;
     RECT  79.956 39.181 80.997 39.209 ;
     RECT  83.415 2.413 83.697 39.253 ;
     RECT  27.972 37.997 63.162 39.281 ;
     RECT  80.028 39.209 80.997 39.317 ;
     RECT  83.415 39.253 84.042 39.479 ;
     RECT  85.464 39.355 85.482 39.551 ;
     RECT  64.368 38.507 74.214 39.595 ;
     RECT  64.368 39.595 74.466 39.631 ;
     RECT  63.864 39.631 74.466 39.721 ;
     RECT  75.204 39.209 76.698 39.721 ;
     RECT  27.972 39.281 63.126 40.135 ;
     RECT  63.864 39.721 76.698 40.135 ;
     RECT  27.972 40.135 76.698 40.441 ;
     RECT  27.972 40.441 76.986 40.595 ;
     RECT  27.972 40.595 75.834 41.099 ;
     RECT  76.644 40.595 76.986 41.207 ;
     RECT  27.972 41.099 74.25 41.243 ;
     RECT  75.024 41.099 75.834 41.243 ;
     RECT  75.276 41.243 75.834 41.405 ;
     RECT  75.315 41.405 75.834 42.871 ;
     RECT  76.68 41.207 76.986 42.871 ;
     RECT  75.315 42.871 76.986 43.339 ;
     RECT  75.204 43.339 76.986 43.403 ;
     RECT  75.315 43.403 76.986 43.529 ;
     RECT  27.972 41.243 74.178 43.637 ;
     RECT  27.972 43.637 73.962 44.419 ;
     RECT  27.972 44.419 74.214 45.023 ;
     RECT  68.256 45.023 74.214 45.031 ;
     RECT  75.315 43.529 75.798 45.031 ;
     RECT  68.256 45.031 75.798 45.185 ;
     RECT  68.364 45.185 75.798 45.265 ;
     RECT  76.68 43.529 76.986 45.265 ;
     RECT  68.364 45.265 76.986 45.419 ;
     RECT  75.204 45.419 76.986 45.499 ;
     RECT  73.62 45.419 74.43 45.527 ;
     RECT  75.204 45.499 77.058 45.563 ;
     RECT  73.62 45.527 73.638 45.581 ;
     RECT  74.412 45.527 74.43 45.689 ;
     RECT  75.315 45.563 77.058 45.689 ;
     RECT  76.5 45.689 77.058 45.697 ;
     RECT  76.5 45.697 77.274 45.731 ;
     RECT  27.972 45.023 67.497 45.841 ;
     RECT  76.968 45.731 77.274 45.841 ;
     RECT  78.015 39.209 78.297 45.841 ;
     RECT  76.968 45.841 78.297 45.869 ;
     RECT  77.256 45.869 78.297 45.959 ;
     RECT  77.256 45.959 77.274 45.995 ;
     RECT  22.932 31.757 26.997 46.003 ;
     RECT  27.972 45.841 67.59 46.003 ;
     RECT  22.932 46.003 67.59 46.027 ;
     RECT  68.364 45.419 72.897 46.027 ;
     RECT  22.932 46.027 72.897 46.643 ;
     RECT  22.932 46.643 71.802 47.381 ;
     RECT  22.932 47.381 71.55 47.453 ;
     RECT  22.932 47.453 71.442 47.489 ;
     RECT  22.932 47.489 70.722 48.155 ;
     RECT  22.932 48.155 54.558 48.901 ;
     RECT  55.332 48.155 70.722 48.901 ;
     RECT  22.932 48.901 70.722 52.169 ;
     RECT  22.932 52.169 23.274 52.349 ;
     RECT  22.932 52.349 22.95 52.411 ;
     RECT  24.015 52.169 70.722 52.619 ;
     RECT  24.015 52.619 70.29 53.095 ;
     RECT  22.32 52.411 22.95 53.671 ;
     RECT  21.315 2.413 21.597 53.755 ;
     RECT  22.32 53.671 23.022 53.755 ;
     RECT  21.315 53.755 23.166 53.761 ;
     RECT  23.94 53.095 70.29 53.761 ;
     RECT  21.315 53.761 70.29 54.103 ;
     RECT  21.06 54.103 70.29 54.445 ;
     RECT  20.556 54.445 70.29 54.571 ;
     RECT  18.615 2.413 18.897 54.985 ;
     RECT  18.615 54.985 19.062 55.021 ;
     RECT  19.944 54.571 70.29 55.021 ;
     RECT  18.615 55.021 70.29 55.139 ;
     RECT  19.944 55.139 70.29 55.417 ;
     RECT  19.944 55.417 70.362 55.679 ;
     RECT  18.615 55.139 19.206 55.957 ;
     RECT  19.944 55.679 70.29 55.957 ;
     RECT  18.615 55.957 70.29 56.101 ;
     RECT  17.712 56.911 17.73 56.957 ;
     RECT  18.54 56.101 70.29 57.541 ;
     RECT  18.54 57.541 70.686 57.721 ;
     RECT  18.468 57.721 70.686 57.955 ;
     RECT  17.856 57.955 70.686 57.983 ;
     RECT  17.856 57.983 70.197 58.013 ;
     RECT  18 58.013 70.197 58.109 ;
     RECT  18 58.109 38.898 58.157 ;
     RECT  18 58.157 38.682 58.999 ;
     RECT  39.636 58.109 70.197 58.999 ;
     RECT  18 58.999 70.197 59.189 ;
     RECT  67.032 59.189 70.197 59.341 ;
     RECT  67.032 59.341 70.47 59.459 ;
     RECT  67.032 59.459 70.398 59.495 ;
     RECT  71.244 59.611 71.262 59.801 ;
     RECT  18 59.189 66.15 59.803 ;
     RECT  17.784 59.803 66.15 59.843 ;
     RECT  18.504 59.843 66.15 60.151 ;
     RECT  18.504 60.151 66.258 60.313 ;
     RECT  18.504 60.313 66.294 60.362 ;
     RECT  67.215 59.495 70.398 60.362 ;
     RECT  18.504 60.362 70.398 61.231 ;
     RECT  18.504 61.231 71.046 61.421 ;
     RECT  18.504 61.421 70.326 61.579 ;
     RECT  18.468 61.579 70.326 61.763 ;
     RECT  58.104 61.763 70.326 61.799 ;
     RECT  58.104 61.799 70.29 62.671 ;
     RECT  18.468 61.763 57.33 62.779 ;
     RECT  58.104 62.671 70.506 62.779 ;
     RECT  18.468 62.779 70.506 63.049 ;
     RECT  18.468 63.049 70.65 63.113 ;
     RECT  18.615 63.113 70.65 63.239 ;
     RECT  18.615 63.239 70.506 63.581 ;
     RECT  18.615 63.581 70.197 63.815 ;
     RECT  19.836 63.815 70.197 64.193 ;
     RECT  19.944 64.193 70.197 64.363 ;
     RECT  19.944 64.363 70.326 64.499 ;
     RECT  20.016 64.499 70.326 64.589 ;
     RECT  20.088 64.589 68.094 64.625 ;
     RECT  20.088 64.625 20.286 64.661 ;
     RECT  21.06 64.625 68.094 65.693 ;
     RECT  20.16 64.661 20.286 65.821 ;
     RECT  21.096 65.693 68.094 66.125 ;
     RECT  20.16 65.821 20.358 66.361 ;
     RECT  19.908 66.361 20.358 66.595 ;
     RECT  21.096 66.125 65.106 66.595 ;
     RECT  19.908 66.595 65.106 67.019 ;
     RECT  19.908 67.019 19.926 67.055 ;
     RECT  20.664 67.019 65.106 67.243 ;
     RECT  65.88 66.125 68.094 67.243 ;
     RECT  20.664 67.243 68.094 68.059 ;
     RECT  68.832 64.589 70.197 68.059 ;
     RECT  20.664 68.059 70.197 68.135 ;
     RECT  20.952 68.135 70.197 68.909 ;
     RECT  20.952 68.909 65.718 68.945 ;
     RECT  21.315 68.945 65.718 68.957 ;
     RECT  66.456 68.909 70.197 68.957 ;
     RECT  66.456 68.957 67.95 69.287 ;
     RECT  21.315 68.957 65.178 69.521 ;
     RECT  68.688 68.957 70.197 69.521 ;
     RECT  21.315 69.521 65.106 69.899 ;
     RECT  66.492 69.287 67.95 70.261 ;
     RECT  23.22 69.899 65.106 70.411 ;
     RECT  66.348 70.261 67.95 70.411 ;
     RECT  68.868 69.521 70.197 70.411 ;
     RECT  23.22 70.411 65.358 70.529 ;
     RECT  45.468 70.529 65.358 70.681 ;
     RECT  66.348 70.411 70.197 70.681 ;
     RECT  23.364 70.529 44.73 70.799 ;
     RECT  45.468 70.681 70.197 70.799 ;
     RECT  45.468 70.799 68.742 70.835 ;
     RECT  69.516 70.799 70.197 70.943 ;
     RECT  21.315 69.899 22.374 70.951 ;
     RECT  66.096 70.835 68.742 70.979 ;
     RECT  66.276 70.979 68.742 71.069 ;
     RECT  66.708 71.069 67.497 71.141 ;
     RECT  45.468 70.835 65.142 71.213 ;
     RECT  66.78 71.141 67.497 71.213 ;
     RECT  68.256 71.069 68.742 71.213 ;
     RECT  68.616 71.213 68.742 71.339 ;
     RECT  45.468 71.213 64.797 71.375 ;
     RECT  23.4 70.799 44.73 71.383 ;
     RECT  45.468 71.375 63.234 71.383 ;
     RECT  68.724 71.339 68.742 71.483 ;
     RECT  23.4 71.383 63.234 71.609 ;
     RECT  64.188 71.375 64.797 71.645 ;
     RECT  21.315 70.951 22.626 71.761 ;
     RECT  23.4 71.609 43.758 71.761 ;
     RECT  44.496 71.609 63.234 71.879 ;
     RECT  44.496 71.879 62.478 71.915 ;
     RECT  44.496 71.915 62.097 71.987 ;
     RECT  44.496 71.987 60.966 72.149 ;
     RECT  63.216 71.879 63.234 72.185 ;
     RECT  21.315 71.761 43.758 72.329 ;
     RECT  63.324 72.229 63.342 72.329 ;
     RECT  22.356 72.329 43.758 72.391 ;
     RECT  44.496 72.149 60.138 72.391 ;
     RECT  60.948 72.149 60.966 72.455 ;
     RECT  22.356 72.391 60.138 73.229 ;
     RECT  22.68 73.229 60.138 73.277 ;
     RECT  23.292 73.277 60.138 73.535 ;
     RECT  23.328 73.535 60.138 73.769 ;
     RECT  23.364 73.769 60.138 73.885 ;
     RECT  23.364 73.885 60.174 74.075 ;
     RECT  24.015 74.075 60.174 74.155 ;
     RECT  24.015 74.155 60.21 74.345 ;
     RECT  25.344 74.345 60.21 74.395 ;
     RECT  25.344 74.395 60.75 74.417 ;
     RECT  24.015 74.345 24.462 74.453 ;
     RECT  25.344 74.417 40.497 74.615 ;
     RECT  41.4 74.417 60.75 74.759 ;
     RECT  41.4 74.759 49.194 74.885 ;
     RECT  50.256 74.759 60.75 75.091 ;
     RECT  61.815 71.987 62.097 75.091 ;
     RECT  25.956 74.615 40.497 75.119 ;
     RECT  41.4 74.885 48.942 75.119 ;
     RECT  26.715 75.119 40.497 75.227 ;
     RECT  41.4 75.119 45.897 75.245 ;
     RECT  26.715 75.227 39.078 75.263 ;
     RECT  2.415 2.413 2.697 75.347 ;
     RECT  5.115 2.413 5.397 75.347 ;
     RECT  7.815 2.413 8.097 75.347 ;
     RECT  10.515 2.413 10.797 75.347 ;
     RECT  13.215 2.413 13.497 75.347 ;
     RECT  15.915 2.413 16.197 75.347 ;
     RECT  18.615 63.815 18.897 75.347 ;
     RECT  21.315 72.329 21.597 75.347 ;
     RECT  24.015 74.453 24.297 75.347 ;
     RECT  40.215 75.227 40.497 75.347 ;
     RECT  41.544 75.245 45.897 75.347 ;
     RECT  50.256 75.091 62.097 75.347 ;
     RECT  64.515 71.645 64.797 75.347 ;
     RECT  67.215 71.213 67.497 75.347 ;
     RECT  69.915 70.943 70.197 75.347 ;
     RECT  72.615 46.643 72.897 75.347 ;
     RECT  75.315 45.689 75.597 75.347 ;
     RECT  78.015 45.959 78.297 75.347 ;
     RECT  80.715 39.317 80.997 75.347 ;
     RECT  83.415 39.479 83.697 75.347 ;
     RECT  25.956 75.119 25.974 75.389 ;
     RECT  26.715 75.263 37.854 75.389 ;
     RECT  41.544 75.347 45.774 75.389 ;
     RECT  46.764 75.119 46.926 75.389 ;
     RECT  47.7 75.119 48.798 75.389 ;
     RECT  50.256 75.347 61.905 75.389 ;
     RECT  27.576 75.389 30.186 75.425 ;
     RECT  50.256 75.389 61.038 75.425 ;
     RECT  41.544 75.389 43.686 75.437 ;
     RECT  44.748 75.389 44.766 75.437 ;
     RECT  45.54 75.389 45.705 75.437 ;
     RECT  30.96 75.389 35.622 75.461 ;
     RECT  41.544 75.437 43.254 75.461 ;
     RECT  42.408 75.461 43.254 75.533 ;
     RECT  50.436 75.425 61.038 75.533 ;
     RECT  36.9 75.389 37.605 75.569 ;
     RECT  41.544 75.461 41.562 75.569 ;
     RECT  27.612 75.425 30.186 75.581 ;
     RECT  2.415 75.347 2.505 75.617 ;
     RECT  5.115 75.347 5.205 75.617 ;
     RECT  7.815 75.347 7.905 75.617 ;
     RECT  10.515 75.347 10.605 75.617 ;
     RECT  13.215 75.347 13.305 75.617 ;
     RECT  15.915 75.347 16.005 75.617 ;
     RECT  18.615 75.347 18.705 75.617 ;
     RECT  21.315 75.347 21.405 75.617 ;
     RECT  24.015 75.347 24.105 75.617 ;
     RECT  26.715 75.389 26.805 75.617 ;
     RECT  37.515 75.569 37.605 75.617 ;
     RECT  40.215 75.347 40.305 75.617 ;
     RECT  42.915 75.533 43.254 75.617 ;
     RECT  45.615 75.437 45.705 75.617 ;
     RECT  48.315 75.389 48.405 75.617 ;
     RECT  50.436 75.533 58.122 75.617 ;
     RECT  59.115 75.533 61.038 75.617 ;
     RECT  61.815 75.389 61.905 75.617 ;
     RECT  64.515 75.347 64.605 75.617 ;
     RECT  67.215 75.347 67.305 75.617 ;
     RECT  69.915 75.347 70.005 75.617 ;
     RECT  72.615 75.347 72.705 75.617 ;
     RECT  75.315 75.347 75.405 75.617 ;
     RECT  78.015 75.347 78.105 75.617 ;
     RECT  80.715 75.347 80.805 75.617 ;
     RECT  83.415 75.347 83.505 75.617 ;
     RECT  50.436 75.617 56.106 75.659 ;
     RECT  27.612 75.581 29.574 75.725 ;
     RECT  30.96 75.461 35.19 75.725 ;
     RECT  27.612 75.725 29.394 75.773 ;
     RECT  32.472 75.725 32.49 75.773 ;
     RECT  33.228 75.725 34.794 75.773 ;
     RECT  57.06 75.617 58.122 75.773 ;
     RECT  50.436 75.659 50.454 75.803 ;
     RECT  43.236 75.617 43.254 75.821 ;
     RECT  57.528 75.773 58.122 75.821 ;
     RECT  51.588 75.659 56.106 75.869 ;
     RECT  27.612 75.773 29.286 76.397 ;
     RECT  30.96 75.725 31.698 76.397 ;
     RECT  55.26 75.869 56.106 76.397 ;
     RECT  51.588 75.869 54.522 76.493 ;
     RECT  51.588 76.493 51.606 76.925 ;
     RECT  28.08 76.397 29.286 76.973 ;
     RECT  52.74 76.493 54.522 76.973 ;
     RECT  59.76 75.617 61.038 77.453 ;
     RECT  33.228 75.773 34.542 77.501 ;
     RECT  55.26 76.397 55.278 77.515 ;
     RECT  56.088 76.397 56.106 77.515 ;
     RECT  57.528 75.821 57.546 77.563 ;
     RECT  28.332 76.973 29.286 77.645 ;
     RECT  30.96 76.397 30.978 77.645 ;
     RECT  33.228 77.501 34.038 77.645 ;
     RECT  52.74 76.973 52.758 77.645 ;
     RECT  53.856 76.973 54.522 77.645 ;
     RECT  55.26 77.515 56.106 77.645 ;
     RECT  56.952 77.563 57.546 77.645 ;
     RECT  60.084 77.453 61.038 77.645 ;
     RECT  56.952 77.645 57.366 77.693 ;
     RECT  60.084 77.645 60.534 77.693 ;
     RECT  57.348 77.693 57.366 77.741 ;
     RECT  60.516 77.693 60.534 77.741 ;
    LAYER M4 ;
     RECT  2.408 2.148 2.512 75.612 ;
     RECT  2.512 2.418 2.704 75.342 ;
     RECT  5.108 2.148 5.212 75.612 ;
     RECT  5.212 2.418 5.404 75.342 ;
     RECT  7.808 2.148 7.912 75.612 ;
     RECT  7.912 2.418 8.104 75.342 ;
     RECT  10.508 2.148 10.612 75.612 ;
     RECT  10.612 2.418 10.804 75.342 ;
     RECT  13.208 2.148 13.312 75.612 ;
     RECT  13.312 2.418 13.504 75.342 ;
     RECT  15.908 2.148 16.012 75.612 ;
     RECT  16.012 2.418 16.204 75.342 ;
     RECT  17.701 56.928 18.229 56.952 ;
     RECT  17.845 57.984 18.229 58.008 ;
     RECT  18.229 56.592 18.469 58.008 ;
     RECT  18.469 56.592 18.608 58.68 ;
     RECT  17.773 59.808 18.608 59.832 ;
     RECT  18.457 61.584 18.608 61.608 ;
     RECT  18.608 2.148 18.712 75.612 ;
     RECT  18.712 2.418 18.904 75.342 ;
     RECT  18.904 55.152 19.043 56.616 ;
     RECT  19.043 55.152 19.084 55.848 ;
     RECT  18.904 59.808 19.109 59.832 ;
     RECT  18.904 58.416 19.469 58.44 ;
     RECT  19.084 55.152 19.973 55.176 ;
     RECT  18.904 61.728 20.257 61.752 ;
     RECT  20.257 61.728 20.401 62.136 ;
     RECT  20.401 61.488 20.473 62.136 ;
     RECT  20.437 59.184 20.977 59.208 ;
     RECT  20.185 65.664 21.157 65.688 ;
     RECT  20.977 58.704 21.308 59.208 ;
     RECT  20.473 61.44 21.308 62.136 ;
     RECT  18.904 63.216 21.308 63.24 ;
     RECT  20.533 64.368 21.308 64.392 ;
     RECT  21.157 65.664 21.308 66.216 ;
     RECT  20.653 67.68 21.308 67.704 ;
     RECT  21.308 2.148 21.412 75.612 ;
     RECT  21.412 2.418 21.604 75.342 ;
     RECT  21.604 55.056 21.731 55.08 ;
     RECT  21.604 71.232 21.772 72.12 ;
     RECT  21.604 58.704 21.989 59.208 ;
     RECT  21.604 60.432 22.115 62.712 ;
     RECT  21.604 67.68 22.277 68.424 ;
     RECT  21.989 58.704 22.313 59.064 ;
     RECT  21.604 56.352 22.457 56.52 ;
     RECT  22.277 67.68 22.597 67.752 ;
     RECT  21.772 71.232 22.597 71.784 ;
     RECT  22.597 67.248 22.643 67.752 ;
     RECT  22.457 56.496 22.741 56.52 ;
     RECT  21.604 57.648 22.741 57.672 ;
     RECT  21.604 53.76 22.853 54.072 ;
     RECT  22.115 61.44 22.885 62.712 ;
     RECT  22.885 61.44 23.137 63.096 ;
     RECT  21.604 64.368 23.137 64.392 ;
     RECT  22.597 70.8 23.209 71.784 ;
     RECT  23.228 52.32 23.269 52.344 ;
     RECT  22.669 73.248 23.317 73.272 ;
     RECT  22.741 56.496 23.533 57.672 ;
     RECT  23.209 70.32 23.533 71.784 ;
     RECT  23.533 70.32 23.641 72.168 ;
     RECT  22.313 58.992 23.893 59.064 ;
     RECT  23.893 58.992 23.929 59.784 ;
     RECT  23.269 52.32 24.008 52.728 ;
     RECT  22.853 53.76 24.008 53.928 ;
     RECT  23.965 54.96 24.008 54.984 ;
     RECT  23.533 56.064 24.008 57.672 ;
     RECT  23.929 58.944 24.008 59.784 ;
     RECT  23.137 61.056 24.008 64.392 ;
     RECT  21.604 65.664 24.008 65.688 ;
     RECT  22.643 67.248 24.008 67.704 ;
     RECT  23.641 70.224 24.008 72.168 ;
     RECT  23.317 73.248 24.008 73.512 ;
     RECT  24.008 2.148 24.112 75.612 ;
     RECT  24.112 2.418 24.304 75.342 ;
     RECT  24.304 56.4 24.365 57.096 ;
     RECT  24.304 58.944 24.365 63.768 ;
     RECT  24.304 14.4 24.419 14.424 ;
     RECT  24.304 68.352 24.581 72.168 ;
     RECT  24.304 73.488 24.653 73.512 ;
     RECT  24.365 58.992 24.94 63.768 ;
     RECT  24.304 51.84 24.941 53.928 ;
     RECT  24.941 52.464 25.121 53.928 ;
     RECT  24.94 60.864 25.265 63.768 ;
     RECT  24.304 10.416 25.441 10.44 ;
     RECT  24.581 68.688 25.585 72.168 ;
     RECT  25.121 53.904 25.717 53.928 ;
     RECT  25.265 62.4 26.012 63.768 ;
     RECT  25.441 10.416 26.017 10.968 ;
     RECT  25.265 60.864 26.125 61.416 ;
     RECT  25.121 52.464 26.377 52.488 ;
     RECT  25.585 68.688 26.377 72.408 ;
     RECT  26.125 74.304 26.477 74.328 ;
     RECT  26.377 68.16 26.485 72.408 ;
     RECT  26.477 73.584 26.485 74.328 ;
     RECT  24.365 56.4 26.581 56.808 ;
     RECT  26.06 57.984 26.581 58.008 ;
     RECT  24.94 58.992 26.581 59.784 ;
     RECT  26.377 52.464 26.701 52.728 ;
     RECT  25.717 53.904 26.701 54.12 ;
     RECT  26.017 9.936 26.708 10.968 ;
     RECT  26.701 52.464 26.708 54.12 ;
     RECT  24.304 55.296 26.708 55.32 ;
     RECT  26.581 56.304 26.708 56.808 ;
     RECT  26.581 57.984 26.708 59.784 ;
     RECT  26.125 60.816 26.708 61.416 ;
     RECT  26.012 62.4 26.708 64.008 ;
     RECT  26.269 65.136 26.708 65.16 ;
     RECT  26.593 66.768 26.708 66.792 ;
     RECT  26.485 68.16 26.708 74.328 ;
     RECT  26.708 2.148 26.812 75.612 ;
     RECT  26.812 2.418 27.004 75.342 ;
     RECT  27.004 65.136 27.065 75.288 ;
     RECT  27.004 3.312 27.155 4.632 ;
     RECT  27.004 7.008 27.155 7.944 ;
     RECT  27.004 50.736 27.209 54.072 ;
     RECT  27.209 51.264 27.299 54.072 ;
     RECT  27.065 65.136 27.389 74.04 ;
     RECT  27.155 3.936 27.605 4.632 ;
     RECT  27.299 51.264 27.605 54.024 ;
     RECT  27.389 65.424 27.785 74.04 ;
     RECT  27.155 7.344 27.821 7.944 ;
     RECT  27.004 9.552 27.821 10.968 ;
     RECT  27.004 55.248 27.929 57.048 ;
     RECT  27.004 60.816 27.98 61.416 ;
     RECT  27.605 54 28.001 54.024 ;
     RECT  27.004 62.4 28.021 63.096 ;
     RECT  27.601 76.368 28.069 76.392 ;
     RECT  27.997 0.576 28.081 0.6 ;
     RECT  27.925 1.68 28.105 1.704 ;
     RECT  27.605 4.176 28.105 4.632 ;
     RECT  27.98 59.856 28.105 61.416 ;
     RECT  28.021 62.4 28.105 64.008 ;
     RECT  27.004 58.176 28.124 58.488 ;
     RECT  28.124 58.176 28.141 58.68 ;
     RECT  28.105 59.856 28.141 64.008 ;
     RECT  28.069 76.368 28.163 76.968 ;
     RECT  27.929 56.304 28.165 57.048 ;
     RECT  28.141 58.176 28.165 64.008 ;
     RECT  28.165 56.304 28.177 64.008 ;
     RECT  28.105 4.176 28.189 5.16 ;
     RECT  28.105 45.552 28.189 45.576 ;
     RECT  28.105 1.68 28.213 1.752 ;
     RECT  27.065 75.216 28.213 75.288 ;
     RECT  28.163 76.368 28.213 76.44 ;
     RECT  28.177 56.304 28.289 64.44 ;
     RECT  28.213 1.152 28.297 1.752 ;
     RECT  27.004 49.2 28.309 49.224 ;
     RECT  28.309 49.2 28.433 50.136 ;
     RECT  28.289 56.448 28.433 64.44 ;
     RECT  28.297 1.68 28.451 1.752 ;
     RECT  28.451 1.728 28.573 1.752 ;
     RECT  28.117 2.784 28.573 2.808 ;
     RECT  28.189 4.176 28.573 4.632 ;
     RECT  27.821 9.6 28.789 10.968 ;
     RECT  28.213 75.216 28.835 76.44 ;
     RECT  27.605 51.264 28.844 52.728 ;
     RECT  28.433 49.2 28.861 49.416 ;
     RECT  27.785 65.424 28.861 73.944 ;
     RECT  28.835 75.216 28.861 75.864 ;
     RECT  28.844 51.264 28.897 53.448 ;
     RECT  28.897 51.216 28.969 53.448 ;
     RECT  28.969 51.168 29.041 53.448 ;
     RECT  28.433 57.936 29.077 64.44 ;
     RECT  28.861 65.424 29.077 75.864 ;
     RECT  28.277 77.616 29.125 77.64 ;
     RECT  28.853 5.616 29.173 5.736 ;
     RECT  28.573 1.728 29.221 4.632 ;
     RECT  29.173 5.616 29.221 6.12 ;
     RECT  27.821 7.344 29.269 7.368 ;
     RECT  29.041 50.592 29.269 53.448 ;
     RECT  29.077 57.936 29.308 75.864 ;
     RECT  29.269 50.592 29.329 54.12 ;
     RECT  27.929 55.248 29.329 55.272 ;
     RECT  28.433 56.448 29.329 56.904 ;
     RECT  29.125 77.52 29.341 77.64 ;
     RECT  29.221 1.728 29.408 6.12 ;
     RECT  29.269 7.344 29.408 7.848 ;
     RECT  28.789 9.36 29.408 10.968 ;
     RECT  27.004 31.728 29.408 31.752 ;
     RECT  28.861 49.008 29.408 49.416 ;
     RECT  29.329 50.592 29.408 56.904 ;
     RECT  29.308 57.936 29.408 75.768 ;
     RECT  29.408 1.728 29.411 75.768 ;
     RECT  29.411 1.728 29.603 75.72 ;
     RECT  29.603 1.728 29.704 75.576 ;
     RECT  28.885 0.096 29.749 0.12 ;
     RECT  29.704 50.592 30.017 75.576 ;
     RECT  29.341 77.52 30.037 77.592 ;
     RECT  29.749 0.096 30.049 0.312 ;
     RECT  30.049 0.096 30.077 0.36 ;
     RECT  30.017 58.368 30.161 75.576 ;
     RECT  30.161 58.464 30.197 75.576 ;
     RECT  30.037 77.472 30.229 77.592 ;
     RECT  29.704 48.24 30.323 49.56 ;
     RECT  30.017 50.592 30.593 57.192 ;
     RECT  29.704 7.344 30.689 7.944 ;
     RECT  29.704 31.728 30.733 31.752 ;
     RECT  30.593 50.592 30.737 57.144 ;
     RECT  30.229 77.376 30.755 77.592 ;
     RECT  30.077 0.096 30.769 0.456 ;
     RECT  30.733 31.632 30.773 31.752 ;
     RECT  30.737 50.592 31.052 57.048 ;
     RECT  29.704 1.728 31.165 2.28 ;
     RECT  29.704 3.408 31.165 5.448 ;
     RECT  31.165 1.728 31.277 5.448 ;
     RECT  31.273 46.656 31.301 46.68 ;
     RECT  30.323 48.24 31.301 49.32 ;
     RECT  30.769 0.096 31.523 0.552 ;
     RECT  30.985 41.04 31.525 41.064 ;
     RECT  29.704 42.384 31.525 42.744 ;
     RECT  30.197 58.464 31.561 75.336 ;
     RECT  31.523 0.096 31.601 0.216 ;
     RECT  30.689 7.344 31.669 7.992 ;
     RECT  31.525 41.04 31.669 43.656 ;
     RECT  31.561 58.464 31.669 75.816 ;
     RECT  31.277 2.016 31.813 5.448 ;
     RECT  31.813 2.016 31.861 5.928 ;
     RECT  31.669 40.464 31.885 43.656 ;
     RECT  31.877 9.696 31.909 9.72 ;
     RECT  29.704 10.944 31.909 10.968 ;
     RECT  30.773 31.632 31.909 31.656 ;
     RECT  30.805 77.616 31.909 77.64 ;
     RECT  31.909 34.08 31.957 34.104 ;
     RECT  31.093 45.648 31.957 45.672 ;
     RECT  31.301 46.656 31.957 49.32 ;
     RECT  31.052 50.4 31.957 57.048 ;
     RECT  31.669 58.464 32.003 76.392 ;
     RECT  31.861 2.016 32.108 6.264 ;
     RECT  31.669 7.344 32.108 8.52 ;
     RECT  31.909 9.696 32.108 9.816 ;
     RECT  31.909 10.944 32.108 11.064 ;
     RECT  31.877 18.816 32.108 18.84 ;
     RECT  31.909 31.632 32.108 31.752 ;
     RECT  31.957 34.08 32.108 34.2 ;
     RECT  31.957 35.52 32.108 35.544 ;
     RECT  29.704 37.584 32.108 37.608 ;
     RECT  31.885 40.464 32.108 44.472 ;
     RECT  31.957 45.648 32.108 57.048 ;
     RECT  32.003 58.464 32.108 75.816 ;
     RECT  31.601 0.144 32.195 0.216 ;
     RECT  32.108 2.016 32.291 75.816 ;
     RECT  32.291 2.016 32.389 75.768 ;
     RECT  32.389 1.728 32.404 75.768 ;
     RECT  32.404 60.48 32.501 75.768 ;
     RECT  32.404 49.2 32.579 50.904 ;
     RECT  32.404 46.08 32.609 47.928 ;
     RECT  32.404 51.888 32.609 56.904 ;
     RECT  32.579 49.392 32.675 50.904 ;
     RECT  32.609 46.08 32.681 46.824 ;
     RECT  32.404 42.576 32.789 44.616 ;
     RECT  32.195 0.144 32.819 0.168 ;
     RECT  32.404 37.584 32.825 37.608 ;
     RECT  32.404 19.968 32.941 19.992 ;
     RECT  32.404 1.728 32.956 8.376 ;
     RECT  32.404 18.24 32.963 18.264 ;
     RECT  32.789 42.576 32.963 44.472 ;
     RECT  32.404 41.04 32.969 41.064 ;
     RECT  32.404 58.224 33.011 59.304 ;
     RECT  32.956 1.728 33.049 8.088 ;
     RECT  33.049 7.392 33.059 8.088 ;
     RECT  31.909 77.52 33.109 77.64 ;
     RECT  33.059 7.392 33.113 8.04 ;
     RECT  32.404 39.888 33.113 39.912 ;
     RECT  32.404 33.456 33.293 33.48 ;
     RECT  32.404 36.48 33.365 36.504 ;
     RECT  33.011 58.224 33.433 59.256 ;
     RECT  33.113 7.392 33.491 7.8 ;
     RECT  32.501 60.48 33.505 75.72 ;
     RECT  33.491 7.392 33.545 7.512 ;
     RECT  32.609 51.888 33.637 56.856 ;
     RECT  33.433 57.936 33.637 59.256 ;
     RECT  33.545 7.392 33.653 7.464 ;
     RECT  32.675 49.392 33.685 50.856 ;
     RECT  33.637 51.888 33.685 59.256 ;
     RECT  33.505 60.24 33.685 75.72 ;
     RECT  33.397 29.04 33.721 29.064 ;
     RECT  32.681 46.08 33.757 46.104 ;
     RECT  32.404 31.728 33.761 31.944 ;
     RECT  33.109 77.472 33.781 77.64 ;
     RECT  33.721 29.04 33.901 29.64 ;
     RECT  33.901 29.04 33.925 30.024 ;
     RECT  33.925 28.272 33.937 30.024 ;
     RECT  33.761 31.728 33.937 31.896 ;
     RECT  33.865 33.6 33.973 33.624 ;
     RECT  33.937 34.752 33.973 34.776 ;
     RECT  33.781 77.424 34.019 77.64 ;
     RECT  34.019 77.472 34.049 77.64 ;
     RECT  33.685 49.392 34.069 59.256 ;
     RECT  33.685 60.24 34.069 75.768 ;
     RECT  32.963 42.576 34.153 44.28 ;
     RECT  33.757 46.08 34.153 46.632 ;
     RECT  34.153 45.552 34.189 46.632 ;
     RECT  32.609 47.904 34.189 47.928 ;
     RECT  34.153 42.576 34.225 44.424 ;
     RECT  34.225 42.576 34.513 44.472 ;
     RECT  34.049 77.472 34.553 77.496 ;
     RECT  33.049 1.728 34.621 6.36 ;
     RECT  33.653 7.392 34.621 7.416 ;
     RECT  33.973 33.6 34.693 34.776 ;
     RECT  33.613 38.784 34.765 38.808 ;
     RECT  34.189 45.552 34.801 47.928 ;
     RECT  34.069 49.392 34.805 75.768 ;
     RECT  34.621 1.728 34.808 7.416 ;
     RECT  32.404 9.792 34.808 9.816 ;
     RECT  33.865 10.8 34.808 10.824 ;
     RECT  34.685 18.24 34.808 18.264 ;
     RECT  33.884 27.216 34.808 27.24 ;
     RECT  33.937 28.272 34.808 31.896 ;
     RECT  34.693 33.6 34.808 35.88 ;
     RECT  34.765 38.256 34.808 38.808 ;
     RECT  33.793 40.176 34.808 40.2 ;
     RECT  34.513 41.664 34.808 44.472 ;
     RECT  34.801 45.552 34.808 47.976 ;
     RECT  34.805 49.392 34.808 75.72 ;
     RECT  34.808 1.728 35.104 75.72 ;
     RECT  35.104 49.536 35.165 51.24 ;
     RECT  35.104 3.216 35.201 6.312 ;
     RECT  35.104 75.696 35.201 75.72 ;
     RECT  35.104 7.344 35.219 7.416 ;
     RECT  35.104 31.776 35.219 32.472 ;
     RECT  35.104 40.416 35.237 43.032 ;
     RECT  35.104 16.56 35.245 17.64 ;
     RECT  35.104 47.904 35.245 48.456 ;
     RECT  35.237 42.288 35.273 43.032 ;
     RECT  35.104 65.952 35.309 70.008 ;
     RECT  35.104 71.472 35.317 74.712 ;
     RECT  35.309 65.952 35.417 68.568 ;
     RECT  35.237 40.416 35.459 41.064 ;
     RECT  35.165 50.304 35.489 51.24 ;
     RECT  35.219 7.392 35.507 7.416 ;
     RECT  35.104 1.728 35.525 1.752 ;
     RECT  35.104 45.696 35.533 46.728 ;
     RECT  35.309 69.84 35.633 70.008 ;
     RECT  35.104 28.992 35.813 30.6 ;
     RECT  35.317 71.472 35.813 74.088 ;
     RECT  35.201 5.136 35.849 5.64 ;
     RECT  35.104 38.064 35.849 38.808 ;
     RECT  35.104 33.6 35.891 33.624 ;
     RECT  35.104 52.464 35.891 64.104 ;
     RECT  35.273 42.72 36.029 43.032 ;
     RECT  35.891 64.08 36.029 64.104 ;
     RECT  35.489 50.304 36.035 51.192 ;
     RECT  35.104 27.888 36.065 27.912 ;
     RECT  35.104 9.792 36.101 9.96 ;
     RECT  36.101 9.936 36.131 9.96 ;
     RECT  35.104 13.296 36.131 13.32 ;
     RECT  35.533 45.696 36.14 46.68 ;
     RECT  35.813 71.472 36.205 73.32 ;
     RECT  35.813 30.144 36.241 30.6 ;
     RECT  35.219 31.824 36.241 32.472 ;
     RECT  35.459 41.04 36.313 41.064 ;
     RECT  35.891 52.464 36.316 63 ;
     RECT  36.316 54.864 36.353 63 ;
     RECT  35.417 66.144 36.419 68.568 ;
     RECT  36.029 42.768 36.457 43.032 ;
     RECT  35.104 44.4 36.469 44.472 ;
     RECT  36.14 45.552 36.469 46.68 ;
     RECT  35.849 5.136 36.497 5.16 ;
     RECT  36.373 64.368 36.505 64.968 ;
     RECT  36.353 54.864 36.508 60.168 ;
     RECT  35.104 34.896 36.517 35.88 ;
     RECT  35.104 37.008 36.517 37.032 ;
     RECT  36.085 14.304 36.533 14.328 ;
     RECT  36.241 30.144 36.533 32.472 ;
     RECT  36.457 42.768 36.541 43.32 ;
     RECT  36.469 44.4 36.601 46.68 ;
     RECT  36.419 66.768 36.601 68.568 ;
     RECT  36.316 52.464 36.709 53.88 ;
     RECT  35.104 22.08 36.781 22.104 ;
     RECT  36.517 34.896 36.781 37.032 ;
     RECT  35.849 38.064 36.781 38.28 ;
     RECT  36.205 71.376 36.781 73.32 ;
     RECT  36.745 27.312 36.805 27.336 ;
     RECT  35.813 28.992 36.805 29.112 ;
     RECT  36.601 44.4 36.817 46.776 ;
     RECT  35.245 47.904 36.817 48.024 ;
     RECT  35.633 69.984 36.853 70.008 ;
     RECT  36.781 71.376 36.853 73.368 ;
     RECT  36.817 75.264 36.853 75.288 ;
     RECT  36.781 34.896 36.925 38.28 ;
     RECT  36.719 23.328 36.949 23.352 ;
     RECT  36.949 23.328 36.956 23.928 ;
     RECT  36.313 41.04 36.961 41.16 ;
     RECT  36.956 23.328 36.997 24.504 ;
     RECT  36.533 31.392 36.997 32.472 ;
     RECT  36.817 44.4 37.033 48.024 ;
     RECT  36.961 41.04 37.141 41.736 ;
     RECT  36.925 34.896 37.285 39.24 ;
     RECT  37.285 34.896 37.465 39.864 ;
     RECT  37.141 40.944 37.465 41.736 ;
     RECT  35.201 3.216 37.508 4.152 ;
     RECT  35.245 17.424 37.508 17.64 ;
     RECT  36.781 21.648 37.508 22.104 ;
     RECT  36.997 23.328 37.508 25.224 ;
     RECT  36.805 26.784 37.508 27.336 ;
     RECT  36.805 28.416 37.508 29.112 ;
     RECT  36.533 30.144 37.508 30.168 ;
     RECT  36.997 31.392 37.508 33.144 ;
     RECT  37.465 34.896 37.508 41.736 ;
     RECT  36.541 42.768 37.508 43.032 ;
     RECT  37.033 44.4 37.508 48.984 ;
     RECT  36.035 50.832 37.508 51.192 ;
     RECT  36.709 52.272 37.508 53.88 ;
     RECT  36.508 54.864 37.508 59.592 ;
     RECT  36.353 61.152 37.508 63 ;
     RECT  36.505 64.944 37.508 64.968 ;
     RECT  36.601 66.768 37.508 68.616 ;
     RECT  36.853 69.984 37.508 75.288 ;
     RECT  37.508 2.148 37.612 75.612 ;
     RECT  37.612 2.418 37.804 75.342 ;
     RECT  37.804 57.84 37.937 58.152 ;
     RECT  37.804 17.328 37.955 17.64 ;
     RECT  37.804 24.864 37.955 25.224 ;
     RECT  37.804 28.032 37.955 28.68 ;
     RECT  37.804 30.048 37.955 31.416 ;
     RECT  37.955 28.032 37.973 28.44 ;
     RECT  37.804 68.976 37.973 73.32 ;
     RECT  37.937 57.888 38.009 58.152 ;
     RECT  37.804 52.272 38.045 53.88 ;
     RECT  38.045 52.272 38.081 53.592 ;
     RECT  37.804 59.232 38.081 61.176 ;
     RECT  38.081 52.704 38.189 53.592 ;
     RECT  37.804 36 38.261 37.272 ;
     RECT  37.804 74.592 38.261 75.096 ;
     RECT  38.261 74.64 38.333 75.096 ;
     RECT  38.189 52.992 38.369 53.592 ;
     RECT  37.804 44.448 38.441 50.856 ;
     RECT  38.333 74.832 38.549 75.096 ;
     RECT  37.973 68.976 38.665 70.68 ;
     RECT  37.955 17.328 38.801 17.448 ;
     RECT  38.441 44.784 38.801 50.856 ;
     RECT  38.549 74.88 38.819 75.096 ;
     RECT  37.955 30.048 38.873 31.32 ;
     RECT  38.009 57.936 38.909 58.152 ;
     RECT  37.955 25.2 38.972 25.224 ;
     RECT  37.804 38.256 38.972 41.16 ;
     RECT  37.804 32.448 38.977 33 ;
     RECT  38.081 61.152 38.981 61.176 ;
     RECT  38.873 30.048 39.013 30.888 ;
     RECT  37.804 34.896 39.013 34.92 ;
     RECT  38.972 38.256 39.013 41.304 ;
     RECT  37.804 42.576 39.013 43.272 ;
     RECT  38.972 25.056 39.059 25.224 ;
     RECT  37.804 67.104 39.077 67.848 ;
     RECT  38.869 75.168 39.089 75.192 ;
     RECT  38.977 32.448 39.157 33.24 ;
     RECT  39.013 34.224 39.157 34.92 ;
     RECT  39.077 67.104 39.161 68.424 ;
     RECT  37.973 71.808 39.193 73.32 ;
     RECT  38.261 36 39.203 37.08 ;
     RECT  38.369 53.568 39.229 53.592 ;
     RECT  39.193 71.808 39.233 73.56 ;
     RECT  37.804 62.448 39.301 63.72 ;
     RECT  37.973 28.032 39.349 28.392 ;
     RECT  38.665 69.408 39.397 70.68 ;
     RECT  39.161 67.104 39.517 67.848 ;
     RECT  39.229 53.568 39.733 54.12 ;
     RECT  37.804 55.44 39.733 56.568 ;
     RECT  39.203 36.048 39.836 37.08 ;
     RECT  39.013 38.256 39.836 43.272 ;
     RECT  38.801 45.6 39.841 50.856 ;
     RECT  39.733 53.568 39.841 56.568 ;
     RECT  38.909 57.936 39.841 57.96 ;
     RECT  39.445 44.256 39.877 44.28 ;
     RECT  39.841 45.456 39.877 50.856 ;
     RECT  39.836 36.048 39.884 43.272 ;
     RECT  39.877 44.256 39.884 50.856 ;
     RECT  39.233 72.432 39.913 73.56 ;
     RECT  38.081 59.232 40.069 59.496 ;
     RECT  37.804 3.936 40.208 3.96 ;
     RECT  38.801 17.424 40.208 17.448 ;
     RECT  39.445 21.456 40.208 21.48 ;
     RECT  39.349 28.032 40.208 28.632 ;
     RECT  39.013 29.76 40.208 30.888 ;
     RECT  39.157 32.448 40.208 34.92 ;
     RECT  39.884 36.048 40.208 50.856 ;
     RECT  39.517 52.176 40.208 52.2 ;
     RECT  39.841 53.568 40.208 57.96 ;
     RECT  40.069 58.992 40.208 59.496 ;
     RECT  39.049 61.104 40.208 61.128 ;
     RECT  39.301 62.448 40.208 63.912 ;
     RECT  40.201 64.992 40.208 65.016 ;
     RECT  39.517 66.768 40.208 67.848 ;
     RECT  39.397 69.408 40.208 71.304 ;
     RECT  39.913 72.432 40.208 74.088 ;
     RECT  40.208 2.148 40.312 75.612 ;
     RECT  40.312 2.418 40.504 75.342 ;
     RECT  40.504 45.792 40.529 48.744 ;
     RECT  40.504 64.992 40.637 65.016 ;
     RECT  40.529 46.272 40.745 48.744 ;
     RECT  40.504 69.984 40.787 70.968 ;
     RECT  40.504 72.336 40.787 73.224 ;
     RECT  40.787 69.984 40.925 70.824 ;
     RECT  40.504 56.016 40.997 56.568 ;
     RECT  40.504 17.424 41.027 17.448 ;
     RECT  40.745 47.376 41.033 48.744 ;
     RECT  40.504 27.36 41.041 27.384 ;
     RECT  40.504 21.36 41.068 21.48 ;
     RECT  40.504 52.176 41.069 53.016 ;
     RECT  40.504 36.048 41.075 44.472 ;
     RECT  40.504 57.84 41.105 57.864 ;
     RECT  40.504 30.336 41.177 31.56 ;
     RECT  41.075 42.768 41.249 44.472 ;
     RECT  40.504 54.72 41.249 54.744 ;
     RECT  41.249 43.008 41.537 44.472 ;
     RECT  40.504 32.784 41.641 32.808 ;
     RECT  40.504 33.888 41.641 34.92 ;
     RECT  41.075 36.048 41.641 41.784 ;
     RECT  41.537 43.152 41.645 44.472 ;
     RECT  41.641 32.784 41.681 41.784 ;
     RECT  41.033 47.664 41.713 48.744 ;
     RECT  41.069 52.992 41.717 53.016 ;
     RECT  40.504 66.768 41.749 67.176 ;
     RECT  41.177 30.336 41.789 30.84 ;
     RECT  40.745 46.272 41.861 46.296 ;
     RECT  40.997 56.4 41.897 56.568 ;
     RECT  40.504 58.992 42.037 62.52 ;
     RECT  41.749 66 42.073 67.176 ;
     RECT  41.789 30.336 42.145 30.456 ;
     RECT  42.001 26.256 42.188 26.28 ;
     RECT  42.188 25.68 42.229 26.28 ;
     RECT  40.925 70.8 42.253 70.824 ;
     RECT  42.044 27.888 42.284 27.912 ;
     RECT  42.145 29.04 42.284 30.456 ;
     RECT  41.857 22.752 42.325 22.776 ;
     RECT  42.284 27.888 42.325 30.456 ;
     RECT  41.713 47.664 42.361 49.224 ;
     RECT  40.787 72.528 42.361 72.552 ;
     RECT  40.504 75.216 42.361 75.24 ;
     RECT  41.681 33.072 42.433 41.784 ;
     RECT  42.361 47.664 42.433 49.32 ;
     RECT  42.361 72.432 42.469 72.552 ;
     RECT  42.361 74.832 42.505 75.432 ;
     RECT  42.469 72.384 42.541 72.552 ;
     RECT  42.253 70.272 42.6 71.112 ;
     RECT  42.541 72.384 42.6 72.84 ;
     RECT  42.109 64.368 42.613 64.392 ;
     RECT  42.073 65.76 42.613 67.176 ;
     RECT  42.6 70.272 42.661 72.84 ;
     RECT  42.433 46.896 42.685 49.32 ;
     RECT  42.433 50.592 42.685 50.616 ;
     RECT  42.433 33.072 42.757 42.168 ;
     RECT  41.645 43.152 42.757 43.32 ;
     RECT  42.613 64.368 42.757 67.176 ;
     RECT  42.661 70.272 42.757 72.984 ;
     RECT  42.505 74.112 42.757 75.432 ;
     RECT  41.897 56.544 42.829 56.568 ;
     RECT  42.037 58.128 42.829 62.52 ;
     RECT  42.757 45.552 42.865 45.576 ;
     RECT  42.685 46.896 42.865 50.616 ;
     RECT  42.325 52.752 42.901 52.776 ;
     RECT  42.145 53.808 42.901 53.832 ;
     RECT  40.504 3.936 42.908 3.96 ;
     RECT  41.068 21.456 42.908 21.48 ;
     RECT  42.325 22.752 42.908 23.976 ;
     RECT  42.229 25.248 42.908 26.28 ;
     RECT  42.325 27.84 42.908 30.456 ;
     RECT  42.709 31.92 42.908 31.944 ;
     RECT  42.757 33.072 42.908 43.32 ;
     RECT  41.645 44.4 42.908 44.472 ;
     RECT  42.865 45.552 42.908 50.616 ;
     RECT  42.901 52.752 42.908 53.832 ;
     RECT  42.421 55.44 42.908 55.464 ;
     RECT  42.829 56.544 42.908 62.52 ;
     RECT  42.757 64.368 42.908 68.088 ;
     RECT  42.757 70.272 42.908 75.432 ;
     RECT  42.908 2.148 43.141 75.612 ;
     RECT  43.141 1.728 43.204 75.816 ;
     RECT  43.204 3.936 43.265 3.96 ;
     RECT  43.204 27.888 43.265 29.064 ;
     RECT  43.204 74.592 43.265 75.816 ;
     RECT  43.204 25.248 43.301 26.808 ;
     RECT  43.204 54.624 43.301 59.016 ;
     RECT  43.204 34.368 43.331 34.488 ;
     RECT  43.204 1.728 43.337 1.752 ;
     RECT  43.204 35.808 43.373 41.304 ;
     RECT  43.204 69.504 43.373 73.368 ;
     RECT  43.301 25.824 43.379 26.808 ;
     RECT  43.373 36.048 43.481 41.304 ;
     RECT  43.204 61.104 43.517 67.8 ;
     RECT  43.301 58.128 43.589 59.016 ;
     RECT  43.517 62.352 43.589 67.8 ;
     RECT  43.379 25.824 43.625 25.848 ;
     RECT  43.301 54.624 43.697 56.904 ;
     RECT  43.204 44.064 43.769 50.712 ;
     RECT  43.204 23.568 43.913 23.592 ;
     RECT  43.265 27.888 43.913 29.016 ;
     RECT  43.769 46.464 43.949 50.712 ;
     RECT  43.697 54.624 43.955 56.568 ;
     RECT  43.949 46.464 44.021 49.512 ;
     RECT  43.589 62.352 44.099 65.16 ;
     RECT  43.769 44.064 44.129 45.048 ;
     RECT  44.099 63.216 44.129 65.16 ;
     RECT  43.913 28.512 44.201 29.016 ;
     RECT  44.129 63.312 44.243 65.16 ;
     RECT  43.949 50.688 44.245 50.712 ;
     RECT  43.517 61.104 44.245 61.128 ;
     RECT  43.373 72.528 44.341 73.368 ;
     RECT  43.265 74.592 44.341 75.432 ;
     RECT  43.589 66.144 44.377 67.8 ;
     RECT  43.204 30.336 44.381 30.36 ;
     RECT  43.373 69.504 44.437 71.448 ;
     RECT  44.341 72.528 44.437 75.432 ;
     RECT  43.589 58.704 44.449 59.016 ;
     RECT  43.481 36.048 44.485 41.064 ;
     RECT  43.955 54.72 44.489 56.568 ;
     RECT  44.377 66.144 44.557 67.896 ;
     RECT  44.129 45.024 44.561 45.048 ;
     RECT  44.557 66.144 44.561 68.184 ;
     RECT  44.201 28.512 44.597 28.536 ;
     RECT  44.561 66.192 44.633 68.184 ;
     RECT  44.449 58.704 44.869 59.304 ;
     RECT  43.331 34.368 44.881 34.392 ;
     RECT  44.633 66.24 44.953 68.184 ;
     RECT  44.485 35.808 44.965 41.064 ;
     RECT  44.449 42.192 44.965 42.216 ;
     RECT  44.021 46.464 45.061 47.736 ;
     RECT  44.021 48.96 45.061 49.512 ;
     RECT  44.881 30.672 45.068 30.696 ;
     RECT  43.204 32.352 45.068 32.52 ;
     RECT  44.489 54.72 45.169 55.464 ;
     RECT  44.869 58.656 45.169 59.304 ;
     RECT  45.068 30.672 45.205 32.52 ;
     RECT  44.881 33.6 45.205 34.392 ;
     RECT  45.169 58.128 45.349 59.304 ;
     RECT  44.489 56.544 45.529 56.568 ;
     RECT  45.349 58.128 45.529 59.832 ;
     RECT  45.169 62.208 45.565 62.232 ;
     RECT  44.243 63.312 45.565 63.816 ;
     RECT  45.565 27.936 45.608 27.96 ;
     RECT  45.205 30.672 45.608 34.392 ;
     RECT  44.965 35.808 45.608 42.216 ;
     RECT  45.169 44.448 45.608 44.472 ;
     RECT  45.061 46.464 45.608 49.512 ;
     RECT  44.245 50.688 45.608 51.144 ;
     RECT  43.204 52.992 45.608 53.016 ;
     RECT  45.169 54.096 45.608 55.464 ;
     RECT  45.529 56.544 45.608 59.832 ;
     RECT  44.245 60.816 45.608 61.128 ;
     RECT  45.565 62.208 45.608 63.816 ;
     RECT  44.243 64.944 45.608 65.16 ;
     RECT  44.953 66.24 45.608 68.232 ;
     RECT  44.437 69.504 45.608 75.432 ;
     RECT  45.608 2.148 45.712 75.612 ;
     RECT  45.712 2.418 45.904 75.342 ;
     RECT  45.904 32.352 45.965 34.392 ;
     RECT  45.904 56.544 46.001 58.44 ;
     RECT  45.904 68.928 46.019 69.048 ;
     RECT  45.904 35.808 46.037 36.264 ;
     RECT  45.904 60.816 46.037 67.896 ;
     RECT  45.904 54.096 46.181 54.12 ;
     RECT  45.904 50.784 46.217 52.488 ;
     RECT  45.904 59.808 46.217 59.832 ;
     RECT  46.037 63.456 46.289 67.896 ;
     RECT  46.289 63.456 46.361 67.848 ;
     RECT  45.965 33.6 46.397 34.392 ;
     RECT  45.904 27.408 46.433 31.272 ;
     RECT  45.904 26.352 46.469 26.376 ;
     RECT  46.037 60.816 46.577 62.472 ;
     RECT  45.904 38.16 46.613 40.344 ;
     RECT  45.904 23.904 46.721 23.928 ;
     RECT  46.577 60.816 46.739 61.464 ;
     RECT  45.904 46.464 46.793 48.984 ;
     RECT  46.361 63.456 46.793 66.696 ;
     RECT  46.793 64.56 46.848 66.696 ;
     RECT  46.848 64.944 46.883 66.696 ;
     RECT  46.433 27.888 46.897 31.272 ;
     RECT  45.965 32.352 46.897 32.52 ;
     RECT  46.037 36.096 46.897 36.264 ;
     RECT  46.019 69.024 46.897 69.048 ;
     RECT  46.897 27.888 46.937 32.52 ;
     RECT  45.904 70.272 46.973 72.984 ;
     RECT  46.361 67.824 46.979 67.848 ;
     RECT  45.904 55.296 47.041 55.464 ;
     RECT  46.793 48.528 47.045 48.984 ;
     RECT  46.217 51.888 47.045 52.488 ;
     RECT  45.904 25.104 47.081 25.128 ;
     RECT  46.613 38.16 47.113 39.768 ;
     RECT  46.217 50.784 47.153 50.808 ;
     RECT  46.883 66.192 47.153 66.696 ;
     RECT  47.153 66.672 47.189 66.696 ;
     RECT  46.001 57.312 47.221 58.44 ;
     RECT  46.973 71.472 47.269 72.984 ;
     RECT  45.904 74.064 47.269 75.288 ;
     RECT  46.793 63.456 47.276 63.48 ;
     RECT  45.904 41.568 47.297 43.272 ;
     RECT  47.269 71.472 47.315 75.288 ;
     RECT  45.904 44.352 47.437 44.472 ;
     RECT  46.793 46.464 47.581 47.064 ;
     RECT  47.045 51.888 47.617 52.008 ;
     RECT  47.581 46.224 47.653 47.064 ;
     RECT  46.739 61.008 47.725 61.464 ;
     RECT  47.276 62.64 47.725 63.48 ;
     RECT  47.437 44.352 47.797 44.616 ;
     RECT  47.113 37.824 47.833 39.768 ;
     RECT  47.653 46.128 47.905 47.064 ;
     RECT  47.045 48.528 47.905 48.552 ;
     RECT  47.221 57.024 47.977 58.44 ;
     RECT  47.725 61.008 47.977 63.48 ;
     RECT  46.397 34.368 48.013 34.392 ;
     RECT  47.185 53.328 48.013 53.4 ;
     RECT  47.617 51.408 48.049 52.008 ;
     RECT  48.013 53.136 48.049 53.4 ;
     RECT  47.905 46.128 48.085 48.552 ;
     RECT  47.869 49.728 48.085 49.752 ;
     RECT  46.937 27.888 48.121 32.376 ;
     RECT  48.013 33.552 48.121 34.392 ;
     RECT  47.833 37.728 48.121 39.768 ;
     RECT  47.401 25.152 48.157 25.272 ;
     RECT  48.049 51.408 48.181 53.4 ;
     RECT  47.041 54.72 48.181 55.464 ;
     RECT  47.977 56.592 48.181 58.44 ;
     RECT  47.185 23.808 48.308 23.832 ;
     RECT  48.157 25.152 48.308 25.32 ;
     RECT  47.005 26.592 48.308 26.616 ;
     RECT  48.121 27.888 48.308 34.392 ;
     RECT  46.897 36.096 48.308 36.312 ;
     RECT  48.121 37.728 48.308 40.152 ;
     RECT  47.297 41.568 48.308 42.744 ;
     RECT  47.797 43.872 48.308 44.616 ;
     RECT  48.085 46.128 48.308 49.752 ;
     RECT  48.181 51.408 48.308 53.544 ;
     RECT  48.181 54.672 48.308 58.44 ;
     RECT  48.301 59.76 48.308 59.784 ;
     RECT  47.977 61.008 48.308 63.624 ;
     RECT  46.883 65.136 48.308 65.16 ;
     RECT  46.897 69.024 48.308 69.096 ;
     RECT  46.973 70.272 48.308 70.296 ;
     RECT  47.315 71.856 48.308 75.288 ;
     RECT  48.308 2.148 48.412 75.612 ;
     RECT  48.412 2.418 48.604 75.342 ;
     RECT  48.604 32.544 48.629 36.12 ;
     RECT  48.604 38.16 48.737 40.2 ;
     RECT  48.604 55.44 48.755 59.784 ;
     RECT  48.604 67.008 48.845 70.344 ;
     RECT  48.604 71.808 48.851 74.424 ;
     RECT  48.851 71.856 48.881 74.424 ;
     RECT  48.604 60.96 48.899 63.864 ;
     RECT  48.604 24.624 49.025 26.616 ;
     RECT  48.604 65.136 49.025 65.544 ;
     RECT  48.845 70.128 49.025 70.344 ;
     RECT  48.604 22.8 49.061 23.304 ;
     RECT  48.881 71.856 49.061 73.128 ;
     RECT  48.604 42.24 49.097 48.648 ;
     RECT  48.604 49.92 49.097 50.184 ;
     RECT  48.845 67.008 49.133 69 ;
     RECT  48.629 32.544 49.169 35.304 ;
     RECT  49.097 42.72 49.205 48.648 ;
     RECT  49.025 70.128 49.241 70.296 ;
     RECT  48.604 28.224 49.277 29.832 ;
     RECT  48.755 55.44 49.421 59.448 ;
     RECT  49.133 68.448 49.421 69 ;
     RECT  48.881 74.112 49.571 74.424 ;
     RECT  49.025 65.328 49.597 65.544 ;
     RECT  49.133 67.008 49.597 67.272 ;
     RECT  49.241 70.272 49.637 70.296 ;
     RECT  49.061 23.04 49.669 23.304 ;
     RECT  49.169 34.128 49.673 35.304 ;
     RECT  48.899 60.96 49.709 63.624 ;
     RECT  49.709 60.96 49.745 61.176 ;
     RECT  49.421 68.976 49.745 69 ;
     RECT  49.597 65.328 49.804 67.272 ;
     RECT  49.745 60.96 49.805 61.128 ;
     RECT  48.604 51.408 49.813 53.352 ;
     RECT  49.571 74.4 49.853 74.424 ;
     RECT  49.805 60.288 49.859 61.128 ;
     RECT  49.169 32.544 49.885 32.952 ;
     RECT  49.813 51.408 49.885 53.592 ;
     RECT  49.205 42.72 49.961 48.504 ;
     RECT  49.421 55.44 49.993 58.728 ;
     RECT  49.025 25.104 50.029 26.616 ;
     RECT  50.029 25.104 50.033 26.856 ;
     RECT  49.804 65.328 50.093 66.888 ;
     RECT  49.669 23.04 50.101 23.544 ;
     RECT  49.885 51.264 50.101 53.592 ;
     RECT  49.993 54.816 50.101 58.728 ;
     RECT  48.737 38.208 50.149 40.2 ;
     RECT  49.277 28.224 50.209 29.592 ;
     RECT  50.033 25.2 50.245 26.856 ;
     RECT  50.209 27.888 50.245 29.592 ;
     RECT  49.709 62.544 50.281 63.624 ;
     RECT  50.281 62.544 50.317 63.864 ;
     RECT  50.093 64.896 50.317 66.888 ;
     RECT  50.149 38.208 50.389 40.872 ;
     RECT  49.673 34.368 50.425 35.304 ;
     RECT  50.101 22.848 50.641 23.544 ;
     RECT  49.885 32.112 50.677 32.952 ;
     RECT  49.961 45.12 50.713 48.504 ;
     RECT  49.097 49.92 50.713 49.944 ;
     RECT  49.859 60.288 50.857 60.984 ;
     RECT  50.857 60.288 50.929 61.368 ;
     RECT  50.641 22.848 51.008 23.88 ;
     RECT  50.245 25.2 51.008 29.592 ;
     RECT  50.677 32.112 51.008 33.144 ;
     RECT  50.425 34.368 51.008 35.976 ;
     RECT  50.389 38.208 51.008 41.256 ;
     RECT  49.961 42.72 51.008 43.944 ;
     RECT  50.713 45.12 51.008 49.944 ;
     RECT  50.101 51.264 51.008 58.728 ;
     RECT  50.929 59.856 51.008 61.368 ;
     RECT  50.317 62.544 51.008 66.888 ;
     RECT  49.061 72.48 51.008 73.128 ;
     RECT  51.001 74.64 51.008 74.664 ;
     RECT  51.008 2.148 51.112 75.612 ;
     RECT  51.112 2.418 51.304 75.612 ;
     RECT  51.304 34.368 51.401 35.784 ;
     RECT  51.304 46.752 51.401 47.88 ;
     RECT  51.304 70.704 51.401 71.928 ;
     RECT  51.401 70.704 51.473 71.832 ;
     RECT  51.401 35.76 51.509 35.784 ;
     RECT  51.304 67.968 51.545 69.576 ;
     RECT  51.304 51.648 51.761 53.064 ;
     RECT  51.304 40.032 51.789 45.624 ;
     RECT  51.304 74.592 51.793 75.612 ;
     RECT  51.401 46.752 51.827 47.736 ;
     RECT  51.304 50.352 51.833 50.664 ;
     RECT  51.304 66 51.833 66.888 ;
     RECT  51.793 74.592 51.865 75.864 ;
     RECT  51.789 43.296 51.905 45.624 ;
     RECT  51.304 22.464 51.941 33.144 ;
     RECT  51.865 74.592 51.973 75.912 ;
     RECT  51.577 76.896 51.973 76.92 ;
     RECT  51.973 74.592 52.067 76.92 ;
     RECT  52.067 74.592 52.157 76.488 ;
     RECT  51.905 45.504 52.229 45.624 ;
     RECT  51.473 70.704 52.259 71.496 ;
     RECT  51.304 37.776 52.297 39.048 ;
     RECT  51.941 22.752 52.301 29.112 ;
     RECT  52.301 22.752 52.337 28.584 ;
     RECT  51.761 51.84 52.369 53.064 ;
     RECT  51.789 40.032 52.373 41.784 ;
     RECT  52.297 37.344 52.405 39.048 ;
     RECT  51.545 67.968 52.445 68.76 ;
     RECT  51.304 59.76 52.477 62.232 ;
     RECT  51.304 63.264 52.477 64.824 ;
     RECT  51.833 66.768 52.477 66.888 ;
     RECT  52.445 67.968 52.477 68.232 ;
     RECT  52.337 22.848 52.481 28.584 ;
     RECT  51.941 30.144 52.481 33.144 ;
     RECT  51.827 46.8 52.513 47.736 ;
     RECT  51.304 55.44 52.513 58.152 ;
     RECT  52.259 71.472 52.513 71.496 ;
     RECT  52.481 23.04 52.517 27.912 ;
     RECT  52.405 37.056 52.549 39.048 ;
     RECT  52.373 40.032 52.549 41.016 ;
     RECT  52.549 37.056 52.553 41.016 ;
     RECT  51.401 34.368 52.595 34.392 ;
     RECT  52.553 37.056 52.625 39.768 ;
     RECT  52.157 74.64 52.661 76.488 ;
     RECT  51.833 50.4 52.729 50.664 ;
     RECT  52.477 59.76 52.765 64.824 ;
     RECT  52.685 77.616 52.769 77.64 ;
     RECT  52.765 59.76 52.981 65.736 ;
     RECT  51.905 43.872 53.017 44.472 ;
     RECT  52.229 45.504 53.017 45.576 ;
     RECT  52.513 71.472 53.045 72.408 ;
     RECT  52.885 73.488 53.045 73.512 ;
     RECT  52.661 74.688 53.065 76.488 ;
     RECT  52.801 42.72 53.089 42.744 ;
     RECT  53.017 43.872 53.089 45.576 ;
     RECT  52.513 55.344 53.233 58.152 ;
     RECT  53.233 54.72 53.341 58.152 ;
     RECT  53.161 69.84 53.365 69.864 ;
     RECT  52.477 66.768 53.413 68.232 ;
     RECT  53.365 69.504 53.413 69.864 ;
     RECT  52.517 24.624 53.449 27.912 ;
     RECT  53.045 71.472 53.461 73.512 ;
     RECT  52.517 23.04 53.509 23.304 ;
     RECT  53.449 24.624 53.509 28.776 ;
     RECT  52.481 30.144 53.509 32.328 ;
     RECT  53.089 42.72 53.557 45.576 ;
     RECT  52.729 50.4 53.557 50.712 ;
     RECT  52.369 51.84 53.557 53.352 ;
     RECT  52.981 59.472 53.557 65.736 ;
     RECT  53.413 66.768 53.557 69.864 ;
     RECT  53.509 22.848 53.593 23.304 ;
     RECT  52.513 46.8 53.665 48.456 ;
     RECT  53.341 54.528 53.665 58.152 ;
     RECT  53.557 59.472 53.665 69.864 ;
     RECT  53.593 22.752 53.708 23.304 ;
     RECT  53.509 24.624 53.708 32.328 ;
     RECT  52.801 34.8 53.708 34.968 ;
     RECT  52.625 37.776 53.708 39.768 ;
     RECT  52.553 40.848 53.708 41.016 ;
     RECT  53.557 42.24 53.708 45.576 ;
     RECT  53.665 46.8 53.708 49.08 ;
     RECT  53.557 50.4 53.708 53.352 ;
     RECT  53.665 54.528 53.708 69.864 ;
     RECT  53.461 71.184 53.708 73.512 ;
     RECT  53.065 74.688 53.708 75.864 ;
     RECT  53.305 76.944 53.749 76.968 ;
     RECT  53.708 2.148 53.812 75.864 ;
     RECT  53.812 2.418 54.004 75.864 ;
     RECT  54.004 32.736 54.131 36.504 ;
     RECT  54.004 38.208 54.131 42.168 ;
     RECT  54.004 65.184 54.131 74.136 ;
     RECT  53.749 76.944 54.133 77.64 ;
     RECT  54.004 43.344 54.165 43.752 ;
     RECT  54.004 22.608 54.179 24.648 ;
     RECT  54.004 62.448 54.209 63.816 ;
     RECT  54.131 65.424 54.253 74.136 ;
     RECT  54.004 44.832 54.317 51.24 ;
     RECT  54.004 52.704 54.317 58.152 ;
     RECT  54.165 43.728 54.323 43.752 ;
     RECT  54.131 36.48 54.389 36.504 ;
     RECT  54.131 38.208 54.497 41.064 ;
     RECT  54.133 76.896 54.563 77.64 ;
     RECT  54.004 75.264 54.641 75.864 ;
     RECT  54.563 77.52 54.659 77.64 ;
     RECT  54.641 75.312 54.713 75.864 ;
     RECT  54.497 40.848 54.749 41.064 ;
     RECT  54.317 44.832 54.749 49.08 ;
     RECT  54.131 42.144 54.785 42.168 ;
     RECT  54.317 54.192 54.785 58.152 ;
     RECT  54.131 32.736 54.821 35.448 ;
     RECT  54.713 75.36 54.893 75.864 ;
     RECT  54.785 58.128 54.929 58.152 ;
     RECT  54.004 29.808 54.965 30.6 ;
     RECT  54.749 44.832 54.965 47.16 ;
     RECT  54.253 65.424 54.965 73.512 ;
     RECT  54.004 59.472 54.997 59.88 ;
     RECT  54.004 60.912 54.997 61.368 ;
     RECT  54.965 65.424 55.001 70.824 ;
     RECT  54.821 32.736 55.033 34.104 ;
     RECT  54.997 59.472 55.033 61.368 ;
     RECT  54.179 22.608 55.037 23.592 ;
     RECT  55.033 31.872 55.037 34.104 ;
     RECT  55.001 65.424 55.037 68.616 ;
     RECT  54.004 28.752 55.105 28.776 ;
     RECT  54.821 35.424 55.181 35.448 ;
     RECT  54.497 38.208 55.213 39.528 ;
     RECT  55.033 59.472 55.213 61.608 ;
     RECT  54.209 62.688 55.213 63.816 ;
     RECT  55.037 31.872 55.235 33.096 ;
     RECT  55.037 22.608 55.253 23.112 ;
     RECT  55.213 59.472 55.253 63.816 ;
     RECT  54.749 48.432 55.285 49.08 ;
     RECT  54.317 50.112 55.285 51.24 ;
     RECT  54.893 75.792 55.285 75.864 ;
     RECT  55.285 48.432 55.331 51.24 ;
     RECT  54.317 52.704 55.397 53.064 ;
     RECT  55.213 37.632 55.429 39.528 ;
     RECT  54.965 30.576 55.433 30.6 ;
     RECT  54.965 71.808 55.477 73.512 ;
     RECT  54.659 77.568 55.717 77.64 ;
     RECT  55.429 36.864 55.825 39.528 ;
     RECT  54.749 40.848 55.825 40.872 ;
     RECT  55.285 75.792 55.829 76.392 ;
     RECT  55.825 36.864 55.861 40.872 ;
     RECT  55.829 75.792 55.861 75.816 ;
     RECT  55.861 75.744 55.865 75.816 ;
     RECT  54.004 25.728 55.897 27.624 ;
     RECT  55.105 28.752 55.897 29.064 ;
     RECT  55.717 77.52 55.957 77.64 ;
     RECT  54.785 54.192 55.969 56.904 ;
     RECT  55.331 49.2 56.005 51.24 ;
     RECT  55.037 65.424 56.005 68.232 ;
     RECT  55.001 69.84 56.053 70.824 ;
     RECT  55.477 71.808 56.053 74.088 ;
     RECT  55.861 35.712 56.108 40.872 ;
     RECT  55.429 41.904 56.108 41.928 ;
     RECT  55.253 59.472 56.108 63.624 ;
     RECT  55.861 43.104 56.149 43.896 ;
     RECT  56.053 69.84 56.177 74.088 ;
     RECT  56.149 43.104 56.185 44.088 ;
     RECT  54.965 45.216 56.185 47.16 ;
     RECT  56.108 35.712 56.401 41.928 ;
     RECT  56.185 43.104 56.401 47.16 ;
     RECT  55.253 23.04 56.408 23.112 ;
     RECT  54.179 24.624 56.408 24.648 ;
     RECT  55.897 25.728 56.408 29.064 ;
     RECT  55.235 32.208 56.408 33.096 ;
     RECT  55.037 34.08 56.408 34.104 ;
     RECT  56.401 35.712 56.408 47.16 ;
     RECT  56.005 49.2 56.408 51.96 ;
     RECT  55.397 52.992 56.408 53.064 ;
     RECT  55.969 54.192 56.408 57.624 ;
     RECT  56.108 58.608 56.408 63.624 ;
     RECT  56.005 65.184 56.408 68.232 ;
     RECT  56.177 69.504 56.408 74.088 ;
     RECT  55.865 75.744 56.408 75.768 ;
     RECT  56.408 2.148 56.512 75.768 ;
     RECT  55.957 77.424 56.629 77.64 ;
     RECT  56.512 2.418 56.704 75.768 ;
     RECT  56.704 37.632 56.801 39.048 ;
     RECT  56.704 44.256 56.819 47.976 ;
     RECT  56.801 38.112 56.873 39.048 ;
     RECT  56.704 52.992 56.873 58.344 ;
     RECT  56.704 59.472 56.873 61.176 ;
     RECT  56.629 77.328 56.915 77.64 ;
     RECT  56.915 77.424 56.941 77.64 ;
     RECT  56.704 23.04 56.945 23.832 ;
     RECT  56.873 52.992 56.945 57.288 ;
     RECT  56.704 36.528 56.981 36.552 ;
     RECT  56.704 40.656 56.981 42.888 ;
     RECT  56.819 44.256 57.017 47.64 ;
     RECT  56.945 53.136 57.233 57.288 ;
     RECT  56.873 59.472 57.233 61.128 ;
     RECT  56.704 28.272 57.269 28.296 ;
     RECT  57.233 53.136 57.305 53.88 ;
     RECT  56.941 77.424 57.337 77.688 ;
     RECT  57.233 55.008 57.341 57.288 ;
     RECT  56.704 31.152 57.413 31.272 ;
     RECT  57.413 31.152 57.521 31.224 ;
     RECT  57.305 53.616 57.521 53.64 ;
     RECT  56.704 34.08 57.539 34.104 ;
     RECT  56.873 38.112 57.539 38.472 ;
     RECT  57.341 55.44 57.539 57.288 ;
     RECT  56.873 58.32 57.539 58.344 ;
     RECT  56.704 50.64 57.554 51.336 ;
     RECT  56.704 64.944 57.589 75.768 ;
     RECT  57.521 31.2 57.593 31.224 ;
     RECT  57.554 50.688 57.593 51.336 ;
     RECT  56.945 23.04 57.697 23.64 ;
     RECT  56.981 40.656 57.737 41.64 ;
     RECT  57.233 59.472 57.953 61.032 ;
     RECT  57.017 44.256 58.093 46.104 ;
     RECT  56.704 62.4 58.093 62.568 ;
     RECT  58.093 44.016 58.129 46.104 ;
     RECT  57.017 47.136 58.129 47.64 ;
     RECT  57.539 55.44 58.133 56.952 ;
     RECT  57.589 64.944 58.133 75.816 ;
     RECT  56.981 42.768 58.273 42.888 ;
     RECT  58.129 44.016 58.273 47.64 ;
     RECT  57.953 60.816 58.357 61.032 ;
     RECT  58.093 62.112 58.357 62.568 ;
     RECT  56.704 63.792 58.463 63.816 ;
     RECT  58.133 64.944 58.463 75.288 ;
     RECT  57.737 40.656 58.489 40.68 ;
     RECT  58.273 42.768 58.597 47.64 ;
     RECT  56.704 49.2 58.597 49.608 ;
     RECT  58.357 60.816 58.597 62.568 ;
     RECT  58.597 60.816 58.645 62.616 ;
     RECT  58.463 63.792 58.645 75.288 ;
     RECT  57.697 22.272 58.669 23.64 ;
     RECT  58.597 29.52 58.693 29.544 ;
     RECT  58.693 29.52 58.705 29.64 ;
     RECT  56.704 35.232 58.705 35.256 ;
     RECT  58.705 34.752 58.741 35.256 ;
     RECT  57.593 50.688 58.741 50.712 ;
     RECT  57.539 38.448 58.777 38.472 ;
     RECT  58.741 50.64 58.777 50.712 ;
     RECT  57.953 59.472 58.777 59.832 ;
     RECT  58.381 28.224 58.849 28.248 ;
     RECT  58.705 29.328 58.849 29.64 ;
     RECT  58.705 53.808 58.885 53.832 ;
     RECT  58.597 42.768 58.957 49.608 ;
     RECT  58.777 50.64 58.957 51.384 ;
     RECT  58.669 22.272 59.108 23.976 ;
     RECT  58.849 28.224 59.108 29.64 ;
     RECT  58.957 30.672 59.108 30.696 ;
     RECT  58.741 34.416 59.108 35.256 ;
     RECT  58.777 37.968 59.108 38.472 ;
     RECT  58.489 40.368 59.108 40.68 ;
     RECT  58.957 42.768 59.108 52.056 ;
     RECT  58.885 53.04 59.108 53.832 ;
     RECT  58.133 55.776 59.108 56.952 ;
     RECT  58.777 58.704 59.108 59.832 ;
     RECT  58.645 60.816 59.108 75.288 ;
     RECT  59.108 2.148 59.212 75.612 ;
     RECT  59.212 2.418 59.404 75.342 ;
     RECT  59.404 42.192 59.501 52.68 ;
     RECT  59.404 55.344 59.501 57.624 ;
     RECT  59.404 67.152 59.501 72.168 ;
     RECT  59.404 40.368 59.537 41.064 ;
     RECT  59.501 42.192 59.537 47.352 ;
     RECT  59.404 58.704 59.573 63.048 ;
     RECT  59.501 72.144 59.573 72.168 ;
     RECT  59.501 48.384 59.645 52.68 ;
     RECT  59.645 48.384 59.681 52.584 ;
     RECT  59.501 55.344 59.747 56.088 ;
     RECT  59.501 67.392 59.789 71.112 ;
     RECT  57.337 77.424 59.789 77.736 ;
     RECT  59.404 54.096 59.795 54.12 ;
     RECT  59.404 33.024 59.825 33.048 ;
     RECT  59.747 55.44 59.833 56.088 ;
     RECT  59.404 64.608 59.861 65.592 ;
     RECT  59.404 25.104 59.897 25.128 ;
     RECT  59.404 23.904 59.933 23.928 ;
     RECT  59.404 26.496 59.969 26.616 ;
     RECT  59.789 68.208 60.005 71.112 ;
     RECT  59.404 74.4 60.005 74.952 ;
     RECT  59.573 58.8 60.041 63.048 ;
     RECT  60.041 58.8 60.077 59.928 ;
     RECT  59.861 64.608 60.077 65.544 ;
     RECT  59.969 26.544 60.185 26.616 ;
     RECT  59.537 40.416 60.257 41.064 ;
     RECT  59.789 77.472 60.329 77.736 ;
     RECT  60.005 69.312 60.401 71.112 ;
     RECT  59.404 34.08 60.469 34.104 ;
     RECT  59.404 30.672 60.473 31.848 ;
     RECT  60.401 69.456 60.473 71.112 ;
     RECT  60.257 41.04 60.541 41.064 ;
     RECT  60.005 68.208 60.545 68.232 ;
     RECT  60.329 77.568 60.545 77.736 ;
     RECT  60.545 77.568 60.581 77.64 ;
     RECT  59.404 28.416 60.617 28.44 ;
     RECT  60.541 41.04 60.62 41.592 ;
     RECT  59.537 42.72 60.62 47.352 ;
     RECT  59.681 48.384 60.659 52.44 ;
     RECT  60.473 69.984 60.685 71.112 ;
     RECT  60.473 30.816 60.689 31.848 ;
     RECT  60.659 50.016 60.7 52.44 ;
     RECT  60.005 74.4 60.761 74.424 ;
     RECT  59.833 56.064 60.829 56.088 ;
     RECT  59.501 57.072 60.829 57.624 ;
     RECT  60.829 54.672 60.901 54.696 ;
     RECT  60.041 61.344 61.045 63.048 ;
     RECT  60.581 77.616 61.049 77.64 ;
     RECT  60.185 26.592 61.261 26.616 ;
     RECT  60.077 58.8 61.297 59.832 ;
     RECT  61.045 61.344 61.297 63.096 ;
     RECT  60.901 54.624 61.369 54.696 ;
     RECT  60.7 50.112 61.477 52.44 ;
     RECT  61.369 53.712 61.477 54.696 ;
     RECT  61.261 26.304 61.549 26.616 ;
     RECT  61.513 39.84 61.573 39.864 ;
     RECT  60.62 41.04 61.573 47.352 ;
     RECT  60.077 64.752 61.585 65.544 ;
     RECT  61.297 58.8 61.621 63.096 ;
     RECT  61.585 64.128 61.621 65.544 ;
     RECT  60.973 36.288 61.669 36.312 ;
     RECT  59.404 37.392 61.669 38.472 ;
     RECT  60.901 23.664 61.808 23.688 ;
     RECT  61.549 26.304 61.808 26.664 ;
     RECT  59.404 29.52 61.808 29.64 ;
     RECT  60.689 30.96 61.808 31.848 ;
     RECT  60.469 34.08 61.808 34.2 ;
     RECT  59.404 35.232 61.808 35.256 ;
     RECT  61.669 36.288 61.808 38.472 ;
     RECT  61.573 39.84 61.808 47.352 ;
     RECT  60.659 48.384 61.808 48.408 ;
     RECT  61.477 50.112 61.808 54.696 ;
     RECT  60.829 56.064 61.808 57.624 ;
     RECT  61.621 58.8 61.808 65.544 ;
     RECT  60.685 69.984 61.808 71.592 ;
     RECT  61.808 2.148 61.912 75.612 ;
     RECT  61.912 2.418 62.104 75.342 ;
     RECT  62.104 59.04 62.243 61.656 ;
     RECT  62.104 48.384 62.273 50.184 ;
     RECT  62.104 69.984 62.309 71.88 ;
     RECT  62.309 70.032 62.381 71.88 ;
     RECT  62.104 55.152 62.489 57.432 ;
     RECT  62.104 25.2 62.597 26.664 ;
     RECT  62.104 31.488 62.597 31.512 ;
     RECT  62.104 62.736 62.705 64.968 ;
     RECT  62.597 25.296 62.741 26.664 ;
     RECT  62.104 51.216 62.777 53.112 ;
     RECT  62.104 29.52 62.885 30.168 ;
     RECT  62.777 52.512 62.885 53.112 ;
     RECT  62.777 51.216 62.921 51.48 ;
     RECT  62.705 62.88 62.921 64.968 ;
     RECT  62.381 70.416 62.963 71.88 ;
     RECT  62.885 52.992 63.097 53.112 ;
     RECT  62.104 42.816 63.169 46.536 ;
     RECT  62.489 55.152 63.173 57.096 ;
     RECT  63.097 52.992 63.181 53.592 ;
     RECT  62.243 59.04 63.245 60.264 ;
     RECT  63.169 42.816 63.299 47.304 ;
     RECT  62.963 70.656 63.317 71.064 ;
     RECT  62.104 34.224 63.397 35.016 ;
     RECT  63.349 31.92 63.443 32.328 ;
     RECT  63.397 33.312 63.443 35.016 ;
     RECT  63.443 33.312 63.484 33.336 ;
     RECT  62.243 61.344 63.493 61.656 ;
     RECT  63.299 42.816 63.497 46.584 ;
     RECT  63.245 59.232 63.529 60.264 ;
     RECT  63.493 61.344 63.529 61.704 ;
     RECT  62.273 48.48 63.601 50.184 ;
     RECT  63.173 55.152 63.673 56.424 ;
     RECT  63.601 47.808 63.781 50.184 ;
     RECT  62.921 51.216 63.781 51.432 ;
     RECT  62.104 36.288 63.853 37.464 ;
     RECT  62.104 38.448 63.853 38.472 ;
     RECT  62.885 29.52 63.925 29.88 ;
     RECT  62.921 62.88 64.177 64.056 ;
     RECT  63.529 59.232 64.249 61.704 ;
     RECT  64.177 27.888 64.285 27.912 ;
     RECT  63.925 29.52 64.285 30.408 ;
     RECT  63.853 36.288 64.321 38.472 ;
     RECT  63.673 54.672 64.393 56.424 ;
     RECT  64.321 36.24 64.465 38.472 ;
     RECT  64.429 39.744 64.465 39.768 ;
     RECT  64.393 54.672 64.465 56.856 ;
     RECT  64.021 57.84 64.465 57.864 ;
     RECT  62.741 26.256 64.508 26.664 ;
     RECT  64.285 27.888 64.508 28.248 ;
     RECT  64.285 29.52 64.508 30.792 ;
     RECT  63.443 31.92 64.508 31.944 ;
     RECT  63.443 34.992 64.508 35.016 ;
     RECT  64.465 36.24 64.508 39.768 ;
     RECT  63.497 43.296 64.508 46.584 ;
     RECT  63.781 47.808 64.508 51.432 ;
     RECT  63.181 52.992 64.508 53.352 ;
     RECT  64.465 54.672 64.508 58.152 ;
     RECT  64.249 59.184 64.508 61.704 ;
     RECT  64.177 62.88 64.508 64.44 ;
     RECT  64.177 68.928 64.508 68.952 ;
     RECT  63.317 70.656 64.508 70.68 ;
     RECT  64.508 2.148 64.612 75.612 ;
     RECT  64.612 2.418 64.804 75.342 ;
     RECT  64.804 50.688 64.931 55.8 ;
     RECT  64.804 56.832 64.931 57.144 ;
     RECT  64.804 70.272 64.931 70.68 ;
     RECT  64.931 50.688 64.937 53.592 ;
     RECT  64.804 34.992 64.973 41.208 ;
     RECT  64.804 42.768 64.973 49.368 ;
     RECT  64.937 50.688 64.973 53.064 ;
     RECT  64.931 54.624 64.973 55.8 ;
     RECT  64.973 50.688 64.979 53.016 ;
     RECT  64.804 33.504 65.081 33.528 ;
     RECT  64.804 58.128 65.189 59.304 ;
     RECT  65.189 59.232 65.261 59.304 ;
     RECT  64.973 48.336 65.267 49.368 ;
     RECT  64.804 29.52 65.297 30.936 ;
     RECT  65.261 59.232 65.333 59.256 ;
     RECT  64.804 60.384 65.513 61.704 ;
     RECT  64.979 52.224 65.555 53.016 ;
     RECT  64.804 64.416 65.557 66.12 ;
     RECT  65.513 60.384 65.621 61.656 ;
     RECT  64.804 67.248 65.621 68.952 ;
     RECT  65.267 48.336 65.693 49.224 ;
     RECT  64.804 31.92 65.797 31.944 ;
     RECT  65.621 60.384 65.837 61.56 ;
     RECT  64.973 34.992 65.945 41.16 ;
     RECT  64.979 50.688 66.013 51.24 ;
     RECT  66.013 50.352 66.085 51.24 ;
     RECT  65.555 52.224 66.085 52.248 ;
     RECT  64.804 62.688 66.085 63.432 ;
     RECT  65.557 64.416 66.085 65.16 ;
     RECT  65.945 40.992 66.125 41.16 ;
     RECT  65.945 34.992 66.133 39.864 ;
     RECT  66.133 34.368 66.179 39.864 ;
     RECT  64.931 57.12 66.229 57.144 ;
     RECT  65.189 58.128 66.229 58.152 ;
     RECT  64.973 42.768 66.301 47.112 ;
     RECT  65.297 29.616 66.373 30.936 ;
     RECT  65.797 31.92 66.373 32.232 ;
     RECT  64.973 54.624 66.553 55.656 ;
     RECT  66.229 57.12 66.625 58.152 ;
     RECT  66.301 42.768 66.805 47.16 ;
     RECT  66.805 42.72 67.057 47.16 ;
     RECT  65.693 48.336 67.057 49.032 ;
     RECT  64.804 26.256 67.165 26.76 ;
     RECT  67.165 25.488 67.208 26.76 ;
     RECT  66.373 29.616 67.208 32.232 ;
     RECT  66.179 34.368 67.208 34.92 ;
     RECT  66.179 35.952 67.208 39.864 ;
     RECT  66.125 41.136 67.208 41.16 ;
     RECT  67.057 42.72 67.208 49.032 ;
     RECT  66.085 50.352 67.208 52.248 ;
     RECT  66.229 53.568 67.208 53.592 ;
     RECT  66.553 54.624 67.208 55.704 ;
     RECT  66.625 57.12 67.208 58.968 ;
     RECT  65.837 60.384 67.208 61.368 ;
     RECT  66.085 62.688 67.208 65.16 ;
     RECT  65.621 67.248 67.208 67.272 ;
     RECT  65.621 68.928 67.208 68.952 ;
     RECT  64.931 70.272 67.208 70.296 ;
     RECT  67.208 2.148 67.312 75.612 ;
     RECT  67.312 2.418 67.504 75.342 ;
     RECT  67.504 55.008 67.565 64.44 ;
     RECT  67.504 47.424 67.637 49.464 ;
     RECT  67.504 25.488 67.673 25.56 ;
     RECT  67.565 58.944 67.709 64.44 ;
     RECT  67.565 55.008 67.763 57.672 ;
     RECT  67.763 55.008 67.804 55.704 ;
     RECT  67.504 31.968 67.853 31.992 ;
     RECT  67.504 42.24 67.853 43.656 ;
     RECT  67.504 51.888 67.853 52.2 ;
     RECT  67.709 62.16 67.853 64.44 ;
     RECT  67.504 36.24 68.105 41.256 ;
     RECT  68.105 40.032 68.177 41.256 ;
     RECT  67.804 55.248 68.213 55.704 ;
     RECT  67.504 28.992 68.285 29.016 ;
     RECT  67.709 58.944 68.285 61.08 ;
     RECT  67.504 68.4 68.429 68.952 ;
     RECT  67.673 25.536 68.465 25.56 ;
     RECT  67.504 30.576 68.497 30.648 ;
     RECT  67.763 57.024 68.573 57.672 ;
     RECT  68.285 59.04 68.573 61.08 ;
     RECT  68.105 36.24 68.609 38.952 ;
     RECT  67.504 53.568 68.609 53.592 ;
     RECT  67.504 46.032 68.641 46.056 ;
     RECT  67.504 33.36 68.677 34.968 ;
     RECT  68.429 68.4 68.677 68.424 ;
     RECT  67.637 48.384 68.713 49.464 ;
     RECT  67.853 42.24 68.717 42.504 ;
     RECT  67.853 43.536 68.753 43.656 ;
     RECT  68.497 30.576 68.821 30.744 ;
     RECT  67.504 70.704 68.821 70.728 ;
     RECT  67.504 44.928 68.857 44.952 ;
     RECT  68.677 32.592 68.861 34.968 ;
     RECT  68.821 30.144 68.905 30.888 ;
     RECT  68.821 70.512 68.917 70.728 ;
     RECT  68.641 45.984 68.965 46.056 ;
     RECT  68.713 48.384 68.965 49.752 ;
     RECT  68.857 44.736 69.073 44.952 ;
     RECT  68.177 40.416 69.181 41.256 ;
     RECT  67.853 51.888 69.205 51.912 ;
     RECT  69.073 44.736 69.289 45 ;
     RECT  68.609 37.296 69.349 38.952 ;
     RECT  69.181 40.032 69.349 41.256 ;
     RECT  67.853 62.16 69.356 63.864 ;
     RECT  68.213 55.248 69.397 55.272 ;
     RECT  68.965 47.856 69.433 49.752 ;
     RECT  68.717 42.48 69.781 42.504 ;
     RECT  68.753 43.536 69.781 43.56 ;
     RECT  69.205 51.792 69.781 51.912 ;
     RECT  69.433 47.328 69.901 49.752 ;
     RECT  69.793 26.88 69.908 26.904 ;
     RECT  68.905 30.144 69.908 30.744 ;
     RECT  68.861 32.592 69.908 34.92 ;
     RECT  68.609 36.24 69.908 36.312 ;
     RECT  69.349 37.296 69.908 41.256 ;
     RECT  69.781 42.48 69.908 43.56 ;
     RECT  69.289 44.544 69.908 45 ;
     RECT  68.965 45.984 69.908 46.104 ;
     RECT  69.901 47.136 69.908 49.752 ;
     RECT  69.781 51.36 69.908 51.912 ;
     RECT  69.109 52.896 69.908 52.92 ;
     RECT  69.356 54.096 69.908 54.12 ;
     RECT  69.397 55.248 69.908 55.992 ;
     RECT  68.573 57.024 69.908 57.048 ;
     RECT  68.573 59.04 69.908 60.936 ;
     RECT  69.356 62.16 69.908 64.776 ;
     RECT  68.677 68.064 69.908 68.424 ;
     RECT  68.917 69.984 69.908 70.728 ;
     RECT  69.908 2.148 70.012 75.612 ;
     RECT  70.012 2.418 70.204 75.342 ;
     RECT  70.204 30.672 70.265 30.696 ;
     RECT  70.204 31.68 70.355 32.616 ;
     RECT  70.204 57.936 70.355 57.96 ;
     RECT  70.204 59.04 70.355 59.448 ;
     RECT  70.204 44.352 70.481 47.88 ;
     RECT  70.355 32.592 70.595 32.616 ;
     RECT  70.481 46.224 70.697 47.88 ;
     RECT  70.204 34.32 70.732 36.312 ;
     RECT  70.697 46.608 70.733 47.88 ;
     RECT  70.732 34.32 70.841 34.776 ;
     RECT  70.733 46.656 71.201 47.88 ;
     RECT  71.201 47.04 71.237 47.88 ;
     RECT  70.732 35.952 71.269 36.312 ;
     RECT  70.204 37.584 71.269 40.968 ;
     RECT  70.481 44.352 71.341 45.24 ;
     RECT  71.372 32.352 71.459 32.376 ;
     RECT  70.204 42.72 71.521 42.792 ;
     RECT  71.269 35.952 71.525 40.968 ;
     RECT  71.525 37.104 71.561 40.968 ;
     RECT  71.561 37.92 71.633 40.968 ;
     RECT  71.237 47.136 71.633 47.88 ;
     RECT  71.521 31.824 71.665 31.848 ;
     RECT  71.525 35.952 71.989 35.976 ;
     RECT  71.521 42.192 72.277 42.792 ;
     RECT  72.037 33.456 72.313 33.48 ;
     RECT  71.341 44.112 72.469 45.24 ;
     RECT  71.665 31.2 72.608 31.848 ;
     RECT  72.313 33.072 72.608 33.48 ;
     RECT  71.989 35.904 72.608 35.976 ;
     RECT  71.633 37.92 72.608 39.912 ;
     RECT  72.277 41.04 72.608 42.792 ;
     RECT  72.469 43.872 72.608 45.576 ;
     RECT  71.633 47.856 72.608 47.88 ;
     RECT  72.608 2.148 72.712 75.612 ;
     RECT  72.712 2.418 72.904 75.342 ;
     RECT  72.904 45.552 73.649 45.576 ;
     RECT  72.904 32.784 73.721 33.336 ;
     RECT  72.904 34.656 73.933 34.824 ;
     RECT  73.721 32.976 74.045 33.336 ;
     RECT  74.045 33.264 74.081 33.336 ;
     RECT  72.904 38.16 74.473 38.712 ;
     RECT  73.933 34.368 74.653 34.824 ;
     RECT  74.653 36.336 74.689 36.36 ;
     RECT  74.473 37.632 74.689 38.712 ;
     RECT  72.904 39.744 75.013 39.768 ;
     RECT  72.904 41.184 75.013 41.208 ;
     RECT  74.653 34.32 75.265 34.824 ;
     RECT  74.689 36.336 75.265 38.712 ;
     RECT  74.329 31.776 75.308 31.8 ;
     RECT  74.081 33.312 75.308 33.336 ;
     RECT  75.265 34.32 75.308 38.712 ;
     RECT  75.013 39.744 75.308 41.208 ;
     RECT  74.677 43.344 75.308 43.368 ;
     RECT  75.157 45.504 75.308 45.72 ;
     RECT  75.308 2.148 75.412 75.612 ;
     RECT  75.412 2.418 75.604 75.342 ;
     RECT  75.604 32.208 75.809 32.28 ;
     RECT  75.809 32.256 75.881 32.28 ;
     RECT  75.604 36.48 75.989 38.712 ;
     RECT  75.989 36.48 76.169 37.224 ;
     RECT  75.989 38.448 76.457 38.712 ;
     RECT  75.604 33.552 76.529 33.576 ;
     RECT  75.604 45.696 76.529 45.72 ;
     RECT  76.169 36.48 76.565 37.08 ;
     RECT  76.565 36.48 78.008 36.504 ;
     RECT  76.457 38.448 78.008 38.472 ;
     RECT  78.008 2.148 78.112 75.612 ;
     RECT  78.112 2.418 78.304 75.342 ;
     RECT  78.304 38.448 80.708 38.472 ;
     RECT  80.708 2.148 80.812 75.612 ;
     RECT  80.812 2.418 81.004 75.342 ;
     RECT  81.004 38.448 83.408 38.472 ;
     RECT  83.408 2.148 83.512 75.612 ;
     RECT  83.512 2.418 83.704 75.342 ;
     RECT  83.704 38.448 85.453 38.472 ;
     RECT  85.453 38.448 86.281 39.384 ;
     RECT  86.281 38.352 86.321 39.384 ;
    LAYER M5 ;
     RECT  28.032 0.016 34.296 0.611 ;
     RECT  28.128 0.611 34.296 1.763 ;
     RECT  28.608 1.763 34.296 2.137 ;
     RECT  2.4 2.137 2.52 2.151 ;
     RECT  5.1 2.137 5.22 2.151 ;
     RECT  7.8 2.137 7.92 2.151 ;
     RECT  10.5 2.137 10.62 2.151 ;
     RECT  13.2 2.137 13.32 2.151 ;
     RECT  15.9 2.137 16.02 2.151 ;
     RECT  18.6 2.137 18.72 2.151 ;
     RECT  21.3 2.137 21.42 2.151 ;
     RECT  24 2.137 24.12 2.151 ;
     RECT  26.7 2.137 26.82 2.151 ;
     RECT  28.608 2.137 34.92 2.151 ;
     RECT  37.5 2.137 37.62 2.151 ;
     RECT  40.2 2.137 40.32 2.151 ;
     RECT  42.9 2.137 43.176 2.151 ;
     RECT  45.6 2.137 45.72 2.151 ;
     RECT  48.3 2.137 48.42 2.151 ;
     RECT  51 2.137 51.12 2.151 ;
     RECT  53.7 2.137 53.82 2.151 ;
     RECT  56.4 2.137 56.52 2.151 ;
     RECT  59.1 2.137 59.22 2.151 ;
     RECT  61.8 2.137 61.92 2.151 ;
     RECT  64.5 2.137 64.62 2.151 ;
     RECT  67.2 2.137 67.32 2.151 ;
     RECT  69.9 2.137 70.02 2.151 ;
     RECT  72.6 2.137 72.72 2.151 ;
     RECT  75.3 2.137 75.42 2.151 ;
     RECT  78 2.137 78.12 2.151 ;
     RECT  80.7 2.137 80.82 2.151 ;
     RECT  83.4 2.137 83.52 2.151 ;
     RECT  28.608 2.151 35.112 2.773 ;
     RECT  37.5 2.151 37.812 3.205 ;
     RECT  26.7 2.151 27.012 3.301 ;
     RECT  36.72 3.205 37.812 3.971 ;
     RECT  28.128 2.773 35.112 4.019 ;
     RECT  31.2 4.019 35.112 4.067 ;
     RECT  31.68 4.067 35.112 4.595 ;
     RECT  31.824 4.595 35.112 4.643 ;
     RECT  28.128 4.019 29.712 5.171 ;
     RECT  31.872 4.643 35.112 5.605 ;
     RECT  31.872 5.605 35.496 5.893 ;
     RECT  31.824 5.893 35.496 6.371 ;
     RECT  34.656 6.371 35.496 6.947 ;
     RECT  28.704 5.171 29.712 7.379 ;
     RECT  31.824 6.371 33.144 7.765 ;
     RECT  29.28 7.379 29.712 7.859 ;
     RECT  30.72 5.077 30.744 8.003 ;
     RECT  31.824 7.765 33.48 8.485 ;
     RECT  34.704 6.947 35.496 9.925 ;
     RECT  24 2.151 24.312 10.405 ;
     RECT  26.7 3.301 27.144 10.451 ;
     RECT  28.128 10.405 28.152 10.931 ;
     RECT  34.704 9.925 36.12 14.339 ;
     RECT  24 10.405 24.408 14.435 ;
     RECT  40.2 2.151 40.512 17.413 ;
     RECT  37.5 3.971 37.812 17.605 ;
     RECT  34.704 14.339 35.496 17.651 ;
     RECT  34.704 17.651 35.112 18.275 ;
     RECT  42.9 2.151 43.212 21.445 ;
     RECT  37.5 17.605 37.944 21.637 ;
     RECT  36.816 21.637 37.944 22.069 ;
     RECT  59.1 2.151 59.412 22.501 ;
     RECT  42.432 21.445 43.212 22.741 ;
     RECT  53.7 2.151 54.012 22.837 ;
     RECT  58.704 22.501 59.412 23.075 ;
     RECT  36.768 22.069 37.944 23.363 ;
     RECT  53.52 22.837 54.012 23.557 ;
     RECT  42.336 22.741 43.212 23.987 ;
     RECT  53.52 23.557 54.168 24.659 ;
     RECT  42.432 23.987 43.212 25.237 ;
     RECT  52.464 25.141 52.488 25.427 ;
     RECT  42.24 25.237 43.212 25.715 ;
     RECT  42.432 25.715 43.212 25.813 ;
     RECT  53.52 24.659 54.012 26.053 ;
     RECT  42.432 25.813 43.368 26.819 ;
     RECT  31.68 8.485 33.48 27.205 ;
     RECT  34.8 18.275 35.112 27.205 ;
     RECT  40.2 17.413 41.016 27.395 ;
     RECT  42.432 26.819 43.212 27.829 ;
     RECT  42.336 27.829 43.212 27.877 ;
     RECT  39.024 25.045 39.048 28.021 ;
     RECT  40.2 27.395 40.512 28.021 ;
     RECT  39.024 28.021 40.512 28.163 ;
     RECT  31.68 27.205 35.112 29.075 ;
     RECT  52.56 26.053 54.012 29.267 ;
     RECT  59.1 23.075 59.412 29.509 ;
     RECT  34.8 29.075 35.112 29.605 ;
     RECT  58.704 29.509 59.412 29.651 ;
     RECT  36.816 23.363 37.944 30.133 ;
     RECT  45.6 2.151 45.912 30.661 ;
     RECT  36.576 30.133 37.944 30.757 ;
     RECT  39.36 28.163 40.512 30.757 ;
     RECT  36.576 30.757 40.512 30.899 ;
     RECT  68.832 30.133 68.856 30.899 ;
     RECT  67.2 2.151 67.512 31.285 ;
     RECT  36.576 30.899 37.944 31.427 ;
     RECT  51 2.151 51.312 31.525 ;
     RECT  52.56 29.267 52.584 31.525 ;
     RECT  69.9 2.151 70.212 31.669 ;
     RECT  34.8 29.605 35.208 31.813 ;
     RECT  48.3 2.151 48.612 32.101 ;
     RECT  36.576 31.427 37.812 32.437 ;
     RECT  40.2 30.899 40.512 32.437 ;
     RECT  45.12 30.661 45.912 32.531 ;
     RECT  69.9 31.669 70.344 32.581 ;
     RECT  71.424 32.341 71.448 32.581 ;
     RECT  55.2 31.861 55.224 32.771 ;
     RECT  39.888 32.437 40.512 32.773 ;
     RECT  42.096 27.877 43.212 32.773 ;
     RECT  36.576 32.437 38.184 32.819 ;
     RECT  48.192 32.101 48.612 33.107 ;
     RECT  51 31.525 52.584 33.155 ;
     RECT  69.9 32.581 71.448 33.445 ;
     RECT  72.6 2.151 72.912 33.445 ;
     RECT  34.8 31.813 35.304 33.589 ;
     RECT  36.576 32.819 37.812 33.589 ;
     RECT  39.888 32.773 43.212 33.827 ;
     RECT  56.4 2.151 56.712 34.069 ;
     RECT  63.408 31.909 63.432 34.259 ;
     RECT  66.384 31.285 67.512 34.357 ;
     RECT  52.56 33.155 52.584 34.403 ;
     RECT  66.144 34.357 67.512 34.403 ;
     RECT  40.08 33.827 43.212 34.453 ;
     RECT  66.144 34.403 66.168 35.027 ;
     RECT  53.7 29.267 54.012 35.413 ;
     RECT  56.4 34.069 57.528 35.701 ;
     RECT  69.9 33.445 72.912 35.939 ;
     RECT  40.08 34.453 43.32 35.989 ;
     RECT  67.2 34.403 67.512 36.325 ;
     RECT  53.7 35.413 54.12 36.515 ;
     RECT  64.5 2.151 64.812 36.901 ;
     RECT  61.8 2.151 62.112 36.997 ;
     RECT  64.5 36.901 64.92 37.043 ;
     RECT  39.168 35.989 43.32 37.091 ;
     RECT  69.9 35.939 71.448 37.091 ;
     RECT  69.9 37.091 70.584 37.429 ;
     RECT  64.5 37.043 64.812 37.477 ;
     RECT  59.1 29.651 59.412 37.573 ;
     RECT  61.68 36.997 62.112 37.619 ;
     RECT  55.872 35.701 57.528 37.621 ;
     RECT  39.888 37.091 43.32 37.667 ;
     RECT  64.272 37.477 64.812 38.101 ;
     RECT  64.272 38.101 64.92 38.195 ;
     RECT  48.3 33.107 48.612 38.293 ;
     RECT  51 33.155 51.312 38.293 ;
     RECT  45.6 32.531 45.912 38.341 ;
     RECT  59.1 37.573 60.12 38.387 ;
     RECT  50.832 38.293 51.312 38.437 ;
     RECT  45.6 38.341 46.776 38.483 ;
     RECT  48.3 38.293 49.08 38.627 ;
     RECT  55.728 37.621 57.528 38.675 ;
     RECT  50.832 38.437 52.104 38.723 ;
     RECT  68.976 37.429 70.584 38.723 ;
     RECT  68.976 38.723 70.212 38.915 ;
     RECT  39.888 37.667 43.212 38.963 ;
     RECT  64.5 38.195 64.92 38.963 ;
     RECT  67.2 36.325 67.8 39.395 ;
     RECT  39.888 38.963 40.512 39.541 ;
     RECT  39.6 39.541 40.512 39.733 ;
     RECT  69.36 38.915 70.212 39.779 ;
     RECT  56.4 38.675 57.528 39.781 ;
     RECT  61.8 37.619 62.112 39.829 ;
     RECT  51 38.723 51.312 39.877 ;
     RECT  72.6 35.939 72.912 39.877 ;
     RECT  67.2 39.395 67.608 39.923 ;
     RECT  39.312 39.733 40.512 40.405 ;
     RECT  50.688 39.877 51.312 40.405 ;
     RECT  75.3 2.151 75.612 40.405 ;
     RECT  61.584 39.829 62.112 40.499 ;
     RECT  50.688 40.405 51.768 40.837 ;
     RECT  56.16 39.781 57.528 40.883 ;
     RECT  31.68 29.075 33.48 41.029 ;
     RECT  45.6 38.483 45.912 41.029 ;
     RECT  34.8 33.589 37.812 41.075 ;
     RECT  72.384 39.877 72.912 41.075 ;
     RECT  75.024 40.405 75.612 41.173 ;
     RECT  39.312 40.405 41.064 41.269 ;
     RECT  56.16 40.883 56.904 41.939 ;
     RECT  53.7 36.515 54.012 41.989 ;
     RECT  61.8 40.499 62.112 42.133 ;
     RECT  39.024 41.269 41.064 42.227 ;
     RECT  44.976 41.029 45.912 42.227 ;
     RECT  56.4 41.939 56.904 42.227 ;
     RECT  48.3 38.627 48.612 42.229 ;
     RECT  39.312 42.227 41.064 42.419 ;
     RECT  48.3 42.229 49.032 42.709 ;
     RECT  50.16 40.837 51.768 42.709 ;
     RECT  69.9 39.779 70.212 42.709 ;
     RECT  48.3 42.709 51.768 42.755 ;
     RECT  36.576 41.075 37.812 42.803 ;
     RECT  60.672 42.133 62.112 43.043 ;
     RECT  74.688 41.173 75.612 43.379 ;
     RECT  31.536 41.029 33.48 43.667 ;
     RECT  53.7 41.989 54.12 43.717 ;
     RECT  32.1 43.667 33.48 43.813 ;
     RECT  56.4 42.227 56.712 43.861 ;
     RECT  72.6 41.075 72.912 43.861 ;
     RECT  51 42.755 51.312 44.245 ;
     RECT  45.6 42.227 45.912 44.437 ;
     RECT  56.304 43.861 56.712 44.437 ;
     RECT  53.7 43.717 54.312 44.677 ;
     RECT  37.5 42.803 37.812 44.773 ;
     RECT  56.304 44.437 57.576 44.965 ;
     RECT  59.1 38.387 59.412 44.965 ;
     RECT  64.5 38.963 64.812 45.157 ;
     RECT  56.304 44.965 59.412 45.205 ;
     RECT  55.824 45.205 59.412 45.251 ;
     RECT  51 44.245 51.864 45.493 ;
     RECT  53.136 44.677 54.312 45.493 ;
     RECT  51 45.493 54.312 45.539 ;
     RECT  32.1 43.813 33.672 45.541 ;
     RECT  34.8 41.075 35.448 45.541 ;
     RECT  36.48 43.285 36.504 45.541 ;
     RECT  60.672 43.043 60.696 45.541 ;
     RECT  60.432 45.541 60.696 45.587 ;
     RECT  39.312 42.419 40.512 45.635 ;
     RECT  32.1 45.541 36.504 45.685 ;
     RECT  37.5 44.773 38.232 45.685 ;
     RECT  75.168 43.379 75.612 45.731 ;
     RECT  32.1 45.685 38.232 45.973 ;
     RECT  55.824 45.251 56.712 46.067 ;
     RECT  64.5 45.157 64.92 46.117 ;
     RECT  48.3 42.755 49.56 46.211 ;
     RECT  31.968 45.973 38.232 46.499 ;
     RECT  45.6 44.437 46.872 46.499 ;
     RECT  31.968 46.499 37.812 46.645 ;
     RECT  45.6 46.499 45.912 46.693 ;
     RECT  58.368 45.251 59.412 46.787 ;
     RECT  64.5 46.117 65.592 46.787 ;
     RECT  56.304 46.067 56.712 46.835 ;
     RECT  51 45.539 52.584 47.075 ;
     RECT  52.56 47.075 52.584 47.123 ;
     RECT  42.432 38.963 43.212 47.269 ;
     RECT  63.264 45.445 63.288 47.315 ;
     RECT  31.344 46.645 37.812 47.363 ;
     RECT  56.4 46.835 56.712 47.413 ;
     RECT  42.432 47.269 43.848 47.699 ;
     RECT  32.1 47.363 37.812 47.797 ;
     RECT  69.792 42.709 70.212 47.845 ;
     RECT  39.456 45.635 40.512 47.891 ;
     RECT  72.48 43.861 72.912 47.891 ;
     RECT  56.4 47.413 56.808 47.987 ;
     RECT  45.504 46.693 45.912 48.227 ;
     RECT  64.5 46.787 64.92 48.371 ;
     RECT  59.1 46.787 59.412 48.373 ;
     RECT  60.432 45.587 60.456 48.373 ;
     RECT  53.7 45.539 54.312 48.467 ;
     RECT  49.584 47.701 49.608 48.515 ;
     RECT  32.1 47.797 38.184 48.901 ;
     RECT  55.296 48.421 55.32 48.949 ;
     RECT  48.3 46.211 48.612 48.997 ;
     RECT  59.1 48.373 60.456 49.189 ;
     RECT  28.128 45.541 28.152 49.235 ;
     RECT  64.5 48.371 64.812 49.333 ;
     RECT  29.4 7.859 29.712 49.381 ;
     RECT  28.32 49.381 29.712 49.525 ;
     RECT  31.92 48.901 38.184 49.715 ;
     RECT  42.432 47.699 43.512 49.715 ;
     RECT  48.096 48.997 48.612 49.763 ;
     RECT  68.976 47.845 70.212 49.763 ;
     RECT  59.1 49.189 60.648 50.051 ;
     RECT  55.152 48.949 55.32 50.147 ;
     RECT  28.32 49.525 30.312 50.389 ;
     RECT  31.92 49.715 38.04 50.389 ;
     RECT  28.32 50.389 38.04 50.819 ;
     RECT  64.5 49.333 65.256 50.965 ;
     RECT  26.7 10.451 27.012 51.253 ;
     RECT  28.32 50.819 29.832 51.253 ;
     RECT  51 47.075 51.312 51.253 ;
     RECT  26.7 51.253 29.832 51.299 ;
     RECT  24 14.435 24.312 51.829 ;
     RECT  45.6 48.227 45.912 51.829 ;
     RECT  53.7 48.467 54.012 51.829 ;
     RECT  59.1 50.051 59.832 51.923 ;
     RECT  69.216 49.763 70.212 51.923 ;
     RECT  28.752 51.299 29.832 51.925 ;
     RECT  31.104 50.819 38.04 51.925 ;
     RECT  28.752 51.925 38.04 52.019 ;
     RECT  26.7 51.299 27.432 52.067 ;
     RECT  28.896 52.019 38.04 52.259 ;
     RECT  24 51.829 24.792 52.309 ;
     RECT  45.6 51.829 46.152 52.499 ;
     RECT  55.296 50.147 55.32 52.739 ;
     RECT  64.5 50.965 65.544 52.739 ;
     RECT  48.3 49.763 48.612 52.981 ;
     RECT  23.28 52.309 24.792 53.267 ;
     RECT  56.4 47.987 56.712 53.317 ;
     RECT  52.992 51.829 54.012 53.363 ;
     RECT  56.4 53.317 56.808 53.509 ;
     RECT  31.872 52.259 38.04 53.555 ;
     RECT  48.192 52.981 48.612 53.555 ;
     RECT  63.12 50.101 63.144 53.603 ;
     RECT  56.4 53.509 57.048 53.699 ;
     RECT  21.3 2.151 21.612 53.749 ;
     RECT  23.28 53.267 24.312 53.795 ;
     RECT  26.7 52.067 27.012 54.037 ;
     RECT  26.7 54.037 27.288 54.085 ;
     RECT  59.1 51.923 59.592 54.085 ;
     RECT  53.7 53.363 54.012 54.517 ;
     RECT  42.432 49.715 43.212 54.613 ;
     RECT  44.256 51.109 44.28 54.613 ;
     RECT  39.744 47.891 40.512 54.659 ;
     RECT  48.3 53.555 48.612 54.661 ;
     RECT  50.112 51.253 51.312 54.851 ;
     RECT  67.2 39.923 67.512 54.997 ;
     RECT  42.432 54.613 44.28 55.283 ;
     RECT  25.728 54.085 27.288 55.331 ;
     RECT  39.888 54.659 40.512 55.475 ;
     RECT  59.1 54.085 59.784 55.475 ;
     RECT  18.6 2.151 18.912 55.813 ;
     RECT  56.4 53.699 56.856 55.813 ;
     RECT  50.88 54.851 51.312 55.907 ;
     RECT  69.408 51.923 70.212 56.003 ;
     RECT  53.568 54.517 54.012 56.005 ;
     RECT  48.192 54.661 48.612 56.099 ;
     RECT  26.7 55.331 27.288 56.293 ;
     RECT  48.3 56.099 48.612 56.389 ;
     RECT  64.5 52.739 64.92 56.389 ;
     RECT  21.3 53.749 21.72 56.531 ;
     RECT  67.2 54.997 67.752 56.531 ;
     RECT  18.6 55.813 19.032 56.581 ;
     RECT  18.24 56.581 19.032 56.627 ;
     RECT  28.896 52.259 30.744 56.725 ;
     RECT  31.92 53.555 38.04 56.725 ;
     RECT  24 53.795 24.312 56.773 ;
     RECT  64.032 56.389 64.92 56.867 ;
     RECT  56.4 55.813 57.528 56.917 ;
     RECT  59.1 55.475 59.736 56.917 ;
     RECT  53.568 56.005 54.12 57.059 ;
     RECT  69.504 56.003 70.212 57.059 ;
     RECT  45.6 52.499 45.912 57.445 ;
     RECT  51 55.907 51.312 57.445 ;
     RECT  26.592 56.293 27.288 57.541 ;
     RECT  28.896 56.725 38.04 57.541 ;
     RECT  67.2 56.531 67.512 57.541 ;
     RECT  56.4 56.917 59.736 57.589 ;
     RECT  18.24 56.627 18.912 57.875 ;
     RECT  64.032 56.867 64.812 57.875 ;
     RECT  69.9 57.059 70.212 57.925 ;
     RECT  26.592 57.541 38.04 57.973 ;
     RECT  45.6 57.445 46.68 58.163 ;
     RECT  51 57.445 51.528 58.163 ;
     RECT  26.112 57.973 38.04 58.355 ;
     RECT  56.16 57.589 59.736 58.355 ;
     RECT  56.16 58.355 56.712 58.643 ;
     RECT  44.256 55.283 44.28 58.645 ;
     RECT  45.6 58.163 45.912 58.645 ;
     RECT  28.176 58.355 38.04 58.691 ;
     RECT  24 56.773 24.408 58.981 ;
     RECT  40.2 55.475 40.512 58.981 ;
     RECT  21.3 56.531 21.612 59.029 ;
     RECT  61.8 43.043 62.112 59.029 ;
     RECT  28.368 58.691 38.04 59.171 ;
     RECT  26.112 58.355 27.012 59.315 ;
     RECT  44.256 58.645 45.912 59.315 ;
     RECT  48.3 56.389 49.176 59.459 ;
     RECT  69.9 57.925 70.344 59.459 ;
     RECT  34.08 59.171 38.04 59.603 ;
     RECT  24 58.981 24.888 59.749 ;
     RECT  42.432 55.283 43.212 59.797 ;
     RECT  56.4 58.643 56.712 59.797 ;
     RECT  28.368 59.171 33.048 59.845 ;
     RECT  28.032 59.845 33.048 60.373 ;
     RECT  34.08 59.603 36.456 60.373 ;
     RECT  53.568 57.059 54.012 60.373 ;
     RECT  69.9 59.459 70.212 60.373 ;
     RECT  61.8 59.029 62.232 60.419 ;
     RECT  37.5 59.603 38.04 60.467 ;
     RECT  41.616 59.797 43.212 60.563 ;
     RECT  55.872 59.797 56.712 60.563 ;
     RECT  68.928 60.373 70.212 60.563 ;
     RECT  56.4 60.563 56.712 60.661 ;
     RECT  45.6 59.315 45.912 60.805 ;
     RECT  21.3 59.029 22.104 60.851 ;
     RECT  44.256 59.315 44.28 60.851 ;
     RECT  26.7 59.315 27.012 60.901 ;
     RECT  28.032 60.373 36.456 60.901 ;
     RECT  45.6 60.805 46.728 60.997 ;
     RECT  48.3 59.459 48.744 60.997 ;
     RECT  24 59.749 25.704 61.043 ;
     RECT  56.4 60.661 56.856 61.091 ;
     RECT  53.52 60.373 54.012 61.093 ;
     RECT  42.432 60.563 43.212 61.139 ;
     RECT  45.6 60.997 48.744 61.139 ;
     RECT  49.824 60.373 49.848 61.139 ;
     RECT  45.6 61.139 48.612 61.379 ;
     RECT  58.368 58.355 59.736 61.379 ;
     RECT  24 61.043 24.888 61.381 ;
     RECT  23.184 61.381 24.888 61.429 ;
     RECT  18.48 57.875 18.912 61.619 ;
     RECT  26.7 60.901 36.456 62.051 ;
     RECT  21.3 60.851 21.612 62.053 ;
     RECT  42.9 61.139 43.212 62.341 ;
     RECT  22.752 61.429 24.888 62.389 ;
     RECT  22.608 62.389 24.888 62.435 ;
     RECT  47.328 61.379 48.612 62.581 ;
     RECT  58.656 61.379 59.736 62.581 ;
     RECT  69.552 60.563 70.212 62.629 ;
     RECT  58.608 62.581 59.736 62.771 ;
     RECT  23.616 62.435 24.312 63.107 ;
     RECT  26.7 62.051 35.88 63.205 ;
     RECT  42.9 62.341 44.088 63.251 ;
     RECT  53.52 61.093 54.12 63.299 ;
     RECT  45.6 61.379 45.912 63.445 ;
     RECT  47.328 62.581 48.888 63.445 ;
     RECT  45.6 63.445 48.888 63.491 ;
     RECT  40.08 58.981 40.512 63.685 ;
     RECT  51 58.163 51.312 63.829 ;
     RECT  26.064 63.205 35.88 63.875 ;
     RECT  48.3 63.491 48.888 63.875 ;
     RECT  39.312 63.685 40.512 63.923 ;
     RECT  26.064 63.875 35.112 64.019 ;
     RECT  58.608 62.771 59.412 64.261 ;
     RECT  64.5 57.875 64.812 64.405 ;
     RECT  66.24 57.541 67.512 64.405 ;
     RECT  61.8 60.419 62.112 64.741 ;
     RECT  50.88 63.829 51.312 64.885 ;
     RECT  36.432 64.357 36.456 64.933 ;
     RECT  45.6 63.491 46.776 64.933 ;
     RECT  56.4 61.091 56.712 64.933 ;
     RECT  58.512 64.261 59.412 64.933 ;
     RECT  56.4 64.933 59.412 65.029 ;
     RECT  53.7 63.299 54.012 65.173 ;
     RECT  56.4 65.029 59.928 65.219 ;
     RECT  53.7 65.173 54.12 65.317 ;
     RECT  50.112 64.885 51.312 65.411 ;
     RECT  61.248 64.741 62.112 65.555 ;
     RECT  26.7 64.019 35.112 65.603 ;
     RECT  53.568 65.317 54.12 65.651 ;
     RECT  20.544 62.053 21.612 65.699 ;
     RECT  28.272 65.603 35.112 65.699 ;
     RECT  56.4 65.219 59.412 65.699 ;
     RECT  36.384 64.933 36.456 66.179 ;
     RECT  21.168 65.699 21.612 66.227 ;
     RECT  44.208 64.357 44.232 66.227 ;
     RECT  45.6 64.933 46.872 66.227 ;
     RECT  42.9 63.251 43.212 66.469 ;
     RECT  28.272 65.699 33.096 66.661 ;
     RECT  34.08 65.699 35.112 66.661 ;
     RECT  42.768 66.469 43.212 66.661 ;
     RECT  50.88 65.411 51.312 66.899 ;
     RECT  28.272 66.661 35.112 66.901 ;
     RECT  28.272 66.901 35.304 67.043 ;
     RECT  42.144 66.661 43.212 67.043 ;
     RECT  53.568 65.651 54.012 67.091 ;
     RECT  26.7 65.603 27.012 67.093 ;
     RECT  28.272 67.043 35.112 67.093 ;
     RECT  37.5 60.467 37.812 67.093 ;
     RECT  37.5 67.093 38.616 67.189 ;
     RECT  49.728 66.085 49.752 67.283 ;
     RECT  64.5 64.405 67.512 67.283 ;
     RECT  45.6 66.227 45.912 67.669 ;
     RECT  46.944 66.661 46.968 67.669 ;
     RECT  36.432 66.179 36.456 67.715 ;
     RECT  37.5 67.189 39.144 67.765 ;
     RECT  48.3 63.875 48.612 67.813 ;
     RECT  45.6 67.669 46.968 67.859 ;
     RECT  56.4 65.699 57.144 67.859 ;
     RECT  64.5 67.283 65.544 68.003 ;
     RECT  53.7 67.091 54.012 68.149 ;
     RECT  51 66.899 51.312 68.197 ;
     RECT  58.512 65.699 59.412 68.197 ;
     RECT  24 63.107 24.312 68.341 ;
     RECT  69.408 62.629 70.212 68.389 ;
     RECT  37.008 67.765 39.144 68.435 ;
     RECT  37.008 68.435 38.616 68.627 ;
     RECT  45.6 67.859 45.912 68.917 ;
     RECT  53.568 68.149 54.012 68.917 ;
     RECT  58.368 68.197 59.412 68.917 ;
     RECT  37.5 68.627 38.616 69.011 ;
     RECT  56.4 67.859 56.712 69.109 ;
     RECT  58.08 68.917 59.412 69.109 ;
     RECT  53.424 68.917 54.012 69.493 ;
     RECT  56.4 69.109 59.412 69.493 ;
     RECT  26.7 67.093 35.112 69.829 ;
     RECT  56.208 69.493 59.412 69.829 ;
     RECT  48.3 67.813 48.744 70.019 ;
     RECT  24 68.341 24.504 70.163 ;
     RECT  45.6 68.917 46.008 70.307 ;
     RECT  42.576 67.043 43.212 70.403 ;
     RECT  53.376 69.493 54.012 70.405 ;
     RECT  61.8 65.555 62.112 70.405 ;
     RECT  24 70.163 24.312 70.549 ;
     RECT  25.776 69.829 35.112 70.595 ;
     RECT  40.2 63.923 40.512 70.645 ;
     RECT  64.5 68.003 64.92 70.691 ;
     RECT  25.632 70.645 25.656 70.693 ;
     RECT  55.824 69.829 59.412 70.693 ;
     RECT  51 68.197 52.248 70.739 ;
     RECT  68.928 68.389 70.212 70.739 ;
     RECT  22.608 62.435 22.632 70.835 ;
     RECT  39.408 70.645 40.512 70.933 ;
     RECT  21.3 66.227 21.612 71.221 ;
     RECT  23.808 70.549 24.312 71.221 ;
     RECT  25.344 70.693 25.656 71.221 ;
     RECT  23.808 71.221 25.656 71.315 ;
     RECT  39.408 70.933 40.776 71.315 ;
     RECT  24 71.315 25.656 71.459 ;
     RECT  25.632 71.459 25.656 71.651 ;
     RECT  26.7 70.595 35.112 71.653 ;
     RECT  45.6 70.307 45.912 71.797 ;
     RECT  48.3 70.019 48.612 71.797 ;
     RECT  53.376 70.405 54.216 71.797 ;
     RECT  61.8 70.405 62.952 71.891 ;
     RECT  48.3 71.797 48.84 71.939 ;
     RECT  45.6 71.797 46.056 71.987 ;
     RECT  37.5 69.011 37.812 71.989 ;
     RECT  21.3 71.221 21.72 72.131 ;
     RECT  24 71.459 24.504 72.179 ;
     RECT  55.584 70.693 59.412 72.325 ;
     RECT  26.544 71.653 35.112 72.757 ;
     RECT  26.496 72.757 35.112 72.901 ;
     RECT  53.328 71.797 54.504 72.901 ;
     RECT  55.488 72.325 59.412 72.901 ;
     RECT  42.672 70.403 43.212 72.995 ;
     RECT  48.3 71.939 48.612 73.093 ;
     RECT  40.2 71.315 40.776 73.235 ;
     RECT  53.088 72.901 59.412 73.477 ;
     RECT  26.496 72.901 35.208 73.619 ;
     RECT  37.008 71.989 37.812 73.909 ;
     RECT  26.7 73.619 35.208 73.957 ;
     RECT  44.448 71.701 44.472 74.051 ;
     RECT  48.3 73.093 49.56 74.147 ;
     RECT  47.28 71.461 47.304 74.581 ;
     RECT  48.3 74.147 48.612 74.581 ;
     RECT  26.7 73.957 35.304 74.723 ;
     RECT  42.768 72.995 43.212 74.867 ;
     RECT  38.784 72.037 38.808 74.915 ;
     RECT  51 70.739 51.312 75.205 ;
     RECT  52.896 73.477 59.412 75.205 ;
     RECT  26.7 74.723 35.112 75.299 ;
     RECT  36.864 73.909 37.812 75.299 ;
     RECT  47.28 74.581 48.612 75.299 ;
     RECT  51 75.205 59.412 75.299 ;
     RECT  2.4 2.151 2.712 75.609 ;
     RECT  5.1 2.151 5.412 75.609 ;
     RECT  7.8 2.151 8.112 75.609 ;
     RECT  10.5 2.151 10.812 75.609 ;
     RECT  13.2 2.151 13.512 75.609 ;
     RECT  15.9 2.151 16.212 75.609 ;
     RECT  18.6 61.619 18.912 75.609 ;
     RECT  21.3 72.131 21.612 75.609 ;
     RECT  24 72.179 24.312 75.609 ;
     RECT  26.7 75.299 27.012 75.609 ;
     RECT  28.032 75.299 35.112 75.609 ;
     RECT  37.5 75.299 37.812 75.609 ;
     RECT  40.2 73.235 40.512 75.609 ;
     RECT  42.9 74.867 43.212 75.609 ;
     RECT  45.6 71.987 45.912 75.609 ;
     RECT  48.3 75.299 48.612 75.609 ;
     RECT  51 75.299 58.008 75.609 ;
     RECT  59.1 75.299 59.412 75.609 ;
     RECT  61.8 71.891 62.112 75.609 ;
     RECT  64.5 70.691 64.812 75.609 ;
     RECT  67.2 67.283 67.512 75.609 ;
     RECT  69.9 70.739 70.212 75.609 ;
     RECT  72.6 47.891 72.912 75.609 ;
     RECT  75.3 45.731 75.612 75.609 ;
     RECT  78 2.151 78.312 75.609 ;
     RECT  80.7 2.151 81.012 75.609 ;
     RECT  83.4 2.151 83.712 75.609 ;
     RECT  2.4 75.609 2.52 75.623 ;
     RECT  5.1 75.609 5.22 75.623 ;
     RECT  7.8 75.609 7.92 75.623 ;
     RECT  10.5 75.609 10.62 75.623 ;
     RECT  13.2 75.609 13.32 75.623 ;
     RECT  15.9 75.609 16.02 75.623 ;
     RECT  18.6 75.609 18.72 75.623 ;
     RECT  21.3 75.609 21.42 75.623 ;
     RECT  24 75.609 24.12 75.623 ;
     RECT  26.7 75.609 26.82 75.623 ;
     RECT  28.032 75.609 34.92 75.623 ;
     RECT  37.5 75.609 37.62 75.623 ;
     RECT  40.2 75.609 40.32 75.623 ;
     RECT  42.9 75.609 43.176 75.623 ;
     RECT  45.6 75.609 45.72 75.623 ;
     RECT  48.3 75.609 48.42 75.623 ;
     RECT  51 75.609 51.12 75.623 ;
     RECT  59.1 75.609 59.22 75.623 ;
     RECT  61.8 75.609 61.92 75.623 ;
     RECT  64.5 75.609 64.62 75.623 ;
     RECT  67.2 75.609 67.32 75.623 ;
     RECT  69.9 75.609 70.02 75.623 ;
     RECT  72.6 75.609 72.72 75.623 ;
     RECT  75.3 75.609 75.42 75.623 ;
     RECT  78 75.609 78.12 75.623 ;
     RECT  80.7 75.609 80.82 75.623 ;
     RECT  83.4 75.609 83.52 75.623 ;
     RECT  52.128 75.609 58.008 76.885 ;
     RECT  52.032 76.885 58.008 77.461 ;
     RECT  28.032 75.623 34.296 77.712 ;
     RECT  52.032 77.461 58.296 77.712 ;
     RECT  28.032 0.611 28.128 1.763 ;
     RECT  28.032 1.763 28.608 2.137 ;
     RECT  26.82 2.137 28.608 2.151 ;
     RECT  27.012 2.151 28.608 2.773 ;
     RECT  27.012 2.773 28.128 3.301 ;
     RECT  27.144 3.301 28.128 5.171 ;
     RECT  29.712 4.019 31.2 4.067 ;
     RECT  29.712 4.067 31.68 4.595 ;
     RECT  29.712 4.595 31.824 4.643 ;
     RECT  29.712 4.643 31.872 5.077 ;
     RECT  29.712 5.077 30.72 8.003 ;
     RECT  30.744 5.077 31.872 5.893 ;
     RECT  30.744 5.893 31.824 8.003 ;
     RECT  33.144 6.371 34.656 6.947 ;
     RECT  33.144 6.947 34.704 7.765 ;
     RECT  33.48 7.765 34.704 18.275 ;
     RECT  31.68 8.003 31.824 8.485 ;
     RECT  36.12 9.925 37.5 14.339 ;
     RECT  27.144 10.405 28.128 10.451 ;
     RECT  28.152 10.405 29.4 10.931 ;
     RECT  27.012 10.451 28.128 10.931 ;
     RECT  33.48 18.275 34.8 27.205 ;
     RECT  41.016 21.445 42.432 22.741 ;
     RECT  41.016 22.741 42.336 23.987 ;
     RECT  41.016 23.987 42.432 25.237 ;
     RECT  37.944 25.045 39.024 28.163 ;
     RECT  39.048 25.045 40.2 28.021 ;
     RECT  51.312 25.141 52.464 25.427 ;
     RECT  52.488 25.141 53.52 25.427 ;
     RECT  41.016 25.237 42.24 25.715 ;
     RECT  51.312 25.427 53.52 26.053 ;
     RECT  41.016 25.715 42.432 27.395 ;
     RECT  51.312 26.053 52.56 31.525 ;
     RECT  42.096 27.395 42.432 27.829 ;
     RECT  42.096 27.829 42.336 27.877 ;
     RECT  37.944 28.163 39.36 30.757 ;
     RECT  33.48 29.075 34.8 43.813 ;
     RECT  52.584 29.267 53.7 34.403 ;
     RECT  35.208 30.133 36.576 31.813 ;
     RECT  67.512 30.133 68.832 30.899 ;
     RECT  68.856 30.133 69.9 30.899 ;
     RECT  37.812 31.427 37.944 32.437 ;
     RECT  35.304 31.813 36.576 33.589 ;
     RECT  54.012 31.861 55.2 32.771 ;
     RECT  55.224 31.861 56.4 32.771 ;
     RECT  62.112 31.909 63.408 34.259 ;
     RECT  63.432 31.909 64.5 34.259 ;
     RECT  70.344 32.341 71.424 32.581 ;
     RECT  71.448 32.341 72.6 33.445 ;
     RECT  51.312 33.155 52.56 34.403 ;
     RECT  64.812 34.357 66.144 35.027 ;
     RECT  66.168 34.403 67.2 35.027 ;
     RECT  71.448 35.939 72.6 37.091 ;
     RECT  37.812 35.989 39.168 37.091 ;
     RECT  64.812 37.043 64.92 38.101 ;
     RECT  67.8 37.429 68.976 38.915 ;
     RECT  46.776 38.341 48.3 38.483 ;
     RECT  56.16 38.675 56.4 39.781 ;
     RECT  50.832 38.723 51 39.877 ;
     RECT  40.512 38.963 42.432 40.405 ;
     RECT  37.812 39.733 39.312 41.269 ;
     RECT  41.064 40.405 42.432 42.419 ;
     RECT  35.448 41.075 36.576 42.803 ;
     RECT  37.812 41.269 39.024 42.227 ;
     RECT  59.412 42.133 60.672 45.541 ;
     RECT  37.812 42.227 39.312 44.773 ;
     RECT  49.032 42.229 50.16 42.709 ;
     RECT  49.56 42.755 51 46.211 ;
     RECT  51.312 42.755 51.768 44.245 ;
     RECT  35.448 42.803 37.5 43.285 ;
     RECT  60.696 43.043 61.8 45.587 ;
     RECT  35.448 43.285 36.48 45.541 ;
     RECT  36.504 43.285 37.5 45.685 ;
     RECT  33.672 43.813 34.8 45.541 ;
     RECT  46.872 44.437 48.3 46.499 ;
     RECT  57.576 44.437 59.1 44.965 ;
     RECT  51.864 44.677 53.136 45.493 ;
     RECT  38.232 44.773 39.312 45.635 ;
     RECT  54.312 45.205 55.824 46.067 ;
     RECT  62.112 45.445 63.264 47.315 ;
     RECT  63.288 45.445 64.5 47.315 ;
     RECT  52.584 45.539 53.7 47.123 ;
     RECT  27.012 45.541 28.128 49.235 ;
     RECT  28.152 45.541 29.4 49.235 ;
     RECT  59.412 45.541 60.432 48.373 ;
     RECT  60.456 45.587 61.8 49.189 ;
     RECT  38.232 45.635 39.456 46.499 ;
     RECT  48.612 46.211 51 47.701 ;
     RECT  37.812 46.499 39.456 47.797 ;
     RECT  51.312 47.075 52.56 47.123 ;
     RECT  48.612 47.701 49.584 48.515 ;
     RECT  49.608 47.701 51 48.515 ;
     RECT  38.184 47.797 39.456 47.891 ;
     RECT  67.512 47.845 68.976 49.763 ;
     RECT  64.812 48.371 64.92 49.333 ;
     RECT  54.312 48.421 55.296 48.467 ;
     RECT  55.32 48.421 56.4 52.739 ;
     RECT  54.012 48.467 55.296 48.949 ;
     RECT  54.012 48.949 55.152 50.147 ;
     RECT  60.648 49.189 61.8 50.051 ;
     RECT  27.012 49.235 29.4 49.381 ;
     RECT  27.012 49.381 28.32 51.253 ;
     RECT  43.212 49.715 43.512 51.109 ;
     RECT  62.112 50.101 63.12 53.603 ;
     RECT  63.144 50.101 64.5 53.603 ;
     RECT  54.012 50.147 55.296 52.739 ;
     RECT  29.832 50.819 31.104 51.925 ;
     RECT  43.212 51.109 44.256 54.613 ;
     RECT  44.28 51.109 45.6 58.645 ;
     RECT  48.612 51.253 50.112 54.851 ;
     RECT  27.432 51.299 28.752 52.019 ;
     RECT  27.432 52.019 28.896 52.067 ;
     RECT  30.744 52.259 31.872 53.555 ;
     RECT  24.312 53.267 24.792 54.085 ;
     RECT  53.568 53.363 53.7 54.517 ;
     RECT  30.744 53.555 31.92 56.725 ;
     RECT  48.192 53.555 48.3 54.661 ;
     RECT  24.312 54.085 25.728 55.331 ;
     RECT  43.212 55.283 44.256 60.851 ;
     RECT  24.312 55.331 24.408 56.773 ;
     RECT  26.592 55.331 26.7 56.293 ;
     RECT  64.812 56.867 64.92 57.541 ;
     RECT  64.812 57.541 66.24 64.405 ;
     RECT  27.012 58.355 28.176 58.691 ;
     RECT  56.16 58.643 56.4 59.797 ;
     RECT  27.012 58.691 28.368 59.845 ;
     RECT  24.888 58.981 26.112 59.315 ;
     RECT  33.048 59.171 34.08 60.373 ;
     RECT  24.888 59.315 26.7 59.749 ;
     RECT  44.28 59.315 45.6 60.851 ;
     RECT  48.744 59.459 49.176 60.373 ;
     RECT  36.456 59.603 37.5 62.051 ;
     RECT  25.704 59.749 26.7 61.043 ;
     RECT  40.512 59.797 41.616 60.563 ;
     RECT  27.012 59.845 28.032 60.901 ;
     RECT  48.744 60.373 49.824 61.139 ;
     RECT  49.848 60.373 51 61.139 ;
     RECT  67.512 60.373 68.928 60.563 ;
     RECT  56.856 60.661 58.368 61.091 ;
     RECT  21.612 60.851 22.104 61.381 ;
     RECT  43.212 60.851 45.6 62.341 ;
     RECT  48.612 61.139 48.888 62.581 ;
     RECT  45.912 61.379 47.328 63.445 ;
     RECT  58.608 61.379 58.656 62.581 ;
     RECT  21.612 61.381 23.184 61.429 ;
     RECT  21.612 61.429 22.752 62.389 ;
     RECT  44.088 62.341 45.6 63.251 ;
     RECT  21.612 62.389 22.608 70.835 ;
     RECT  22.632 62.435 23.616 63.107 ;
     RECT  22.632 63.107 24 70.549 ;
     RECT  43.212 63.251 45.6 64.357 ;
     RECT  46.776 63.491 48.3 64.933 ;
     RECT  37.812 63.685 39.312 63.923 ;
     RECT  35.112 63.875 35.88 64.357 ;
     RECT  48.612 63.875 48.888 64.885 ;
     RECT  35.112 64.357 36.432 64.933 ;
     RECT  36.456 64.357 37.5 67.715 ;
     RECT  43.212 64.357 44.208 66.227 ;
     RECT  44.232 64.357 45.6 66.227 ;
     RECT  48.612 64.885 50.112 65.411 ;
     RECT  35.112 64.933 36.384 66.179 ;
     RECT  46.872 64.933 48.3 66.227 ;
     RECT  59.928 65.029 61.248 65.219 ;
     RECT  48.612 65.411 50.88 66.085 ;
     RECT  27.012 65.603 28.272 67.093 ;
     RECT  33.096 65.699 34.08 66.661 ;
     RECT  57.144 65.699 58.512 67.859 ;
     RECT  48.612 66.085 49.728 67.283 ;
     RECT  49.752 66.085 50.88 66.899 ;
     RECT  35.112 66.179 36.432 66.901 ;
     RECT  45.912 66.227 48.3 66.661 ;
     RECT  45.912 66.661 46.944 67.669 ;
     RECT  46.968 66.661 48.3 67.859 ;
     RECT  49.752 66.899 51 67.283 ;
     RECT  35.304 66.901 36.432 67.043 ;
     RECT  35.112 67.043 36.432 67.715 ;
     RECT  53.568 67.091 53.7 68.149 ;
     RECT  39.144 67.189 40.2 68.435 ;
     RECT  48.612 67.283 48.744 67.813 ;
     RECT  37.008 67.715 37.5 67.765 ;
     RECT  45.912 67.859 46.008 68.917 ;
     RECT  56.712 67.859 58.512 68.197 ;
     RECT  52.248 68.197 53.568 68.917 ;
     RECT  56.712 68.197 58.368 68.917 ;
     RECT  67.512 68.389 68.928 70.739 ;
     RECT  52.248 68.917 53.424 69.493 ;
     RECT  56.712 68.917 58.08 69.109 ;
     RECT  52.248 69.493 53.376 70.739 ;
     RECT  24.504 69.829 25.776 70.163 ;
     RECT  24.312 70.163 25.776 70.595 ;
     RECT  45.912 70.307 46.008 71.461 ;
     RECT  22.632 70.549 23.808 70.835 ;
     RECT  24.312 70.595 26.7 70.645 ;
     RECT  24.312 70.645 25.632 70.693 ;
     RECT  25.656 70.645 26.7 71.651 ;
     RECT  24.312 70.693 25.344 71.221 ;
     RECT  54.216 70.693 55.584 71.797 ;
     RECT  53.328 70.739 53.376 71.797 ;
     RECT  21.612 70.835 21.72 71.221 ;
     RECT  39.408 71.315 40.2 72.037 ;
     RECT  24.504 71.459 25.632 71.651 ;
     RECT  45.912 71.461 47.28 71.797 ;
     RECT  47.304 71.461 48.3 74.581 ;
     RECT  26.496 71.651 26.7 71.653 ;
     RECT  26.496 71.653 26.544 72.757 ;
     RECT  43.212 71.701 44.448 74.051 ;
     RECT  44.472 71.701 45.6 74.051 ;
     RECT  46.056 71.797 47.28 71.987 ;
     RECT  54.504 71.797 55.584 72.325 ;
     RECT  48.612 71.939 48.84 73.093 ;
     RECT  45.912 71.987 47.28 75.299 ;
     RECT  37.812 72.037 38.784 74.915 ;
     RECT  38.808 72.037 40.2 74.915 ;
     RECT  54.504 72.325 55.488 72.901 ;
     RECT  49.56 73.093 51 74.147 ;
     RECT  27.012 75.299 28.032 75.609 ;
     RECT  58.008 75.299 59.1 75.623 ;
     RECT  26.82 75.609 28.032 75.623 ;
     RECT  51.12 75.609 52.128 75.623 ;
     RECT  52.032 75.623 52.128 76.885 ;
  END
END dsfd_node_NNfu
END LIBRARY
